VERSION 5.8 ;
BUSBITCHARS "[]" ;
DIVIDERCHAR "/" ;
UNITS
    DATABASE MICRONS 1000 ;
END UNITS

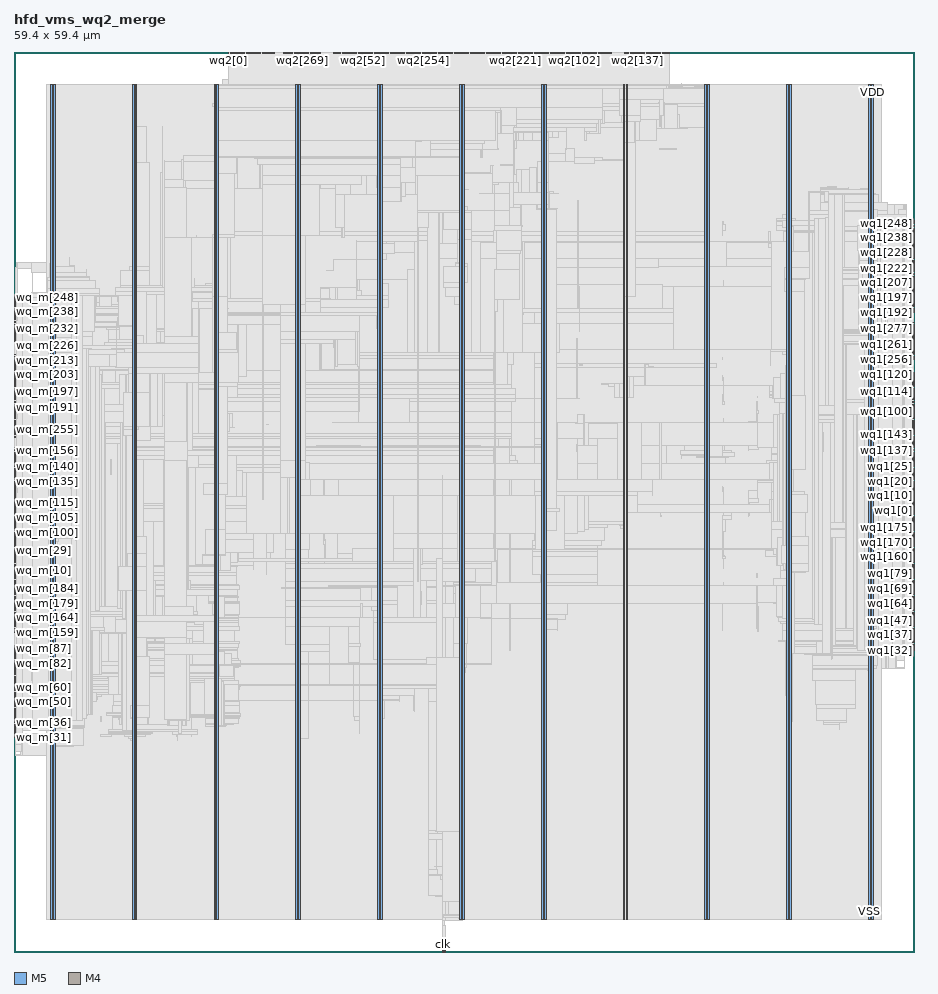
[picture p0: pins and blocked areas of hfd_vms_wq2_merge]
MACRO hfd_vms_wq2_merge
  FOREIGN hfd_vms_wq2_merge 0 0 ;
  CLASS BLOCK ;
  SIZE 59.4 BY 59.4 ;
  PIN clk
    DIRECTION INPUT ;
    USE SIGNAL ;
    PORT
      LAYER M5 ;
        RECT  28.272 0 28.296 0.084 ;
    END
  END clk
  PIN done_m
    DIRECTION INPUT ;
    USE SIGNAL ;
    PORT
      LAYER M4 ;
        RECT  0 24.144 0.084 24.168 ;
    END
  END done_m
  PIN flt
    DIRECTION OUTPUT ;
    USE SIGNAL ;
    PORT
      LAYER M5 ;
        RECT  28.368 0 28.392 0.084 ;
    END
  END flt
  PIN rst_n
    DIRECTION INPUT ;
    USE SIGNAL ;
    PORT
      LAYER M5 ;
        RECT  28.464 0 28.488 0.084 ;
    END
  END rst_n
  PIN wq1[0]
    DIRECTION INPUT ;
    USE SIGNAL ;
    PORT
      LAYER M4 ;
        RECT  59.316 29.136 59.4 29.16 ;
    END
  END wq1[0]
  PIN wq1[100]
    DIRECTION INPUT ;
    USE SIGNAL ;
    PORT
      LAYER M4 ;
        RECT  59.316 35.664 59.4 35.688 ;
    END
  END wq1[100]
  PIN wq1[101]
    DIRECTION INPUT ;
    USE SIGNAL ;
    PORT
      LAYER M4 ;
        RECT  59.316 35.76 59.4 35.784 ;
    END
  END wq1[101]
  PIN wq1[102]
    DIRECTION INPUT ;
    USE SIGNAL ;
    PORT
      LAYER M4 ;
        RECT  59.316 35.856 59.4 35.88 ;
    END
  END wq1[102]
  PIN wq1[103]
    DIRECTION INPUT ;
    USE SIGNAL ;
    PORT
      LAYER M4 ;
        RECT  59.316 35.952 59.4 35.976 ;
    END
  END wq1[103]
  PIN wq1[104]
    DIRECTION INPUT ;
    USE SIGNAL ;
    PORT
      LAYER M4 ;
        RECT  59.316 36.048 59.4 36.072 ;
    END
  END wq1[104]
  PIN wq1[105]
    DIRECTION INPUT ;
    USE SIGNAL ;
    PORT
      LAYER M4 ;
        RECT  59.316 36.144 59.4 36.168 ;
    END
  END wq1[105]
  PIN wq1[106]
    DIRECTION INPUT ;
    USE SIGNAL ;
    PORT
      LAYER M4 ;
        RECT  59.316 36.24 59.4 36.264 ;
    END
  END wq1[106]
  PIN wq1[107]
    DIRECTION INPUT ;
    USE SIGNAL ;
    PORT
      LAYER M4 ;
        RECT  59.316 36.336 59.4 36.36 ;
    END
  END wq1[107]
  PIN wq1[108]
    DIRECTION INPUT ;
    USE SIGNAL ;
    PORT
      LAYER M4 ;
        RECT  59.316 36.432 59.4 36.456 ;
    END
  END wq1[108]
  PIN wq1[109]
    DIRECTION INPUT ;
    USE SIGNAL ;
    PORT
      LAYER M4 ;
        RECT  59.316 36.528 59.4 36.552 ;
    END
  END wq1[109]
  PIN wq1[10]
    DIRECTION INPUT ;
    USE SIGNAL ;
    PORT
      LAYER M4 ;
        RECT  59.316 30.096 59.4 30.12 ;
    END
  END wq1[10]
  PIN wq1[110]
    DIRECTION INPUT ;
    USE SIGNAL ;
    PORT
      LAYER M4 ;
        RECT  59.316 36.624 59.4 36.648 ;
    END
  END wq1[110]
  PIN wq1[111]
    DIRECTION INPUT ;
    USE SIGNAL ;
    PORT
      LAYER M4 ;
        RECT  59.316 36.72 59.4 36.744 ;
    END
  END wq1[111]
  PIN wq1[112]
    DIRECTION INPUT ;
    USE SIGNAL ;
    PORT
      LAYER M4 ;
        RECT  59.316 36.816 59.4 36.84 ;
    END
  END wq1[112]
  PIN wq1[113]
    DIRECTION INPUT ;
    USE SIGNAL ;
    PORT
      LAYER M4 ;
        RECT  59.316 36.912 59.4 36.936 ;
    END
  END wq1[113]
  PIN wq1[114]
    DIRECTION INPUT ;
    USE SIGNAL ;
    PORT
      LAYER M4 ;
        RECT  59.316 37.008 59.4 37.032 ;
    END
  END wq1[114]
  PIN wq1[115]
    DIRECTION INPUT ;
    USE SIGNAL ;
    PORT
      LAYER M4 ;
        RECT  59.316 37.104 59.4 37.128 ;
    END
  END wq1[115]
  PIN wq1[116]
    DIRECTION INPUT ;
    USE SIGNAL ;
    PORT
      LAYER M4 ;
        RECT  59.316 37.2 59.4 37.224 ;
    END
  END wq1[116]
  PIN wq1[117]
    DIRECTION INPUT ;
    USE SIGNAL ;
    PORT
      LAYER M4 ;
        RECT  59.316 37.296 59.4 37.32 ;
    END
  END wq1[117]
  PIN wq1[118]
    DIRECTION INPUT ;
    USE SIGNAL ;
    PORT
      LAYER M4 ;
        RECT  59.316 37.392 59.4 37.416 ;
    END
  END wq1[118]
  PIN wq1[119]
    DIRECTION INPUT ;
    USE SIGNAL ;
    PORT
      LAYER M4 ;
        RECT  59.316 37.488 59.4 37.512 ;
    END
  END wq1[119]
  PIN wq1[11]
    DIRECTION INPUT ;
    USE SIGNAL ;
    PORT
      LAYER M4 ;
        RECT  59.316 30.192 59.4 30.216 ;
    END
  END wq1[11]
  PIN wq1[120]
    DIRECTION INPUT ;
    USE SIGNAL ;
    PORT
      LAYER M4 ;
        RECT  59.316 37.584 59.4 37.608 ;
    END
  END wq1[120]
  PIN wq1[121]
    DIRECTION INPUT ;
    USE SIGNAL ;
    PORT
      LAYER M4 ;
        RECT  59.316 37.68 59.4 37.704 ;
    END
  END wq1[121]
  PIN wq1[122]
    DIRECTION INPUT ;
    USE SIGNAL ;
    PORT
      LAYER M4 ;
        RECT  59.316 37.776 59.4 37.8 ;
    END
  END wq1[122]
  PIN wq1[123]
    DIRECTION INPUT ;
    USE SIGNAL ;
    PORT
      LAYER M4 ;
        RECT  59.316 37.872 59.4 37.896 ;
    END
  END wq1[123]
  PIN wq1[124]
    DIRECTION INPUT ;
    USE SIGNAL ;
    PORT
      LAYER M4 ;
        RECT  59.316 37.968 59.4 37.992 ;
    END
  END wq1[124]
  PIN wq1[125]
    DIRECTION INPUT ;
    USE SIGNAL ;
    PORT
      LAYER M4 ;
        RECT  59.316 38.064 59.4 38.088 ;
    END
  END wq1[125]
  PIN wq1[126]
    DIRECTION INPUT ;
    USE SIGNAL ;
    PORT
      LAYER M4 ;
        RECT  59.316 38.16 59.4 38.184 ;
    END
  END wq1[126]
  PIN wq1[127]
    DIRECTION INPUT ;
    USE SIGNAL ;
    PORT
      LAYER M4 ;
        RECT  59.316 38.256 59.4 38.28 ;
    END
  END wq1[127]
  PIN wq1[128]
    DIRECTION INPUT ;
    USE SIGNAL ;
    PORT
      LAYER M4 ;
        RECT  59.316 32.208 59.4 32.232 ;
    END
  END wq1[128]
  PIN wq1[129]
    DIRECTION INPUT ;
    USE SIGNAL ;
    PORT
      LAYER M4 ;
        RECT  59.316 32.304 59.4 32.328 ;
    END
  END wq1[129]
  PIN wq1[12]
    DIRECTION INPUT ;
    USE SIGNAL ;
    PORT
      LAYER M4 ;
        RECT  59.316 30.288 59.4 30.312 ;
    END
  END wq1[12]
  PIN wq1[130]
    DIRECTION INPUT ;
    USE SIGNAL ;
    PORT
      LAYER M4 ;
        RECT  59.316 32.4 59.4 32.424 ;
    END
  END wq1[130]
  PIN wq1[131]
    DIRECTION INPUT ;
    USE SIGNAL ;
    PORT
      LAYER M4 ;
        RECT  59.316 32.496 59.4 32.52 ;
    END
  END wq1[131]
  PIN wq1[132]
    DIRECTION INPUT ;
    USE SIGNAL ;
    PORT
      LAYER M4 ;
        RECT  59.316 32.592 59.4 32.616 ;
    END
  END wq1[132]
  PIN wq1[133]
    DIRECTION INPUT ;
    USE SIGNAL ;
    PORT
      LAYER M4 ;
        RECT  59.316 32.688 59.4 32.712 ;
    END
  END wq1[133]
  PIN wq1[134]
    DIRECTION INPUT ;
    USE SIGNAL ;
    PORT
      LAYER M4 ;
        RECT  59.316 32.784 59.4 32.808 ;
    END
  END wq1[134]
  PIN wq1[135]
    DIRECTION INPUT ;
    USE SIGNAL ;
    PORT
      LAYER M4 ;
        RECT  59.316 32.88 59.4 32.904 ;
    END
  END wq1[135]
  PIN wq1[136]
    DIRECTION INPUT ;
    USE SIGNAL ;
    PORT
      LAYER M4 ;
        RECT  59.316 32.976 59.4 33 ;
    END
  END wq1[136]
  PIN wq1[137]
    DIRECTION INPUT ;
    USE SIGNAL ;
    PORT
      LAYER M4 ;
        RECT  59.316 33.072 59.4 33.096 ;
    END
  END wq1[137]
  PIN wq1[138]
    DIRECTION INPUT ;
    USE SIGNAL ;
    PORT
      LAYER M4 ;
        RECT  59.316 33.168 59.4 33.192 ;
    END
  END wq1[138]
  PIN wq1[139]
    DIRECTION INPUT ;
    USE SIGNAL ;
    PORT
      LAYER M4 ;
        RECT  59.316 33.264 59.4 33.288 ;
    END
  END wq1[139]
  PIN wq1[13]
    DIRECTION INPUT ;
    USE SIGNAL ;
    PORT
      LAYER M4 ;
        RECT  59.316 30.384 59.4 30.408 ;
    END
  END wq1[13]
  PIN wq1[140]
    DIRECTION INPUT ;
    USE SIGNAL ;
    PORT
      LAYER M4 ;
        RECT  59.316 33.36 59.4 33.384 ;
    END
  END wq1[140]
  PIN wq1[141]
    DIRECTION INPUT ;
    USE SIGNAL ;
    PORT
      LAYER M4 ;
        RECT  59.316 33.456 59.4 33.48 ;
    END
  END wq1[141]
  PIN wq1[142]
    DIRECTION INPUT ;
    USE SIGNAL ;
    PORT
      LAYER M4 ;
        RECT  59.316 33.552 59.4 33.576 ;
    END
  END wq1[142]
  PIN wq1[143]
    DIRECTION INPUT ;
    USE SIGNAL ;
    PORT
      LAYER M4 ;
        RECT  59.316 33.648 59.4 33.672 ;
    END
  END wq1[143]
  PIN wq1[144]
    DIRECTION INPUT ;
    USE SIGNAL ;
    PORT
      LAYER M4 ;
        RECT  59.316 33.744 59.4 33.768 ;
    END
  END wq1[144]
  PIN wq1[145]
    DIRECTION INPUT ;
    USE SIGNAL ;
    PORT
      LAYER M4 ;
        RECT  59.316 33.84 59.4 33.864 ;
    END
  END wq1[145]
  PIN wq1[146]
    DIRECTION INPUT ;
    USE SIGNAL ;
    PORT
      LAYER M4 ;
        RECT  59.316 33.936 59.4 33.96 ;
    END
  END wq1[146]
  PIN wq1[147]
    DIRECTION INPUT ;
    USE SIGNAL ;
    PORT
      LAYER M4 ;
        RECT  59.316 34.032 59.4 34.056 ;
    END
  END wq1[147]
  PIN wq1[148]
    DIRECTION INPUT ;
    USE SIGNAL ;
    PORT
      LAYER M4 ;
        RECT  59.316 34.128 59.4 34.152 ;
    END
  END wq1[148]
  PIN wq1[149]
    DIRECTION INPUT ;
    USE SIGNAL ;
    PORT
      LAYER M4 ;
        RECT  59.316 34.224 59.4 34.248 ;
    END
  END wq1[149]
  PIN wq1[14]
    DIRECTION INPUT ;
    USE SIGNAL ;
    PORT
      LAYER M4 ;
        RECT  59.316 30.48 59.4 30.504 ;
    END
  END wq1[14]
  PIN wq1[150]
    DIRECTION INPUT ;
    USE SIGNAL ;
    PORT
      LAYER M4 ;
        RECT  59.316 34.32 59.4 34.344 ;
    END
  END wq1[150]
  PIN wq1[151]
    DIRECTION INPUT ;
    USE SIGNAL ;
    PORT
      LAYER M4 ;
        RECT  59.316 34.416 59.4 34.44 ;
    END
  END wq1[151]
  PIN wq1[152]
    DIRECTION INPUT ;
    USE SIGNAL ;
    PORT
      LAYER M4 ;
        RECT  59.316 34.512 59.4 34.536 ;
    END
  END wq1[152]
  PIN wq1[153]
    DIRECTION INPUT ;
    USE SIGNAL ;
    PORT
      LAYER M4 ;
        RECT  59.316 34.608 59.4 34.632 ;
    END
  END wq1[153]
  PIN wq1[154]
    DIRECTION INPUT ;
    USE SIGNAL ;
    PORT
      LAYER M4 ;
        RECT  59.316 34.704 59.4 34.728 ;
    END
  END wq1[154]
  PIN wq1[155]
    DIRECTION INPUT ;
    USE SIGNAL ;
    PORT
      LAYER M4 ;
        RECT  59.316 34.8 59.4 34.824 ;
    END
  END wq1[155]
  PIN wq1[156]
    DIRECTION INPUT ;
    USE SIGNAL ;
    PORT
      LAYER M4 ;
        RECT  59.316 34.896 59.4 34.92 ;
    END
  END wq1[156]
  PIN wq1[157]
    DIRECTION INPUT ;
    USE SIGNAL ;
    PORT
      LAYER M4 ;
        RECT  59.316 34.992 59.4 35.016 ;
    END
  END wq1[157]
  PIN wq1[158]
    DIRECTION INPUT ;
    USE SIGNAL ;
    PORT
      LAYER M4 ;
        RECT  59.316 35.088 59.4 35.112 ;
    END
  END wq1[158]
  PIN wq1[159]
    DIRECTION INPUT ;
    USE SIGNAL ;
    PORT
      LAYER M4 ;
        RECT  59.316 35.184 59.4 35.208 ;
    END
  END wq1[159]
  PIN wq1[15]
    DIRECTION INPUT ;
    USE SIGNAL ;
    PORT
      LAYER M4 ;
        RECT  59.316 30.576 59.4 30.6 ;
    END
  END wq1[15]
  PIN wq1[160]
    DIRECTION INPUT ;
    USE SIGNAL ;
    PORT
      LAYER M4 ;
        RECT  59.316 26.064 59.4 26.088 ;
    END
  END wq1[160]
  PIN wq1[161]
    DIRECTION INPUT ;
    USE SIGNAL ;
    PORT
      LAYER M4 ;
        RECT  59.316 26.16 59.4 26.184 ;
    END
  END wq1[161]
  PIN wq1[162]
    DIRECTION INPUT ;
    USE SIGNAL ;
    PORT
      LAYER M4 ;
        RECT  59.316 26.256 59.4 26.28 ;
    END
  END wq1[162]
  PIN wq1[163]
    DIRECTION INPUT ;
    USE SIGNAL ;
    PORT
      LAYER M4 ;
        RECT  59.316 26.352 59.4 26.376 ;
    END
  END wq1[163]
  PIN wq1[164]
    DIRECTION INPUT ;
    USE SIGNAL ;
    PORT
      LAYER M4 ;
        RECT  59.316 26.448 59.4 26.472 ;
    END
  END wq1[164]
  PIN wq1[165]
    DIRECTION INPUT ;
    USE SIGNAL ;
    PORT
      LAYER M4 ;
        RECT  59.316 26.544 59.4 26.568 ;
    END
  END wq1[165]
  PIN wq1[166]
    DIRECTION INPUT ;
    USE SIGNAL ;
    PORT
      LAYER M4 ;
        RECT  59.316 26.64 59.4 26.664 ;
    END
  END wq1[166]
  PIN wq1[167]
    DIRECTION INPUT ;
    USE SIGNAL ;
    PORT
      LAYER M4 ;
        RECT  59.316 26.736 59.4 26.76 ;
    END
  END wq1[167]
  PIN wq1[168]
    DIRECTION INPUT ;
    USE SIGNAL ;
    PORT
      LAYER M4 ;
        RECT  59.316 26.832 59.4 26.856 ;
    END
  END wq1[168]
  PIN wq1[169]
    DIRECTION INPUT ;
    USE SIGNAL ;
    PORT
      LAYER M4 ;
        RECT  59.316 26.928 59.4 26.952 ;
    END
  END wq1[169]
  PIN wq1[16]
    DIRECTION INPUT ;
    USE SIGNAL ;
    PORT
      LAYER M4 ;
        RECT  59.316 30.672 59.4 30.696 ;
    END
  END wq1[16]
  PIN wq1[170]
    DIRECTION INPUT ;
    USE SIGNAL ;
    PORT
      LAYER M4 ;
        RECT  59.316 27.024 59.4 27.048 ;
    END
  END wq1[170]
  PIN wq1[171]
    DIRECTION INPUT ;
    USE SIGNAL ;
    PORT
      LAYER M4 ;
        RECT  59.316 27.12 59.4 27.144 ;
    END
  END wq1[171]
  PIN wq1[172]
    DIRECTION INPUT ;
    USE SIGNAL ;
    PORT
      LAYER M4 ;
        RECT  59.316 27.216 59.4 27.24 ;
    END
  END wq1[172]
  PIN wq1[173]
    DIRECTION INPUT ;
    USE SIGNAL ;
    PORT
      LAYER M4 ;
        RECT  59.316 27.312 59.4 27.336 ;
    END
  END wq1[173]
  PIN wq1[174]
    DIRECTION INPUT ;
    USE SIGNAL ;
    PORT
      LAYER M4 ;
        RECT  59.316 27.408 59.4 27.432 ;
    END
  END wq1[174]
  PIN wq1[175]
    DIRECTION INPUT ;
    USE SIGNAL ;
    PORT
      LAYER M4 ;
        RECT  59.316 27.504 59.4 27.528 ;
    END
  END wq1[175]
  PIN wq1[176]
    DIRECTION INPUT ;
    USE SIGNAL ;
    PORT
      LAYER M4 ;
        RECT  59.316 27.6 59.4 27.624 ;
    END
  END wq1[176]
  PIN wq1[177]
    DIRECTION INPUT ;
    USE SIGNAL ;
    PORT
      LAYER M4 ;
        RECT  59.316 27.696 59.4 27.72 ;
    END
  END wq1[177]
  PIN wq1[178]
    DIRECTION INPUT ;
    USE SIGNAL ;
    PORT
      LAYER M4 ;
        RECT  59.316 27.792 59.4 27.816 ;
    END
  END wq1[178]
  PIN wq1[179]
    DIRECTION INPUT ;
    USE SIGNAL ;
    PORT
      LAYER M4 ;
        RECT  59.316 27.888 59.4 27.912 ;
    END
  END wq1[179]
  PIN wq1[17]
    DIRECTION INPUT ;
    USE SIGNAL ;
    PORT
      LAYER M4 ;
        RECT  59.316 30.768 59.4 30.792 ;
    END
  END wq1[17]
  PIN wq1[180]
    DIRECTION INPUT ;
    USE SIGNAL ;
    PORT
      LAYER M4 ;
        RECT  59.316 27.984 59.4 28.008 ;
    END
  END wq1[180]
  PIN wq1[181]
    DIRECTION INPUT ;
    USE SIGNAL ;
    PORT
      LAYER M4 ;
        RECT  59.316 28.08 59.4 28.104 ;
    END
  END wq1[181]
  PIN wq1[182]
    DIRECTION INPUT ;
    USE SIGNAL ;
    PORT
      LAYER M4 ;
        RECT  59.316 28.176 59.4 28.2 ;
    END
  END wq1[182]
  PIN wq1[183]
    DIRECTION INPUT ;
    USE SIGNAL ;
    PORT
      LAYER M4 ;
        RECT  59.316 28.272 59.4 28.296 ;
    END
  END wq1[183]
  PIN wq1[184]
    DIRECTION INPUT ;
    USE SIGNAL ;
    PORT
      LAYER M4 ;
        RECT  59.316 28.368 59.4 28.392 ;
    END
  END wq1[184]
  PIN wq1[185]
    DIRECTION INPUT ;
    USE SIGNAL ;
    PORT
      LAYER M4 ;
        RECT  59.316 28.464 59.4 28.488 ;
    END
  END wq1[185]
  PIN wq1[186]
    DIRECTION INPUT ;
    USE SIGNAL ;
    PORT
      LAYER M4 ;
        RECT  59.316 28.56 59.4 28.584 ;
    END
  END wq1[186]
  PIN wq1[187]
    DIRECTION INPUT ;
    USE SIGNAL ;
    PORT
      LAYER M4 ;
        RECT  59.316 28.656 59.4 28.68 ;
    END
  END wq1[187]
  PIN wq1[188]
    DIRECTION INPUT ;
    USE SIGNAL ;
    PORT
      LAYER M4 ;
        RECT  59.316 28.752 59.4 28.776 ;
    END
  END wq1[188]
  PIN wq1[189]
    DIRECTION INPUT ;
    USE SIGNAL ;
    PORT
      LAYER M4 ;
        RECT  59.316 28.848 59.4 28.872 ;
    END
  END wq1[189]
  PIN wq1[18]
    DIRECTION INPUT ;
    USE SIGNAL ;
    PORT
      LAYER M4 ;
        RECT  59.316 30.864 59.4 30.888 ;
    END
  END wq1[18]
  PIN wq1[190]
    DIRECTION INPUT ;
    USE SIGNAL ;
    PORT
      LAYER M4 ;
        RECT  59.316 28.944 59.4 28.968 ;
    END
  END wq1[190]
  PIN wq1[191]
    DIRECTION INPUT ;
    USE SIGNAL ;
    PORT
      LAYER M4 ;
        RECT  59.316 29.04 59.4 29.064 ;
    END
  END wq1[191]
  PIN wq1[192]
    DIRECTION INPUT ;
    USE SIGNAL ;
    PORT
      LAYER M4 ;
        RECT  59.316 42.192 59.4 42.216 ;
    END
  END wq1[192]
  PIN wq1[193]
    DIRECTION INPUT ;
    USE SIGNAL ;
    PORT
      LAYER M4 ;
        RECT  59.316 42.288 59.4 42.312 ;
    END
  END wq1[193]
  PIN wq1[194]
    DIRECTION INPUT ;
    USE SIGNAL ;
    PORT
      LAYER M4 ;
        RECT  59.316 42.384 59.4 42.408 ;
    END
  END wq1[194]
  PIN wq1[195]
    DIRECTION INPUT ;
    USE SIGNAL ;
    PORT
      LAYER M4 ;
        RECT  59.316 42.48 59.4 42.504 ;
    END
  END wq1[195]
  PIN wq1[196]
    DIRECTION INPUT ;
    USE SIGNAL ;
    PORT
      LAYER M4 ;
        RECT  59.316 42.576 59.4 42.6 ;
    END
  END wq1[196]
  PIN wq1[197]
    DIRECTION INPUT ;
    USE SIGNAL ;
    PORT
      LAYER M4 ;
        RECT  59.316 42.672 59.4 42.696 ;
    END
  END wq1[197]
  PIN wq1[198]
    DIRECTION INPUT ;
    USE SIGNAL ;
    PORT
      LAYER M4 ;
        RECT  59.316 42.768 59.4 42.792 ;
    END
  END wq1[198]
  PIN wq1[199]
    DIRECTION INPUT ;
    USE SIGNAL ;
    PORT
      LAYER M4 ;
        RECT  59.316 42.864 59.4 42.888 ;
    END
  END wq1[199]
  PIN wq1[19]
    DIRECTION INPUT ;
    USE SIGNAL ;
    PORT
      LAYER M4 ;
        RECT  59.316 30.96 59.4 30.984 ;
    END
  END wq1[19]
  PIN wq1[1]
    DIRECTION INPUT ;
    USE SIGNAL ;
    PORT
      LAYER M4 ;
        RECT  59.316 29.232 59.4 29.256 ;
    END
  END wq1[1]
  PIN wq1[200]
    DIRECTION INPUT ;
    USE SIGNAL ;
    PORT
      LAYER M4 ;
        RECT  59.316 42.96 59.4 42.984 ;
    END
  END wq1[200]
  PIN wq1[201]
    DIRECTION INPUT ;
    USE SIGNAL ;
    PORT
      LAYER M4 ;
        RECT  59.316 43.056 59.4 43.08 ;
    END
  END wq1[201]
  PIN wq1[202]
    DIRECTION INPUT ;
    USE SIGNAL ;
    PORT
      LAYER M4 ;
        RECT  59.316 43.152 59.4 43.176 ;
    END
  END wq1[202]
  PIN wq1[203]
    DIRECTION INPUT ;
    USE SIGNAL ;
    PORT
      LAYER M4 ;
        RECT  59.316 43.248 59.4 43.272 ;
    END
  END wq1[203]
  PIN wq1[204]
    DIRECTION INPUT ;
    USE SIGNAL ;
    PORT
      LAYER M4 ;
        RECT  59.316 43.344 59.4 43.368 ;
    END
  END wq1[204]
  PIN wq1[205]
    DIRECTION INPUT ;
    USE SIGNAL ;
    PORT
      LAYER M4 ;
        RECT  59.316 43.44 59.4 43.464 ;
    END
  END wq1[205]
  PIN wq1[206]
    DIRECTION INPUT ;
    USE SIGNAL ;
    PORT
      LAYER M4 ;
        RECT  59.316 43.536 59.4 43.56 ;
    END
  END wq1[206]
  PIN wq1[207]
    DIRECTION INPUT ;
    USE SIGNAL ;
    PORT
      LAYER M4 ;
        RECT  59.316 43.632 59.4 43.656 ;
    END
  END wq1[207]
  PIN wq1[208]
    DIRECTION INPUT ;
    USE SIGNAL ;
    PORT
      LAYER M4 ;
        RECT  59.316 43.728 59.4 43.752 ;
    END
  END wq1[208]
  PIN wq1[209]
    DIRECTION INPUT ;
    USE SIGNAL ;
    PORT
      LAYER M4 ;
        RECT  59.316 43.824 59.4 43.848 ;
    END
  END wq1[209]
  PIN wq1[20]
    DIRECTION INPUT ;
    USE SIGNAL ;
    PORT
      LAYER M4 ;
        RECT  59.316 31.056 59.4 31.08 ;
    END
  END wq1[20]
  PIN wq1[210]
    DIRECTION INPUT ;
    USE SIGNAL ;
    PORT
      LAYER M4 ;
        RECT  59.316 43.92 59.4 43.944 ;
    END
  END wq1[210]
  PIN wq1[211]
    DIRECTION INPUT ;
    USE SIGNAL ;
    PORT
      LAYER M4 ;
        RECT  59.316 44.016 59.4 44.04 ;
    END
  END wq1[211]
  PIN wq1[212]
    DIRECTION INPUT ;
    USE SIGNAL ;
    PORT
      LAYER M4 ;
        RECT  59.316 44.112 59.4 44.136 ;
    END
  END wq1[212]
  PIN wq1[213]
    DIRECTION INPUT ;
    USE SIGNAL ;
    PORT
      LAYER M4 ;
        RECT  59.316 44.208 59.4 44.232 ;
    END
  END wq1[213]
  PIN wq1[214]
    DIRECTION INPUT ;
    USE SIGNAL ;
    PORT
      LAYER M4 ;
        RECT  59.316 44.304 59.4 44.328 ;
    END
  END wq1[214]
  PIN wq1[215]
    DIRECTION INPUT ;
    USE SIGNAL ;
    PORT
      LAYER M4 ;
        RECT  59.316 44.4 59.4 44.424 ;
    END
  END wq1[215]
  PIN wq1[216]
    DIRECTION INPUT ;
    USE SIGNAL ;
    PORT
      LAYER M4 ;
        RECT  59.316 44.496 59.4 44.52 ;
    END
  END wq1[216]
  PIN wq1[217]
    DIRECTION INPUT ;
    USE SIGNAL ;
    PORT
      LAYER M4 ;
        RECT  59.316 44.592 59.4 44.616 ;
    END
  END wq1[217]
  PIN wq1[218]
    DIRECTION INPUT ;
    USE SIGNAL ;
    PORT
      LAYER M4 ;
        RECT  59.316 44.688 59.4 44.712 ;
    END
  END wq1[218]
  PIN wq1[219]
    DIRECTION INPUT ;
    USE SIGNAL ;
    PORT
      LAYER M4 ;
        RECT  59.316 44.784 59.4 44.808 ;
    END
  END wq1[219]
  PIN wq1[21]
    DIRECTION INPUT ;
    USE SIGNAL ;
    PORT
      LAYER M4 ;
        RECT  59.316 31.152 59.4 31.176 ;
    END
  END wq1[21]
  PIN wq1[220]
    DIRECTION INPUT ;
    USE SIGNAL ;
    PORT
      LAYER M4 ;
        RECT  59.316 44.88 59.4 44.904 ;
    END
  END wq1[220]
  PIN wq1[221]
    DIRECTION INPUT ;
    USE SIGNAL ;
    PORT
      LAYER M4 ;
        RECT  59.316 44.976 59.4 45 ;
    END
  END wq1[221]
  PIN wq1[222]
    DIRECTION INPUT ;
    USE SIGNAL ;
    PORT
      LAYER M4 ;
        RECT  59.316 45.072 59.4 45.096 ;
    END
  END wq1[222]
  PIN wq1[223]
    DIRECTION INPUT ;
    USE SIGNAL ;
    PORT
      LAYER M4 ;
        RECT  59.316 45.168 59.4 45.192 ;
    END
  END wq1[223]
  PIN wq1[224]
    DIRECTION INPUT ;
    USE SIGNAL ;
    PORT
      LAYER M4 ;
        RECT  59.316 45.264 59.4 45.288 ;
    END
  END wq1[224]
  PIN wq1[225]
    DIRECTION INPUT ;
    USE SIGNAL ;
    PORT
      LAYER M4 ;
        RECT  59.316 45.36 59.4 45.384 ;
    END
  END wq1[225]
  PIN wq1[226]
    DIRECTION INPUT ;
    USE SIGNAL ;
    PORT
      LAYER M4 ;
        RECT  59.316 45.456 59.4 45.48 ;
    END
  END wq1[226]
  PIN wq1[227]
    DIRECTION INPUT ;
    USE SIGNAL ;
    PORT
      LAYER M4 ;
        RECT  59.316 45.552 59.4 45.576 ;
    END
  END wq1[227]
  PIN wq1[228]
    DIRECTION INPUT ;
    USE SIGNAL ;
    PORT
      LAYER M4 ;
        RECT  59.316 45.648 59.4 45.672 ;
    END
  END wq1[228]
  PIN wq1[229]
    DIRECTION INPUT ;
    USE SIGNAL ;
    PORT
      LAYER M4 ;
        RECT  59.316 45.744 59.4 45.768 ;
    END
  END wq1[229]
  PIN wq1[22]
    DIRECTION INPUT ;
    USE SIGNAL ;
    PORT
      LAYER M4 ;
        RECT  59.316 31.248 59.4 31.272 ;
    END
  END wq1[22]
  PIN wq1[230]
    DIRECTION INPUT ;
    USE SIGNAL ;
    PORT
      LAYER M4 ;
        RECT  59.316 45.84 59.4 45.864 ;
    END
  END wq1[230]
  PIN wq1[231]
    DIRECTION INPUT ;
    USE SIGNAL ;
    PORT
      LAYER M4 ;
        RECT  59.316 45.936 59.4 45.96 ;
    END
  END wq1[231]
  PIN wq1[232]
    DIRECTION INPUT ;
    USE SIGNAL ;
    PORT
      LAYER M4 ;
        RECT  59.316 46.032 59.4 46.056 ;
    END
  END wq1[232]
  PIN wq1[233]
    DIRECTION INPUT ;
    USE SIGNAL ;
    PORT
      LAYER M4 ;
        RECT  59.316 46.128 59.4 46.152 ;
    END
  END wq1[233]
  PIN wq1[234]
    DIRECTION INPUT ;
    USE SIGNAL ;
    PORT
      LAYER M4 ;
        RECT  59.316 46.224 59.4 46.248 ;
    END
  END wq1[234]
  PIN wq1[235]
    DIRECTION INPUT ;
    USE SIGNAL ;
    PORT
      LAYER M4 ;
        RECT  59.316 46.32 59.4 46.344 ;
    END
  END wq1[235]
  PIN wq1[236]
    DIRECTION INPUT ;
    USE SIGNAL ;
    PORT
      LAYER M4 ;
        RECT  59.316 46.416 59.4 46.44 ;
    END
  END wq1[236]
  PIN wq1[237]
    DIRECTION INPUT ;
    USE SIGNAL ;
    PORT
      LAYER M4 ;
        RECT  59.316 46.512 59.4 46.536 ;
    END
  END wq1[237]
  PIN wq1[238]
    DIRECTION INPUT ;
    USE SIGNAL ;
    PORT
      LAYER M4 ;
        RECT  59.316 46.608 59.4 46.632 ;
    END
  END wq1[238]
  PIN wq1[239]
    DIRECTION INPUT ;
    USE SIGNAL ;
    PORT
      LAYER M4 ;
        RECT  59.316 46.704 59.4 46.728 ;
    END
  END wq1[239]
  PIN wq1[23]
    DIRECTION INPUT ;
    USE SIGNAL ;
    PORT
      LAYER M4 ;
        RECT  59.316 31.344 59.4 31.368 ;
    END
  END wq1[23]
  PIN wq1[240]
    DIRECTION INPUT ;
    USE SIGNAL ;
    PORT
      LAYER M4 ;
        RECT  59.316 46.8 59.4 46.824 ;
    END
  END wq1[240]
  PIN wq1[241]
    DIRECTION INPUT ;
    USE SIGNAL ;
    PORT
      LAYER M4 ;
        RECT  59.316 46.896 59.4 46.92 ;
    END
  END wq1[241]
  PIN wq1[242]
    DIRECTION INPUT ;
    USE SIGNAL ;
    PORT
      LAYER M4 ;
        RECT  59.316 46.992 59.4 47.016 ;
    END
  END wq1[242]
  PIN wq1[243]
    DIRECTION INPUT ;
    USE SIGNAL ;
    PORT
      LAYER M4 ;
        RECT  59.316 47.088 59.4 47.112 ;
    END
  END wq1[243]
  PIN wq1[244]
    DIRECTION INPUT ;
    USE SIGNAL ;
    PORT
      LAYER M4 ;
        RECT  59.316 47.184 59.4 47.208 ;
    END
  END wq1[244]
  PIN wq1[245]
    DIRECTION INPUT ;
    USE SIGNAL ;
    PORT
      LAYER M4 ;
        RECT  59.316 47.28 59.4 47.304 ;
    END
  END wq1[245]
  PIN wq1[246]
    DIRECTION INPUT ;
    USE SIGNAL ;
    PORT
      LAYER M4 ;
        RECT  59.316 47.376 59.4 47.4 ;
    END
  END wq1[246]
  PIN wq1[247]
    DIRECTION INPUT ;
    USE SIGNAL ;
    PORT
      LAYER M4 ;
        RECT  59.316 47.472 59.4 47.496 ;
    END
  END wq1[247]
  PIN wq1[248]
    DIRECTION INPUT ;
    USE SIGNAL ;
    PORT
      LAYER M4 ;
        RECT  59.316 47.568 59.4 47.592 ;
    END
  END wq1[248]
  PIN wq1[249]
    DIRECTION INPUT ;
    USE SIGNAL ;
    PORT
      LAYER M4 ;
        RECT  59.316 47.664 59.4 47.688 ;
    END
  END wq1[249]
  PIN wq1[24]
    DIRECTION INPUT ;
    USE SIGNAL ;
    PORT
      LAYER M4 ;
        RECT  59.316 31.44 59.4 31.464 ;
    END
  END wq1[24]
  PIN wq1[250]
    DIRECTION INPUT ;
    USE SIGNAL ;
    PORT
      LAYER M4 ;
        RECT  59.316 47.76 59.4 47.784 ;
    END
  END wq1[250]
  PIN wq1[251]
    DIRECTION INPUT ;
    USE SIGNAL ;
    PORT
      LAYER M4 ;
        RECT  59.316 47.856 59.4 47.88 ;
    END
  END wq1[251]
  PIN wq1[252]
    DIRECTION INPUT ;
    USE SIGNAL ;
    PORT
      LAYER M4 ;
        RECT  59.316 47.952 59.4 47.976 ;
    END
  END wq1[252]
  PIN wq1[253]
    DIRECTION INPUT ;
    USE SIGNAL ;
    PORT
      LAYER M4 ;
        RECT  59.316 48.048 59.4 48.072 ;
    END
  END wq1[253]
  PIN wq1[254]
    DIRECTION INPUT ;
    USE SIGNAL ;
    PORT
      LAYER M4 ;
        RECT  59.316 48.144 59.4 48.168 ;
    END
  END wq1[254]
  PIN wq1[255]
    DIRECTION INPUT ;
    USE SIGNAL ;
    PORT
      LAYER M4 ;
        RECT  59.316 48.24 59.4 48.264 ;
    END
  END wq1[255]
  PIN wq1[256]
    DIRECTION INPUT ;
    USE SIGNAL ;
    PORT
      LAYER M4 ;
        RECT  59.316 39.12 59.4 39.144 ;
    END
  END wq1[256]
  PIN wq1[257]
    DIRECTION INPUT ;
    USE SIGNAL ;
    PORT
      LAYER M4 ;
        RECT  59.316 39.216 59.4 39.24 ;
    END
  END wq1[257]
  PIN wq1[258]
    DIRECTION INPUT ;
    USE SIGNAL ;
    PORT
      LAYER M4 ;
        RECT  59.316 39.312 59.4 39.336 ;
    END
  END wq1[258]
  PIN wq1[259]
    DIRECTION INPUT ;
    USE SIGNAL ;
    PORT
      LAYER M4 ;
        RECT  59.316 39.408 59.4 39.432 ;
    END
  END wq1[259]
  PIN wq1[25]
    DIRECTION INPUT ;
    USE SIGNAL ;
    PORT
      LAYER M4 ;
        RECT  59.316 31.536 59.4 31.56 ;
    END
  END wq1[25]
  PIN wq1[260]
    DIRECTION INPUT ;
    USE SIGNAL ;
    PORT
      LAYER M4 ;
        RECT  59.316 39.504 59.4 39.528 ;
    END
  END wq1[260]
  PIN wq1[261]
    DIRECTION INPUT ;
    USE SIGNAL ;
    PORT
      LAYER M4 ;
        RECT  59.316 39.6 59.4 39.624 ;
    END
  END wq1[261]
  PIN wq1[262]
    DIRECTION INPUT ;
    USE SIGNAL ;
    PORT
      LAYER M4 ;
        RECT  59.316 39.696 59.4 39.72 ;
    END
  END wq1[262]
  PIN wq1[263]
    DIRECTION INPUT ;
    USE SIGNAL ;
    PORT
      LAYER M4 ;
        RECT  59.316 39.792 59.4 39.816 ;
    END
  END wq1[263]
  PIN wq1[264]
    DIRECTION INPUT ;
    USE SIGNAL ;
    PORT
      LAYER M4 ;
        RECT  59.316 39.888 59.4 39.912 ;
    END
  END wq1[264]
  PIN wq1[265]
    DIRECTION INPUT ;
    USE SIGNAL ;
    PORT
      LAYER M4 ;
        RECT  59.316 39.984 59.4 40.008 ;
    END
  END wq1[265]
  PIN wq1[266]
    DIRECTION INPUT ;
    USE SIGNAL ;
    PORT
      LAYER M4 ;
        RECT  59.316 40.08 59.4 40.104 ;
    END
  END wq1[266]
  PIN wq1[267]
    DIRECTION INPUT ;
    USE SIGNAL ;
    PORT
      LAYER M4 ;
        RECT  59.316 40.176 59.4 40.2 ;
    END
  END wq1[267]
  PIN wq1[268]
    DIRECTION INPUT ;
    USE SIGNAL ;
    PORT
      LAYER M4 ;
        RECT  59.316 40.272 59.4 40.296 ;
    END
  END wq1[268]
  PIN wq1[269]
    DIRECTION INPUT ;
    USE SIGNAL ;
    PORT
      LAYER M4 ;
        RECT  59.316 40.368 59.4 40.392 ;
    END
  END wq1[269]
  PIN wq1[26]
    DIRECTION INPUT ;
    USE SIGNAL ;
    PORT
      LAYER M4 ;
        RECT  59.316 31.632 59.4 31.656 ;
    END
  END wq1[26]
  PIN wq1[270]
    DIRECTION INPUT ;
    USE SIGNAL ;
    PORT
      LAYER M4 ;
        RECT  59.316 40.464 59.4 40.488 ;
    END
  END wq1[270]
  PIN wq1[271]
    DIRECTION INPUT ;
    USE SIGNAL ;
    PORT
      LAYER M4 ;
        RECT  59.316 40.56 59.4 40.584 ;
    END
  END wq1[271]
  PIN wq1[272]
    DIRECTION INPUT ;
    USE SIGNAL ;
    PORT
      LAYER M4 ;
        RECT  59.316 40.656 59.4 40.68 ;
    END
  END wq1[272]
  PIN wq1[273]
    DIRECTION INPUT ;
    USE SIGNAL ;
    PORT
      LAYER M4 ;
        RECT  59.316 40.752 59.4 40.776 ;
    END
  END wq1[273]
  PIN wq1[274]
    DIRECTION INPUT ;
    USE SIGNAL ;
    PORT
      LAYER M4 ;
        RECT  59.316 40.848 59.4 40.872 ;
    END
  END wq1[274]
  PIN wq1[275]
    DIRECTION INPUT ;
    USE SIGNAL ;
    PORT
      LAYER M4 ;
        RECT  59.316 40.944 59.4 40.968 ;
    END
  END wq1[275]
  PIN wq1[276]
    DIRECTION INPUT ;
    USE SIGNAL ;
    PORT
      LAYER M4 ;
        RECT  59.316 41.04 59.4 41.064 ;
    END
  END wq1[276]
  PIN wq1[277]
    DIRECTION INPUT ;
    USE SIGNAL ;
    PORT
      LAYER M4 ;
        RECT  59.316 41.136 59.4 41.16 ;
    END
  END wq1[277]
  PIN wq1[278]
    DIRECTION INPUT ;
    USE SIGNAL ;
    PORT
      LAYER M4 ;
        RECT  59.316 41.232 59.4 41.256 ;
    END
  END wq1[278]
  PIN wq1[279]
    DIRECTION INPUT ;
    USE SIGNAL ;
    PORT
      LAYER M4 ;
        RECT  59.316 41.328 59.4 41.352 ;
    END
  END wq1[279]
  PIN wq1[27]
    DIRECTION INPUT ;
    USE SIGNAL ;
    PORT
      LAYER M4 ;
        RECT  59.316 31.728 59.4 31.752 ;
    END
  END wq1[27]
  PIN wq1[280]
    DIRECTION INPUT ;
    USE SIGNAL ;
    PORT
      LAYER M4 ;
        RECT  59.316 41.424 59.4 41.448 ;
    END
  END wq1[280]
  PIN wq1[28]
    DIRECTION INPUT ;
    USE SIGNAL ;
    PORT
      LAYER M4 ;
        RECT  59.316 31.824 59.4 31.848 ;
    END
  END wq1[28]
  PIN wq1[29]
    DIRECTION INPUT ;
    USE SIGNAL ;
    PORT
      LAYER M4 ;
        RECT  59.316 31.92 59.4 31.944 ;
    END
  END wq1[29]
  PIN wq1[2]
    DIRECTION INPUT ;
    USE SIGNAL ;
    PORT
      LAYER M4 ;
        RECT  59.316 29.328 59.4 29.352 ;
    END
  END wq1[2]
  PIN wq1[30]
    DIRECTION INPUT ;
    USE SIGNAL ;
    PORT
      LAYER M4 ;
        RECT  59.316 32.016 59.4 32.04 ;
    END
  END wq1[30]
  PIN wq1[31]
    DIRECTION INPUT ;
    USE SIGNAL ;
    PORT
      LAYER M4 ;
        RECT  59.316 32.112 59.4 32.136 ;
    END
  END wq1[31]
  PIN wq1[32]
    DIRECTION INPUT ;
    USE SIGNAL ;
    PORT
      LAYER M4 ;
        RECT  59.316 19.92 59.4 19.944 ;
    END
  END wq1[32]
  PIN wq1[33]
    DIRECTION INPUT ;
    USE SIGNAL ;
    PORT
      LAYER M4 ;
        RECT  59.316 20.016 59.4 20.04 ;
    END
  END wq1[33]
  PIN wq1[34]
    DIRECTION INPUT ;
    USE SIGNAL ;
    PORT
      LAYER M4 ;
        RECT  59.316 20.112 59.4 20.136 ;
    END
  END wq1[34]
  PIN wq1[35]
    DIRECTION INPUT ;
    USE SIGNAL ;
    PORT
      LAYER M4 ;
        RECT  59.316 20.208 59.4 20.232 ;
    END
  END wq1[35]
  PIN wq1[36]
    DIRECTION INPUT ;
    USE SIGNAL ;
    PORT
      LAYER M4 ;
        RECT  59.316 20.304 59.4 20.328 ;
    END
  END wq1[36]
  PIN wq1[37]
    DIRECTION INPUT ;
    USE SIGNAL ;
    PORT
      LAYER M4 ;
        RECT  59.316 20.4 59.4 20.424 ;
    END
  END wq1[37]
  PIN wq1[38]
    DIRECTION INPUT ;
    USE SIGNAL ;
    PORT
      LAYER M4 ;
        RECT  59.316 20.496 59.4 20.52 ;
    END
  END wq1[38]
  PIN wq1[39]
    DIRECTION INPUT ;
    USE SIGNAL ;
    PORT
      LAYER M4 ;
        RECT  59.316 20.592 59.4 20.616 ;
    END
  END wq1[39]
  PIN wq1[3]
    DIRECTION INPUT ;
    USE SIGNAL ;
    PORT
      LAYER M4 ;
        RECT  59.316 29.424 59.4 29.448 ;
    END
  END wq1[3]
  PIN wq1[40]
    DIRECTION INPUT ;
    USE SIGNAL ;
    PORT
      LAYER M4 ;
        RECT  59.316 20.688 59.4 20.712 ;
    END
  END wq1[40]
  PIN wq1[41]
    DIRECTION INPUT ;
    USE SIGNAL ;
    PORT
      LAYER M4 ;
        RECT  59.316 20.784 59.4 20.808 ;
    END
  END wq1[41]
  PIN wq1[42]
    DIRECTION INPUT ;
    USE SIGNAL ;
    PORT
      LAYER M4 ;
        RECT  59.316 20.88 59.4 20.904 ;
    END
  END wq1[42]
  PIN wq1[43]
    DIRECTION INPUT ;
    USE SIGNAL ;
    PORT
      LAYER M4 ;
        RECT  59.316 20.976 59.4 21 ;
    END
  END wq1[43]
  PIN wq1[44]
    DIRECTION INPUT ;
    USE SIGNAL ;
    PORT
      LAYER M4 ;
        RECT  59.316 21.072 59.4 21.096 ;
    END
  END wq1[44]
  PIN wq1[45]
    DIRECTION INPUT ;
    USE SIGNAL ;
    PORT
      LAYER M4 ;
        RECT  59.316 21.168 59.4 21.192 ;
    END
  END wq1[45]
  PIN wq1[46]
    DIRECTION INPUT ;
    USE SIGNAL ;
    PORT
      LAYER M4 ;
        RECT  59.316 21.264 59.4 21.288 ;
    END
  END wq1[46]
  PIN wq1[47]
    DIRECTION INPUT ;
    USE SIGNAL ;
    PORT
      LAYER M4 ;
        RECT  59.316 21.36 59.4 21.384 ;
    END
  END wq1[47]
  PIN wq1[48]
    DIRECTION INPUT ;
    USE SIGNAL ;
    PORT
      LAYER M4 ;
        RECT  59.316 21.456 59.4 21.48 ;
    END
  END wq1[48]
  PIN wq1[49]
    DIRECTION INPUT ;
    USE SIGNAL ;
    PORT
      LAYER M4 ;
        RECT  59.316 21.552 59.4 21.576 ;
    END
  END wq1[49]
  PIN wq1[4]
    DIRECTION INPUT ;
    USE SIGNAL ;
    PORT
      LAYER M4 ;
        RECT  59.316 29.52 59.4 29.544 ;
    END
  END wq1[4]
  PIN wq1[50]
    DIRECTION INPUT ;
    USE SIGNAL ;
    PORT
      LAYER M4 ;
        RECT  59.316 21.648 59.4 21.672 ;
    END
  END wq1[50]
  PIN wq1[51]
    DIRECTION INPUT ;
    USE SIGNAL ;
    PORT
      LAYER M4 ;
        RECT  59.316 21.744 59.4 21.768 ;
    END
  END wq1[51]
  PIN wq1[52]
    DIRECTION INPUT ;
    USE SIGNAL ;
    PORT
      LAYER M4 ;
        RECT  59.316 21.84 59.4 21.864 ;
    END
  END wq1[52]
  PIN wq1[53]
    DIRECTION INPUT ;
    USE SIGNAL ;
    PORT
      LAYER M4 ;
        RECT  59.316 21.936 59.4 21.96 ;
    END
  END wq1[53]
  PIN wq1[54]
    DIRECTION INPUT ;
    USE SIGNAL ;
    PORT
      LAYER M4 ;
        RECT  59.316 22.032 59.4 22.056 ;
    END
  END wq1[54]
  PIN wq1[55]
    DIRECTION INPUT ;
    USE SIGNAL ;
    PORT
      LAYER M4 ;
        RECT  59.316 22.128 59.4 22.152 ;
    END
  END wq1[55]
  PIN wq1[56]
    DIRECTION INPUT ;
    USE SIGNAL ;
    PORT
      LAYER M4 ;
        RECT  59.316 22.224 59.4 22.248 ;
    END
  END wq1[56]
  PIN wq1[57]
    DIRECTION INPUT ;
    USE SIGNAL ;
    PORT
      LAYER M4 ;
        RECT  59.316 22.32 59.4 22.344 ;
    END
  END wq1[57]
  PIN wq1[58]
    DIRECTION INPUT ;
    USE SIGNAL ;
    PORT
      LAYER M4 ;
        RECT  59.316 22.416 59.4 22.44 ;
    END
  END wq1[58]
  PIN wq1[59]
    DIRECTION INPUT ;
    USE SIGNAL ;
    PORT
      LAYER M4 ;
        RECT  59.316 22.512 59.4 22.536 ;
    END
  END wq1[59]
  PIN wq1[5]
    DIRECTION INPUT ;
    USE SIGNAL ;
    PORT
      LAYER M4 ;
        RECT  59.316 29.616 59.4 29.64 ;
    END
  END wq1[5]
  PIN wq1[60]
    DIRECTION INPUT ;
    USE SIGNAL ;
    PORT
      LAYER M4 ;
        RECT  59.316 22.608 59.4 22.632 ;
    END
  END wq1[60]
  PIN wq1[61]
    DIRECTION INPUT ;
    USE SIGNAL ;
    PORT
      LAYER M4 ;
        RECT  59.316 22.704 59.4 22.728 ;
    END
  END wq1[61]
  PIN wq1[62]
    DIRECTION INPUT ;
    USE SIGNAL ;
    PORT
      LAYER M4 ;
        RECT  59.316 22.8 59.4 22.824 ;
    END
  END wq1[62]
  PIN wq1[63]
    DIRECTION INPUT ;
    USE SIGNAL ;
    PORT
      LAYER M4 ;
        RECT  59.316 22.896 59.4 22.92 ;
    END
  END wq1[63]
  PIN wq1[64]
    DIRECTION INPUT ;
    USE SIGNAL ;
    PORT
      LAYER M4 ;
        RECT  59.316 22.992 59.4 23.016 ;
    END
  END wq1[64]
  PIN wq1[65]
    DIRECTION INPUT ;
    USE SIGNAL ;
    PORT
      LAYER M4 ;
        RECT  59.316 23.088 59.4 23.112 ;
    END
  END wq1[65]
  PIN wq1[66]
    DIRECTION INPUT ;
    USE SIGNAL ;
    PORT
      LAYER M4 ;
        RECT  59.316 23.184 59.4 23.208 ;
    END
  END wq1[66]
  PIN wq1[67]
    DIRECTION INPUT ;
    USE SIGNAL ;
    PORT
      LAYER M4 ;
        RECT  59.316 23.28 59.4 23.304 ;
    END
  END wq1[67]
  PIN wq1[68]
    DIRECTION INPUT ;
    USE SIGNAL ;
    PORT
      LAYER M4 ;
        RECT  59.316 23.376 59.4 23.4 ;
    END
  END wq1[68]
  PIN wq1[69]
    DIRECTION INPUT ;
    USE SIGNAL ;
    PORT
      LAYER M4 ;
        RECT  59.316 23.472 59.4 23.496 ;
    END
  END wq1[69]
  PIN wq1[6]
    DIRECTION INPUT ;
    USE SIGNAL ;
    PORT
      LAYER M4 ;
        RECT  59.316 29.712 59.4 29.736 ;
    END
  END wq1[6]
  PIN wq1[70]
    DIRECTION INPUT ;
    USE SIGNAL ;
    PORT
      LAYER M4 ;
        RECT  59.316 23.568 59.4 23.592 ;
    END
  END wq1[70]
  PIN wq1[71]
    DIRECTION INPUT ;
    USE SIGNAL ;
    PORT
      LAYER M4 ;
        RECT  59.316 23.664 59.4 23.688 ;
    END
  END wq1[71]
  PIN wq1[72]
    DIRECTION INPUT ;
    USE SIGNAL ;
    PORT
      LAYER M4 ;
        RECT  59.316 23.76 59.4 23.784 ;
    END
  END wq1[72]
  PIN wq1[73]
    DIRECTION INPUT ;
    USE SIGNAL ;
    PORT
      LAYER M4 ;
        RECT  59.316 23.856 59.4 23.88 ;
    END
  END wq1[73]
  PIN wq1[74]
    DIRECTION INPUT ;
    USE SIGNAL ;
    PORT
      LAYER M4 ;
        RECT  59.316 23.952 59.4 23.976 ;
    END
  END wq1[74]
  PIN wq1[75]
    DIRECTION INPUT ;
    USE SIGNAL ;
    PORT
      LAYER M4 ;
        RECT  59.316 24.048 59.4 24.072 ;
    END
  END wq1[75]
  PIN wq1[76]
    DIRECTION INPUT ;
    USE SIGNAL ;
    PORT
      LAYER M4 ;
        RECT  59.316 24.144 59.4 24.168 ;
    END
  END wq1[76]
  PIN wq1[77]
    DIRECTION INPUT ;
    USE SIGNAL ;
    PORT
      LAYER M4 ;
        RECT  59.316 24.24 59.4 24.264 ;
    END
  END wq1[77]
  PIN wq1[78]
    DIRECTION INPUT ;
    USE SIGNAL ;
    PORT
      LAYER M4 ;
        RECT  59.316 24.336 59.4 24.36 ;
    END
  END wq1[78]
  PIN wq1[79]
    DIRECTION INPUT ;
    USE SIGNAL ;
    PORT
      LAYER M4 ;
        RECT  59.316 24.432 59.4 24.456 ;
    END
  END wq1[79]
  PIN wq1[7]
    DIRECTION INPUT ;
    USE SIGNAL ;
    PORT
      LAYER M4 ;
        RECT  59.316 29.808 59.4 29.832 ;
    END
  END wq1[7]
  PIN wq1[80]
    DIRECTION INPUT ;
    USE SIGNAL ;
    PORT
      LAYER M4 ;
        RECT  59.316 24.528 59.4 24.552 ;
    END
  END wq1[80]
  PIN wq1[81]
    DIRECTION INPUT ;
    USE SIGNAL ;
    PORT
      LAYER M4 ;
        RECT  59.316 24.624 59.4 24.648 ;
    END
  END wq1[81]
  PIN wq1[82]
    DIRECTION INPUT ;
    USE SIGNAL ;
    PORT
      LAYER M4 ;
        RECT  59.316 24.72 59.4 24.744 ;
    END
  END wq1[82]
  PIN wq1[83]
    DIRECTION INPUT ;
    USE SIGNAL ;
    PORT
      LAYER M4 ;
        RECT  59.316 24.816 59.4 24.84 ;
    END
  END wq1[83]
  PIN wq1[84]
    DIRECTION INPUT ;
    USE SIGNAL ;
    PORT
      LAYER M4 ;
        RECT  59.316 24.912 59.4 24.936 ;
    END
  END wq1[84]
  PIN wq1[85]
    DIRECTION INPUT ;
    USE SIGNAL ;
    PORT
      LAYER M4 ;
        RECT  59.316 25.008 59.4 25.032 ;
    END
  END wq1[85]
  PIN wq1[86]
    DIRECTION INPUT ;
    USE SIGNAL ;
    PORT
      LAYER M4 ;
        RECT  59.316 25.104 59.4 25.128 ;
    END
  END wq1[86]
  PIN wq1[87]
    DIRECTION INPUT ;
    USE SIGNAL ;
    PORT
      LAYER M4 ;
        RECT  59.316 25.2 59.4 25.224 ;
    END
  END wq1[87]
  PIN wq1[88]
    DIRECTION INPUT ;
    USE SIGNAL ;
    PORT
      LAYER M4 ;
        RECT  59.316 25.296 59.4 25.32 ;
    END
  END wq1[88]
  PIN wq1[89]
    DIRECTION INPUT ;
    USE SIGNAL ;
    PORT
      LAYER M4 ;
        RECT  59.316 25.392 59.4 25.416 ;
    END
  END wq1[89]
  PIN wq1[8]
    DIRECTION INPUT ;
    USE SIGNAL ;
    PORT
      LAYER M4 ;
        RECT  59.316 29.904 59.4 29.928 ;
    END
  END wq1[8]
  PIN wq1[90]
    DIRECTION INPUT ;
    USE SIGNAL ;
    PORT
      LAYER M4 ;
        RECT  59.316 25.488 59.4 25.512 ;
    END
  END wq1[90]
  PIN wq1[91]
    DIRECTION INPUT ;
    USE SIGNAL ;
    PORT
      LAYER M4 ;
        RECT  59.316 25.584 59.4 25.608 ;
    END
  END wq1[91]
  PIN wq1[92]
    DIRECTION INPUT ;
    USE SIGNAL ;
    PORT
      LAYER M4 ;
        RECT  59.316 25.68 59.4 25.704 ;
    END
  END wq1[92]
  PIN wq1[93]
    DIRECTION INPUT ;
    USE SIGNAL ;
    PORT
      LAYER M4 ;
        RECT  59.316 25.776 59.4 25.8 ;
    END
  END wq1[93]
  PIN wq1[94]
    DIRECTION INPUT ;
    USE SIGNAL ;
    PORT
      LAYER M4 ;
        RECT  59.316 25.872 59.4 25.896 ;
    END
  END wq1[94]
  PIN wq1[95]
    DIRECTION INPUT ;
    USE SIGNAL ;
    PORT
      LAYER M4 ;
        RECT  59.316 25.968 59.4 25.992 ;
    END
  END wq1[95]
  PIN wq1[96]
    DIRECTION INPUT ;
    USE SIGNAL ;
    PORT
      LAYER M4 ;
        RECT  59.316 35.28 59.4 35.304 ;
    END
  END wq1[96]
  PIN wq1[97]
    DIRECTION INPUT ;
    USE SIGNAL ;
    PORT
      LAYER M4 ;
        RECT  59.316 35.376 59.4 35.4 ;
    END
  END wq1[97]
  PIN wq1[98]
    DIRECTION INPUT ;
    USE SIGNAL ;
    PORT
      LAYER M4 ;
        RECT  59.316 35.472 59.4 35.496 ;
    END
  END wq1[98]
  PIN wq1[99]
    DIRECTION INPUT ;
    USE SIGNAL ;
    PORT
      LAYER M4 ;
        RECT  59.316 35.568 59.4 35.592 ;
    END
  END wq1[99]
  PIN wq1[9]
    DIRECTION INPUT ;
    USE SIGNAL ;
    PORT
      LAYER M4 ;
        RECT  59.316 30 59.4 30.024 ;
    END
  END wq1[9]
  PIN wq2[0]
    DIRECTION INPUT ;
    USE SIGNAL ;
    PORT
      LAYER M5 ;
        RECT  14.16 59.316 14.184 59.4 ;
    END
  END wq2[0]
  PIN wq2[100]
    DIRECTION INPUT ;
    USE SIGNAL ;
    PORT
      LAYER M5 ;
        RECT  36.816 59.316 36.84 59.4 ;
    END
  END wq2[100]
  PIN wq2[101]
    DIRECTION INPUT ;
    USE SIGNAL ;
    PORT
      LAYER M5 ;
        RECT  36.912 59.316 36.936 59.4 ;
    END
  END wq2[101]
  PIN wq2[102]
    DIRECTION INPUT ;
    USE SIGNAL ;
    PORT
      LAYER M5 ;
        RECT  37.008 59.316 37.032 59.4 ;
    END
  END wq2[102]
  PIN wq2[103]
    DIRECTION INPUT ;
    USE SIGNAL ;
    PORT
      LAYER M5 ;
        RECT  37.104 59.316 37.128 59.4 ;
    END
  END wq2[103]
  PIN wq2[104]
    DIRECTION INPUT ;
    USE SIGNAL ;
    PORT
      LAYER M5 ;
        RECT  37.2 59.316 37.224 59.4 ;
    END
  END wq2[104]
  PIN wq2[105]
    DIRECTION INPUT ;
    USE SIGNAL ;
    PORT
      LAYER M5 ;
        RECT  37.296 59.316 37.32 59.4 ;
    END
  END wq2[105]
  PIN wq2[106]
    DIRECTION INPUT ;
    USE SIGNAL ;
    PORT
      LAYER M5 ;
        RECT  37.392 59.316 37.416 59.4 ;
    END
  END wq2[106]
  PIN wq2[107]
    DIRECTION INPUT ;
    USE SIGNAL ;
    PORT
      LAYER M5 ;
        RECT  37.488 59.316 37.512 59.4 ;
    END
  END wq2[107]
  PIN wq2[108]
    DIRECTION INPUT ;
    USE SIGNAL ;
    PORT
      LAYER M5 ;
        RECT  37.584 59.316 37.608 59.4 ;
    END
  END wq2[108]
  PIN wq2[109]
    DIRECTION INPUT ;
    USE SIGNAL ;
    PORT
      LAYER M5 ;
        RECT  37.68 59.316 37.704 59.4 ;
    END
  END wq2[109]
  PIN wq2[10]
    DIRECTION INPUT ;
    USE SIGNAL ;
    PORT
      LAYER M5 ;
        RECT  15.12 59.316 15.144 59.4 ;
    END
  END wq2[10]
  PIN wq2[110]
    DIRECTION INPUT ;
    USE SIGNAL ;
    PORT
      LAYER M5 ;
        RECT  37.776 59.316 37.8 59.4 ;
    END
  END wq2[110]
  PIN wq2[111]
    DIRECTION INPUT ;
    USE SIGNAL ;
    PORT
      LAYER M5 ;
        RECT  37.872 59.316 37.896 59.4 ;
    END
  END wq2[111]
  PIN wq2[112]
    DIRECTION INPUT ;
    USE SIGNAL ;
    PORT
      LAYER M5 ;
        RECT  37.968 59.316 37.992 59.4 ;
    END
  END wq2[112]
  PIN wq2[113]
    DIRECTION INPUT ;
    USE SIGNAL ;
    PORT
      LAYER M5 ;
        RECT  38.064 59.316 38.088 59.4 ;
    END
  END wq2[113]
  PIN wq2[114]
    DIRECTION INPUT ;
    USE SIGNAL ;
    PORT
      LAYER M5 ;
        RECT  38.16 59.316 38.184 59.4 ;
    END
  END wq2[114]
  PIN wq2[115]
    DIRECTION INPUT ;
    USE SIGNAL ;
    PORT
      LAYER M5 ;
        RECT  38.256 59.316 38.28 59.4 ;
    END
  END wq2[115]
  PIN wq2[116]
    DIRECTION INPUT ;
    USE SIGNAL ;
    PORT
      LAYER M5 ;
        RECT  38.352 59.316 38.376 59.4 ;
    END
  END wq2[116]
  PIN wq2[117]
    DIRECTION INPUT ;
    USE SIGNAL ;
    PORT
      LAYER M5 ;
        RECT  38.448 59.316 38.472 59.4 ;
    END
  END wq2[117]
  PIN wq2[118]
    DIRECTION INPUT ;
    USE SIGNAL ;
    PORT
      LAYER M5 ;
        RECT  38.544 59.316 38.568 59.4 ;
    END
  END wq2[118]
  PIN wq2[119]
    DIRECTION INPUT ;
    USE SIGNAL ;
    PORT
      LAYER M5 ;
        RECT  38.64 59.316 38.664 59.4 ;
    END
  END wq2[119]
  PIN wq2[11]
    DIRECTION INPUT ;
    USE SIGNAL ;
    PORT
      LAYER M5 ;
        RECT  15.216 59.316 15.24 59.4 ;
    END
  END wq2[11]
  PIN wq2[120]
    DIRECTION INPUT ;
    USE SIGNAL ;
    PORT
      LAYER M5 ;
        RECT  38.736 59.316 38.76 59.4 ;
    END
  END wq2[120]
  PIN wq2[121]
    DIRECTION INPUT ;
    USE SIGNAL ;
    PORT
      LAYER M5 ;
        RECT  38.832 59.316 38.856 59.4 ;
    END
  END wq2[121]
  PIN wq2[122]
    DIRECTION INPUT ;
    USE SIGNAL ;
    PORT
      LAYER M5 ;
        RECT  38.928 59.316 38.952 59.4 ;
    END
  END wq2[122]
  PIN wq2[123]
    DIRECTION INPUT ;
    USE SIGNAL ;
    PORT
      LAYER M5 ;
        RECT  39.024 59.316 39.048 59.4 ;
    END
  END wq2[123]
  PIN wq2[124]
    DIRECTION INPUT ;
    USE SIGNAL ;
    PORT
      LAYER M5 ;
        RECT  39.12 59.316 39.144 59.4 ;
    END
  END wq2[124]
  PIN wq2[125]
    DIRECTION INPUT ;
    USE SIGNAL ;
    PORT
      LAYER M5 ;
        RECT  39.216 59.316 39.24 59.4 ;
    END
  END wq2[125]
  PIN wq2[126]
    DIRECTION INPUT ;
    USE SIGNAL ;
    PORT
      LAYER M5 ;
        RECT  39.312 59.316 39.336 59.4 ;
    END
  END wq2[126]
  PIN wq2[127]
    DIRECTION INPUT ;
    USE SIGNAL ;
    PORT
      LAYER M5 ;
        RECT  39.408 59.316 39.432 59.4 ;
    END
  END wq2[127]
  PIN wq2[128]
    DIRECTION INPUT ;
    USE SIGNAL ;
    PORT
      LAYER M5 ;
        RECT  40.272 59.316 40.296 59.4 ;
    END
  END wq2[128]
  PIN wq2[129]
    DIRECTION INPUT ;
    USE SIGNAL ;
    PORT
      LAYER M5 ;
        RECT  40.368 59.316 40.392 59.4 ;
    END
  END wq2[129]
  PIN wq2[12]
    DIRECTION INPUT ;
    USE SIGNAL ;
    PORT
      LAYER M5 ;
        RECT  15.312 59.316 15.336 59.4 ;
    END
  END wq2[12]
  PIN wq2[130]
    DIRECTION INPUT ;
    USE SIGNAL ;
    PORT
      LAYER M5 ;
        RECT  40.464 59.316 40.488 59.4 ;
    END
  END wq2[130]
  PIN wq2[131]
    DIRECTION INPUT ;
    USE SIGNAL ;
    PORT
      LAYER M5 ;
        RECT  40.56 59.316 40.584 59.4 ;
    END
  END wq2[131]
  PIN wq2[132]
    DIRECTION INPUT ;
    USE SIGNAL ;
    PORT
      LAYER M5 ;
        RECT  40.656 59.316 40.68 59.4 ;
    END
  END wq2[132]
  PIN wq2[133]
    DIRECTION INPUT ;
    USE SIGNAL ;
    PORT
      LAYER M5 ;
        RECT  40.752 59.316 40.776 59.4 ;
    END
  END wq2[133]
  PIN wq2[134]
    DIRECTION INPUT ;
    USE SIGNAL ;
    PORT
      LAYER M5 ;
        RECT  40.848 59.316 40.872 59.4 ;
    END
  END wq2[134]
  PIN wq2[135]
    DIRECTION INPUT ;
    USE SIGNAL ;
    PORT
      LAYER M5 ;
        RECT  40.944 59.316 40.968 59.4 ;
    END
  END wq2[135]
  PIN wq2[136]
    DIRECTION INPUT ;
    USE SIGNAL ;
    PORT
      LAYER M5 ;
        RECT  41.04 59.316 41.064 59.4 ;
    END
  END wq2[136]
  PIN wq2[137]
    DIRECTION INPUT ;
    USE SIGNAL ;
    PORT
      LAYER M5 ;
        RECT  41.136 59.316 41.16 59.4 ;
    END
  END wq2[137]
  PIN wq2[138]
    DIRECTION INPUT ;
    USE SIGNAL ;
    PORT
      LAYER M5 ;
        RECT  41.232 59.316 41.256 59.4 ;
    END
  END wq2[138]
  PIN wq2[139]
    DIRECTION INPUT ;
    USE SIGNAL ;
    PORT
      LAYER M5 ;
        RECT  41.328 59.316 41.352 59.4 ;
    END
  END wq2[139]
  PIN wq2[13]
    DIRECTION INPUT ;
    USE SIGNAL ;
    PORT
      LAYER M5 ;
        RECT  15.408 59.316 15.432 59.4 ;
    END
  END wq2[13]
  PIN wq2[140]
    DIRECTION INPUT ;
    USE SIGNAL ;
    PORT
      LAYER M5 ;
        RECT  41.424 59.316 41.448 59.4 ;
    END
  END wq2[140]
  PIN wq2[141]
    DIRECTION INPUT ;
    USE SIGNAL ;
    PORT
      LAYER M5 ;
        RECT  41.52 59.316 41.544 59.4 ;
    END
  END wq2[141]
  PIN wq2[142]
    DIRECTION INPUT ;
    USE SIGNAL ;
    PORT
      LAYER M5 ;
        RECT  41.616 59.316 41.64 59.4 ;
    END
  END wq2[142]
  PIN wq2[143]
    DIRECTION INPUT ;
    USE SIGNAL ;
    PORT
      LAYER M5 ;
        RECT  41.712 59.316 41.736 59.4 ;
    END
  END wq2[143]
  PIN wq2[144]
    DIRECTION INPUT ;
    USE SIGNAL ;
    PORT
      LAYER M5 ;
        RECT  41.808 59.316 41.832 59.4 ;
    END
  END wq2[144]
  PIN wq2[145]
    DIRECTION INPUT ;
    USE SIGNAL ;
    PORT
      LAYER M5 ;
        RECT  41.904 59.316 41.928 59.4 ;
    END
  END wq2[145]
  PIN wq2[146]
    DIRECTION INPUT ;
    USE SIGNAL ;
    PORT
      LAYER M5 ;
        RECT  42 59.316 42.024 59.4 ;
    END
  END wq2[146]
  PIN wq2[147]
    DIRECTION INPUT ;
    USE SIGNAL ;
    PORT
      LAYER M5 ;
        RECT  42.096 59.316 42.12 59.4 ;
    END
  END wq2[147]
  PIN wq2[148]
    DIRECTION INPUT ;
    USE SIGNAL ;
    PORT
      LAYER M5 ;
        RECT  42.192 59.316 42.216 59.4 ;
    END
  END wq2[148]
  PIN wq2[149]
    DIRECTION INPUT ;
    USE SIGNAL ;
    PORT
      LAYER M5 ;
        RECT  42.288 59.316 42.312 59.4 ;
    END
  END wq2[149]
  PIN wq2[14]
    DIRECTION INPUT ;
    USE SIGNAL ;
    PORT
      LAYER M5 ;
        RECT  15.504 59.316 15.528 59.4 ;
    END
  END wq2[14]
  PIN wq2[150]
    DIRECTION INPUT ;
    USE SIGNAL ;
    PORT
      LAYER M5 ;
        RECT  42.384 59.316 42.408 59.4 ;
    END
  END wq2[150]
  PIN wq2[151]
    DIRECTION INPUT ;
    USE SIGNAL ;
    PORT
      LAYER M5 ;
        RECT  42.48 59.316 42.504 59.4 ;
    END
  END wq2[151]
  PIN wq2[152]
    DIRECTION INPUT ;
    USE SIGNAL ;
    PORT
      LAYER M5 ;
        RECT  42.576 59.316 42.6 59.4 ;
    END
  END wq2[152]
  PIN wq2[153]
    DIRECTION INPUT ;
    USE SIGNAL ;
    PORT
      LAYER M5 ;
        RECT  42.672 59.316 42.696 59.4 ;
    END
  END wq2[153]
  PIN wq2[154]
    DIRECTION INPUT ;
    USE SIGNAL ;
    PORT
      LAYER M5 ;
        RECT  42.768 59.316 42.792 59.4 ;
    END
  END wq2[154]
  PIN wq2[155]
    DIRECTION INPUT ;
    USE SIGNAL ;
    PORT
      LAYER M5 ;
        RECT  42.864 59.316 42.888 59.4 ;
    END
  END wq2[155]
  PIN wq2[156]
    DIRECTION INPUT ;
    USE SIGNAL ;
    PORT
      LAYER M5 ;
        RECT  42.96 59.316 42.984 59.4 ;
    END
  END wq2[156]
  PIN wq2[157]
    DIRECTION INPUT ;
    USE SIGNAL ;
    PORT
      LAYER M5 ;
        RECT  43.056 59.316 43.08 59.4 ;
    END
  END wq2[157]
  PIN wq2[158]
    DIRECTION INPUT ;
    USE SIGNAL ;
    PORT
      LAYER M5 ;
        RECT  43.152 59.316 43.176 59.4 ;
    END
  END wq2[158]
  PIN wq2[159]
    DIRECTION INPUT ;
    USE SIGNAL ;
    PORT
      LAYER M5 ;
        RECT  43.248 59.316 43.272 59.4 ;
    END
  END wq2[159]
  PIN wq2[15]
    DIRECTION INPUT ;
    USE SIGNAL ;
    PORT
      LAYER M5 ;
        RECT  15.6 59.316 15.624 59.4 ;
    END
  END wq2[15]
  PIN wq2[160]
    DIRECTION INPUT ;
    USE SIGNAL ;
    PORT
      LAYER M5 ;
        RECT  33.36 59.316 33.384 59.4 ;
    END
  END wq2[160]
  PIN wq2[161]
    DIRECTION INPUT ;
    USE SIGNAL ;
    PORT
      LAYER M5 ;
        RECT  33.456 59.316 33.48 59.4 ;
    END
  END wq2[161]
  PIN wq2[162]
    DIRECTION INPUT ;
    USE SIGNAL ;
    PORT
      LAYER M5 ;
        RECT  33.552 59.316 33.576 59.4 ;
    END
  END wq2[162]
  PIN wq2[163]
    DIRECTION INPUT ;
    USE SIGNAL ;
    PORT
      LAYER M5 ;
        RECT  33.648 59.316 33.672 59.4 ;
    END
  END wq2[163]
  PIN wq2[164]
    DIRECTION INPUT ;
    USE SIGNAL ;
    PORT
      LAYER M5 ;
        RECT  33.744 59.316 33.768 59.4 ;
    END
  END wq2[164]
  PIN wq2[165]
    DIRECTION INPUT ;
    USE SIGNAL ;
    PORT
      LAYER M5 ;
        RECT  33.84 59.316 33.864 59.4 ;
    END
  END wq2[165]
  PIN wq2[166]
    DIRECTION INPUT ;
    USE SIGNAL ;
    PORT
      LAYER M5 ;
        RECT  33.936 59.316 33.96 59.4 ;
    END
  END wq2[166]
  PIN wq2[167]
    DIRECTION INPUT ;
    USE SIGNAL ;
    PORT
      LAYER M5 ;
        RECT  34.032 59.316 34.056 59.4 ;
    END
  END wq2[167]
  PIN wq2[168]
    DIRECTION INPUT ;
    USE SIGNAL ;
    PORT
      LAYER M5 ;
        RECT  34.128 59.316 34.152 59.4 ;
    END
  END wq2[168]
  PIN wq2[169]
    DIRECTION INPUT ;
    USE SIGNAL ;
    PORT
      LAYER M5 ;
        RECT  34.224 59.316 34.248 59.4 ;
    END
  END wq2[169]
  PIN wq2[16]
    DIRECTION INPUT ;
    USE SIGNAL ;
    PORT
      LAYER M5 ;
        RECT  15.696 59.316 15.72 59.4 ;
    END
  END wq2[16]
  PIN wq2[170]
    DIRECTION INPUT ;
    USE SIGNAL ;
    PORT
      LAYER M5 ;
        RECT  34.32 59.316 34.344 59.4 ;
    END
  END wq2[170]
  PIN wq2[171]
    DIRECTION INPUT ;
    USE SIGNAL ;
    PORT
      LAYER M5 ;
        RECT  34.416 59.316 34.44 59.4 ;
    END
  END wq2[171]
  PIN wq2[172]
    DIRECTION INPUT ;
    USE SIGNAL ;
    PORT
      LAYER M5 ;
        RECT  34.512 59.316 34.536 59.4 ;
    END
  END wq2[172]
  PIN wq2[173]
    DIRECTION INPUT ;
    USE SIGNAL ;
    PORT
      LAYER M5 ;
        RECT  34.608 59.316 34.632 59.4 ;
    END
  END wq2[173]
  PIN wq2[174]
    DIRECTION INPUT ;
    USE SIGNAL ;
    PORT
      LAYER M5 ;
        RECT  34.704 59.316 34.728 59.4 ;
    END
  END wq2[174]
  PIN wq2[175]
    DIRECTION INPUT ;
    USE SIGNAL ;
    PORT
      LAYER M5 ;
        RECT  34.8 59.316 34.824 59.4 ;
    END
  END wq2[175]
  PIN wq2[176]
    DIRECTION INPUT ;
    USE SIGNAL ;
    PORT
      LAYER M5 ;
        RECT  34.896 59.316 34.92 59.4 ;
    END
  END wq2[176]
  PIN wq2[177]
    DIRECTION INPUT ;
    USE SIGNAL ;
    PORT
      LAYER M5 ;
        RECT  34.992 59.316 35.016 59.4 ;
    END
  END wq2[177]
  PIN wq2[178]
    DIRECTION INPUT ;
    USE SIGNAL ;
    PORT
      LAYER M5 ;
        RECT  35.088 59.316 35.112 59.4 ;
    END
  END wq2[178]
  PIN wq2[179]
    DIRECTION INPUT ;
    USE SIGNAL ;
    PORT
      LAYER M5 ;
        RECT  35.184 59.316 35.208 59.4 ;
    END
  END wq2[179]
  PIN wq2[17]
    DIRECTION INPUT ;
    USE SIGNAL ;
    PORT
      LAYER M5 ;
        RECT  15.792 59.316 15.816 59.4 ;
    END
  END wq2[17]
  PIN wq2[180]
    DIRECTION INPUT ;
    USE SIGNAL ;
    PORT
      LAYER M5 ;
        RECT  35.28 59.316 35.304 59.4 ;
    END
  END wq2[180]
  PIN wq2[181]
    DIRECTION INPUT ;
    USE SIGNAL ;
    PORT
      LAYER M5 ;
        RECT  35.376 59.316 35.4 59.4 ;
    END
  END wq2[181]
  PIN wq2[182]
    DIRECTION INPUT ;
    USE SIGNAL ;
    PORT
      LAYER M5 ;
        RECT  35.472 59.316 35.496 59.4 ;
    END
  END wq2[182]
  PIN wq2[183]
    DIRECTION INPUT ;
    USE SIGNAL ;
    PORT
      LAYER M5 ;
        RECT  35.568 59.316 35.592 59.4 ;
    END
  END wq2[183]
  PIN wq2[184]
    DIRECTION INPUT ;
    USE SIGNAL ;
    PORT
      LAYER M5 ;
        RECT  35.664 59.316 35.688 59.4 ;
    END
  END wq2[184]
  PIN wq2[185]
    DIRECTION INPUT ;
    USE SIGNAL ;
    PORT
      LAYER M5 ;
        RECT  35.76 59.316 35.784 59.4 ;
    END
  END wq2[185]
  PIN wq2[186]
    DIRECTION INPUT ;
    USE SIGNAL ;
    PORT
      LAYER M5 ;
        RECT  35.856 59.316 35.88 59.4 ;
    END
  END wq2[186]
  PIN wq2[187]
    DIRECTION INPUT ;
    USE SIGNAL ;
    PORT
      LAYER M5 ;
        RECT  35.952 59.316 35.976 59.4 ;
    END
  END wq2[187]
  PIN wq2[188]
    DIRECTION INPUT ;
    USE SIGNAL ;
    PORT
      LAYER M5 ;
        RECT  36.048 59.316 36.072 59.4 ;
    END
  END wq2[188]
  PIN wq2[189]
    DIRECTION INPUT ;
    USE SIGNAL ;
    PORT
      LAYER M5 ;
        RECT  36.144 59.316 36.168 59.4 ;
    END
  END wq2[189]
  PIN wq2[18]
    DIRECTION INPUT ;
    USE SIGNAL ;
    PORT
      LAYER M5 ;
        RECT  15.888 59.316 15.912 59.4 ;
    END
  END wq2[18]
  PIN wq2[190]
    DIRECTION INPUT ;
    USE SIGNAL ;
    PORT
      LAYER M5 ;
        RECT  36.24 59.316 36.264 59.4 ;
    END
  END wq2[190]
  PIN wq2[191]
    DIRECTION INPUT ;
    USE SIGNAL ;
    PORT
      LAYER M5 ;
        RECT  36.336 59.316 36.36 59.4 ;
    END
  END wq2[191]
  PIN wq2[192]
    DIRECTION INPUT ;
    USE SIGNAL ;
    PORT
      LAYER M5 ;
        RECT  30.288 59.316 30.312 59.4 ;
    END
  END wq2[192]
  PIN wq2[193]
    DIRECTION INPUT ;
    USE SIGNAL ;
    PORT
      LAYER M5 ;
        RECT  30.384 59.316 30.408 59.4 ;
    END
  END wq2[193]
  PIN wq2[194]
    DIRECTION INPUT ;
    USE SIGNAL ;
    PORT
      LAYER M5 ;
        RECT  30.48 59.316 30.504 59.4 ;
    END
  END wq2[194]
  PIN wq2[195]
    DIRECTION INPUT ;
    USE SIGNAL ;
    PORT
      LAYER M5 ;
        RECT  30.576 59.316 30.6 59.4 ;
    END
  END wq2[195]
  PIN wq2[196]
    DIRECTION INPUT ;
    USE SIGNAL ;
    PORT
      LAYER M5 ;
        RECT  30.672 59.316 30.696 59.4 ;
    END
  END wq2[196]
  PIN wq2[197]
    DIRECTION INPUT ;
    USE SIGNAL ;
    PORT
      LAYER M5 ;
        RECT  30.768 59.316 30.792 59.4 ;
    END
  END wq2[197]
  PIN wq2[198]
    DIRECTION INPUT ;
    USE SIGNAL ;
    PORT
      LAYER M5 ;
        RECT  30.864 59.316 30.888 59.4 ;
    END
  END wq2[198]
  PIN wq2[199]
    DIRECTION INPUT ;
    USE SIGNAL ;
    PORT
      LAYER M5 ;
        RECT  30.96 59.316 30.984 59.4 ;
    END
  END wq2[199]
  PIN wq2[19]
    DIRECTION INPUT ;
    USE SIGNAL ;
    PORT
      LAYER M5 ;
        RECT  15.984 59.316 16.008 59.4 ;
    END
  END wq2[19]
  PIN wq2[1]
    DIRECTION INPUT ;
    USE SIGNAL ;
    PORT
      LAYER M5 ;
        RECT  14.256 59.316 14.28 59.4 ;
    END
  END wq2[1]
  PIN wq2[200]
    DIRECTION INPUT ;
    USE SIGNAL ;
    PORT
      LAYER M5 ;
        RECT  31.056 59.316 31.08 59.4 ;
    END
  END wq2[200]
  PIN wq2[201]
    DIRECTION INPUT ;
    USE SIGNAL ;
    PORT
      LAYER M5 ;
        RECT  31.152 59.316 31.176 59.4 ;
    END
  END wq2[201]
  PIN wq2[202]
    DIRECTION INPUT ;
    USE SIGNAL ;
    PORT
      LAYER M5 ;
        RECT  31.248 59.316 31.272 59.4 ;
    END
  END wq2[202]
  PIN wq2[203]
    DIRECTION INPUT ;
    USE SIGNAL ;
    PORT
      LAYER M5 ;
        RECT  31.344 59.316 31.368 59.4 ;
    END
  END wq2[203]
  PIN wq2[204]
    DIRECTION INPUT ;
    USE SIGNAL ;
    PORT
      LAYER M5 ;
        RECT  31.44 59.316 31.464 59.4 ;
    END
  END wq2[204]
  PIN wq2[205]
    DIRECTION INPUT ;
    USE SIGNAL ;
    PORT
      LAYER M5 ;
        RECT  31.536 59.316 31.56 59.4 ;
    END
  END wq2[205]
  PIN wq2[206]
    DIRECTION INPUT ;
    USE SIGNAL ;
    PORT
      LAYER M5 ;
        RECT  31.632 59.316 31.656 59.4 ;
    END
  END wq2[206]
  PIN wq2[207]
    DIRECTION INPUT ;
    USE SIGNAL ;
    PORT
      LAYER M5 ;
        RECT  31.728 59.316 31.752 59.4 ;
    END
  END wq2[207]
  PIN wq2[208]
    DIRECTION INPUT ;
    USE SIGNAL ;
    PORT
      LAYER M5 ;
        RECT  31.824 59.316 31.848 59.4 ;
    END
  END wq2[208]
  PIN wq2[209]
    DIRECTION INPUT ;
    USE SIGNAL ;
    PORT
      LAYER M5 ;
        RECT  31.92 59.316 31.944 59.4 ;
    END
  END wq2[209]
  PIN wq2[20]
    DIRECTION INPUT ;
    USE SIGNAL ;
    PORT
      LAYER M5 ;
        RECT  16.08 59.316 16.104 59.4 ;
    END
  END wq2[20]
  PIN wq2[210]
    DIRECTION INPUT ;
    USE SIGNAL ;
    PORT
      LAYER M5 ;
        RECT  32.016 59.316 32.04 59.4 ;
    END
  END wq2[210]
  PIN wq2[211]
    DIRECTION INPUT ;
    USE SIGNAL ;
    PORT
      LAYER M5 ;
        RECT  32.112 59.316 32.136 59.4 ;
    END
  END wq2[211]
  PIN wq2[212]
    DIRECTION INPUT ;
    USE SIGNAL ;
    PORT
      LAYER M5 ;
        RECT  32.208 59.316 32.232 59.4 ;
    END
  END wq2[212]
  PIN wq2[213]
    DIRECTION INPUT ;
    USE SIGNAL ;
    PORT
      LAYER M5 ;
        RECT  32.304 59.316 32.328 59.4 ;
    END
  END wq2[213]
  PIN wq2[214]
    DIRECTION INPUT ;
    USE SIGNAL ;
    PORT
      LAYER M5 ;
        RECT  32.4 59.316 32.424 59.4 ;
    END
  END wq2[214]
  PIN wq2[215]
    DIRECTION INPUT ;
    USE SIGNAL ;
    PORT
      LAYER M5 ;
        RECT  32.496 59.316 32.52 59.4 ;
    END
  END wq2[215]
  PIN wq2[216]
    DIRECTION INPUT ;
    USE SIGNAL ;
    PORT
      LAYER M5 ;
        RECT  32.592 59.316 32.616 59.4 ;
    END
  END wq2[216]
  PIN wq2[217]
    DIRECTION INPUT ;
    USE SIGNAL ;
    PORT
      LAYER M5 ;
        RECT  32.688 59.316 32.712 59.4 ;
    END
  END wq2[217]
  PIN wq2[218]
    DIRECTION INPUT ;
    USE SIGNAL ;
    PORT
      LAYER M5 ;
        RECT  32.784 59.316 32.808 59.4 ;
    END
  END wq2[218]
  PIN wq2[219]
    DIRECTION INPUT ;
    USE SIGNAL ;
    PORT
      LAYER M5 ;
        RECT  32.88 59.316 32.904 59.4 ;
    END
  END wq2[219]
  PIN wq2[21]
    DIRECTION INPUT ;
    USE SIGNAL ;
    PORT
      LAYER M5 ;
        RECT  16.176 59.316 16.2 59.4 ;
    END
  END wq2[21]
  PIN wq2[220]
    DIRECTION INPUT ;
    USE SIGNAL ;
    PORT
      LAYER M5 ;
        RECT  32.976 59.316 33 59.4 ;
    END
  END wq2[220]
  PIN wq2[221]
    DIRECTION INPUT ;
    USE SIGNAL ;
    PORT
      LAYER M5 ;
        RECT  33.072 59.316 33.096 59.4 ;
    END
  END wq2[221]
  PIN wq2[222]
    DIRECTION INPUT ;
    USE SIGNAL ;
    PORT
      LAYER M5 ;
        RECT  33.168 59.316 33.192 59.4 ;
    END
  END wq2[222]
  PIN wq2[223]
    DIRECTION INPUT ;
    USE SIGNAL ;
    PORT
      LAYER M5 ;
        RECT  33.264 59.316 33.288 59.4 ;
    END
  END wq2[223]
  PIN wq2[224]
    DIRECTION INPUT ;
    USE SIGNAL ;
    PORT
      LAYER M5 ;
        RECT  24.144 59.316 24.168 59.4 ;
    END
  END wq2[224]
  PIN wq2[225]
    DIRECTION INPUT ;
    USE SIGNAL ;
    PORT
      LAYER M5 ;
        RECT  24.24 59.316 24.264 59.4 ;
    END
  END wq2[225]
  PIN wq2[226]
    DIRECTION INPUT ;
    USE SIGNAL ;
    PORT
      LAYER M5 ;
        RECT  24.336 59.316 24.36 59.4 ;
    END
  END wq2[226]
  PIN wq2[227]
    DIRECTION INPUT ;
    USE SIGNAL ;
    PORT
      LAYER M5 ;
        RECT  24.432 59.316 24.456 59.4 ;
    END
  END wq2[227]
  PIN wq2[228]
    DIRECTION INPUT ;
    USE SIGNAL ;
    PORT
      LAYER M5 ;
        RECT  24.528 59.316 24.552 59.4 ;
    END
  END wq2[228]
  PIN wq2[229]
    DIRECTION INPUT ;
    USE SIGNAL ;
    PORT
      LAYER M5 ;
        RECT  24.624 59.316 24.648 59.4 ;
    END
  END wq2[229]
  PIN wq2[22]
    DIRECTION INPUT ;
    USE SIGNAL ;
    PORT
      LAYER M5 ;
        RECT  16.272 59.316 16.296 59.4 ;
    END
  END wq2[22]
  PIN wq2[230]
    DIRECTION INPUT ;
    USE SIGNAL ;
    PORT
      LAYER M5 ;
        RECT  24.72 59.316 24.744 59.4 ;
    END
  END wq2[230]
  PIN wq2[231]
    DIRECTION INPUT ;
    USE SIGNAL ;
    PORT
      LAYER M5 ;
        RECT  24.816 59.316 24.84 59.4 ;
    END
  END wq2[231]
  PIN wq2[232]
    DIRECTION INPUT ;
    USE SIGNAL ;
    PORT
      LAYER M5 ;
        RECT  24.912 59.316 24.936 59.4 ;
    END
  END wq2[232]
  PIN wq2[233]
    DIRECTION INPUT ;
    USE SIGNAL ;
    PORT
      LAYER M5 ;
        RECT  25.008 59.316 25.032 59.4 ;
    END
  END wq2[233]
  PIN wq2[234]
    DIRECTION INPUT ;
    USE SIGNAL ;
    PORT
      LAYER M5 ;
        RECT  25.104 59.316 25.128 59.4 ;
    END
  END wq2[234]
  PIN wq2[235]
    DIRECTION INPUT ;
    USE SIGNAL ;
    PORT
      LAYER M5 ;
        RECT  25.2 59.316 25.224 59.4 ;
    END
  END wq2[235]
  PIN wq2[236]
    DIRECTION INPUT ;
    USE SIGNAL ;
    PORT
      LAYER M5 ;
        RECT  25.296 59.316 25.32 59.4 ;
    END
  END wq2[236]
  PIN wq2[237]
    DIRECTION INPUT ;
    USE SIGNAL ;
    PORT
      LAYER M5 ;
        RECT  25.392 59.316 25.416 59.4 ;
    END
  END wq2[237]
  PIN wq2[238]
    DIRECTION INPUT ;
    USE SIGNAL ;
    PORT
      LAYER M5 ;
        RECT  25.488 59.316 25.512 59.4 ;
    END
  END wq2[238]
  PIN wq2[239]
    DIRECTION INPUT ;
    USE SIGNAL ;
    PORT
      LAYER M5 ;
        RECT  25.584 59.316 25.608 59.4 ;
    END
  END wq2[239]
  PIN wq2[23]
    DIRECTION INPUT ;
    USE SIGNAL ;
    PORT
      LAYER M5 ;
        RECT  16.368 59.316 16.392 59.4 ;
    END
  END wq2[23]
  PIN wq2[240]
    DIRECTION INPUT ;
    USE SIGNAL ;
    PORT
      LAYER M5 ;
        RECT  25.68 59.316 25.704 59.4 ;
    END
  END wq2[240]
  PIN wq2[241]
    DIRECTION INPUT ;
    USE SIGNAL ;
    PORT
      LAYER M5 ;
        RECT  25.776 59.316 25.8 59.4 ;
    END
  END wq2[241]
  PIN wq2[242]
    DIRECTION INPUT ;
    USE SIGNAL ;
    PORT
      LAYER M5 ;
        RECT  25.872 59.316 25.896 59.4 ;
    END
  END wq2[242]
  PIN wq2[243]
    DIRECTION INPUT ;
    USE SIGNAL ;
    PORT
      LAYER M5 ;
        RECT  25.968 59.316 25.992 59.4 ;
    END
  END wq2[243]
  PIN wq2[244]
    DIRECTION INPUT ;
    USE SIGNAL ;
    PORT
      LAYER M5 ;
        RECT  26.064 59.316 26.088 59.4 ;
    END
  END wq2[244]
  PIN wq2[245]
    DIRECTION INPUT ;
    USE SIGNAL ;
    PORT
      LAYER M5 ;
        RECT  26.16 59.316 26.184 59.4 ;
    END
  END wq2[245]
  PIN wq2[246]
    DIRECTION INPUT ;
    USE SIGNAL ;
    PORT
      LAYER M5 ;
        RECT  26.256 59.316 26.28 59.4 ;
    END
  END wq2[246]
  PIN wq2[247]
    DIRECTION INPUT ;
    USE SIGNAL ;
    PORT
      LAYER M5 ;
        RECT  26.352 59.316 26.376 59.4 ;
    END
  END wq2[247]
  PIN wq2[248]
    DIRECTION INPUT ;
    USE SIGNAL ;
    PORT
      LAYER M5 ;
        RECT  26.448 59.316 26.472 59.4 ;
    END
  END wq2[248]
  PIN wq2[249]
    DIRECTION INPUT ;
    USE SIGNAL ;
    PORT
      LAYER M5 ;
        RECT  26.544 59.316 26.568 59.4 ;
    END
  END wq2[249]
  PIN wq2[24]
    DIRECTION INPUT ;
    USE SIGNAL ;
    PORT
      LAYER M5 ;
        RECT  16.464 59.316 16.488 59.4 ;
    END
  END wq2[24]
  PIN wq2[250]
    DIRECTION INPUT ;
    USE SIGNAL ;
    PORT
      LAYER M5 ;
        RECT  26.64 59.316 26.664 59.4 ;
    END
  END wq2[250]
  PIN wq2[251]
    DIRECTION INPUT ;
    USE SIGNAL ;
    PORT
      LAYER M5 ;
        RECT  26.736 59.316 26.76 59.4 ;
    END
  END wq2[251]
  PIN wq2[252]
    DIRECTION INPUT ;
    USE SIGNAL ;
    PORT
      LAYER M5 ;
        RECT  26.832 59.316 26.856 59.4 ;
    END
  END wq2[252]
  PIN wq2[253]
    DIRECTION INPUT ;
    USE SIGNAL ;
    PORT
      LAYER M5 ;
        RECT  26.928 59.316 26.952 59.4 ;
    END
  END wq2[253]
  PIN wq2[254]
    DIRECTION INPUT ;
    USE SIGNAL ;
    PORT
      LAYER M5 ;
        RECT  27.024 59.316 27.048 59.4 ;
    END
  END wq2[254]
  PIN wq2[255]
    DIRECTION INPUT ;
    USE SIGNAL ;
    PORT
      LAYER M5 ;
        RECT  27.12 59.316 27.144 59.4 ;
    END
  END wq2[255]
  PIN wq2[256]
    DIRECTION INPUT ;
    USE SIGNAL ;
    PORT
      LAYER M5 ;
        RECT  17.808 59.316 17.832 59.4 ;
    END
  END wq2[256]
  PIN wq2[257]
    DIRECTION INPUT ;
    USE SIGNAL ;
    PORT
      LAYER M5 ;
        RECT  17.904 59.316 17.928 59.4 ;
    END
  END wq2[257]
  PIN wq2[258]
    DIRECTION INPUT ;
    USE SIGNAL ;
    PORT
      LAYER M5 ;
        RECT  18 59.316 18.024 59.4 ;
    END
  END wq2[258]
  PIN wq2[259]
    DIRECTION INPUT ;
    USE SIGNAL ;
    PORT
      LAYER M5 ;
        RECT  18.096 59.316 18.12 59.4 ;
    END
  END wq2[259]
  PIN wq2[25]
    DIRECTION INPUT ;
    USE SIGNAL ;
    PORT
      LAYER M5 ;
        RECT  16.56 59.316 16.584 59.4 ;
    END
  END wq2[25]
  PIN wq2[260]
    DIRECTION INPUT ;
    USE SIGNAL ;
    PORT
      LAYER M5 ;
        RECT  18.192 59.316 18.216 59.4 ;
    END
  END wq2[260]
  PIN wq2[261]
    DIRECTION INPUT ;
    USE SIGNAL ;
    PORT
      LAYER M5 ;
        RECT  18.288 59.316 18.312 59.4 ;
    END
  END wq2[261]
  PIN wq2[262]
    DIRECTION INPUT ;
    USE SIGNAL ;
    PORT
      LAYER M5 ;
        RECT  18.384 59.316 18.408 59.4 ;
    END
  END wq2[262]
  PIN wq2[263]
    DIRECTION INPUT ;
    USE SIGNAL ;
    PORT
      LAYER M5 ;
        RECT  18.48 59.316 18.504 59.4 ;
    END
  END wq2[263]
  PIN wq2[264]
    DIRECTION INPUT ;
    USE SIGNAL ;
    PORT
      LAYER M5 ;
        RECT  18.576 59.316 18.6 59.4 ;
    END
  END wq2[264]
  PIN wq2[265]
    DIRECTION INPUT ;
    USE SIGNAL ;
    PORT
      LAYER M5 ;
        RECT  18.672 59.316 18.696 59.4 ;
    END
  END wq2[265]
  PIN wq2[266]
    DIRECTION INPUT ;
    USE SIGNAL ;
    PORT
      LAYER M5 ;
        RECT  18.768 59.316 18.792 59.4 ;
    END
  END wq2[266]
  PIN wq2[267]
    DIRECTION INPUT ;
    USE SIGNAL ;
    PORT
      LAYER M5 ;
        RECT  18.864 59.316 18.888 59.4 ;
    END
  END wq2[267]
  PIN wq2[268]
    DIRECTION INPUT ;
    USE SIGNAL ;
    PORT
      LAYER M5 ;
        RECT  18.96 59.316 18.984 59.4 ;
    END
  END wq2[268]
  PIN wq2[269]
    DIRECTION INPUT ;
    USE SIGNAL ;
    PORT
      LAYER M5 ;
        RECT  19.056 59.316 19.08 59.4 ;
    END
  END wq2[269]
  PIN wq2[26]
    DIRECTION INPUT ;
    USE SIGNAL ;
    PORT
      LAYER M5 ;
        RECT  16.656 59.316 16.68 59.4 ;
    END
  END wq2[26]
  PIN wq2[270]
    DIRECTION INPUT ;
    USE SIGNAL ;
    PORT
      LAYER M5 ;
        RECT  19.152 59.316 19.176 59.4 ;
    END
  END wq2[270]
  PIN wq2[271]
    DIRECTION INPUT ;
    USE SIGNAL ;
    PORT
      LAYER M5 ;
        RECT  19.248 59.316 19.272 59.4 ;
    END
  END wq2[271]
  PIN wq2[272]
    DIRECTION INPUT ;
    USE SIGNAL ;
    PORT
      LAYER M5 ;
        RECT  19.344 59.316 19.368 59.4 ;
    END
  END wq2[272]
  PIN wq2[273]
    DIRECTION INPUT ;
    USE SIGNAL ;
    PORT
      LAYER M5 ;
        RECT  19.44 59.316 19.464 59.4 ;
    END
  END wq2[273]
  PIN wq2[274]
    DIRECTION INPUT ;
    USE SIGNAL ;
    PORT
      LAYER M5 ;
        RECT  19.536 59.316 19.56 59.4 ;
    END
  END wq2[274]
  PIN wq2[275]
    DIRECTION INPUT ;
    USE SIGNAL ;
    PORT
      LAYER M5 ;
        RECT  19.632 59.316 19.656 59.4 ;
    END
  END wq2[275]
  PIN wq2[276]
    DIRECTION INPUT ;
    USE SIGNAL ;
    PORT
      LAYER M5 ;
        RECT  19.728 59.316 19.752 59.4 ;
    END
  END wq2[276]
  PIN wq2[277]
    DIRECTION INPUT ;
    USE SIGNAL ;
    PORT
      LAYER M5 ;
        RECT  19.824 59.316 19.848 59.4 ;
    END
  END wq2[277]
  PIN wq2[278]
    DIRECTION INPUT ;
    USE SIGNAL ;
    PORT
      LAYER M5 ;
        RECT  19.92 59.316 19.944 59.4 ;
    END
  END wq2[278]
  PIN wq2[279]
    DIRECTION INPUT ;
    USE SIGNAL ;
    PORT
      LAYER M5 ;
        RECT  20.016 59.316 20.04 59.4 ;
    END
  END wq2[279]
  PIN wq2[27]
    DIRECTION INPUT ;
    USE SIGNAL ;
    PORT
      LAYER M5 ;
        RECT  16.752 59.316 16.776 59.4 ;
    END
  END wq2[27]
  PIN wq2[280]
    DIRECTION INPUT ;
    USE SIGNAL ;
    PORT
      LAYER M5 ;
        RECT  20.112 59.316 20.136 59.4 ;
    END
  END wq2[280]
  PIN wq2[28]
    DIRECTION INPUT ;
    USE SIGNAL ;
    PORT
      LAYER M5 ;
        RECT  16.848 59.316 16.872 59.4 ;
    END
  END wq2[28]
  PIN wq2[29]
    DIRECTION INPUT ;
    USE SIGNAL ;
    PORT
      LAYER M5 ;
        RECT  16.944 59.316 16.968 59.4 ;
    END
  END wq2[29]
  PIN wq2[2]
    DIRECTION INPUT ;
    USE SIGNAL ;
    PORT
      LAYER M5 ;
        RECT  14.352 59.316 14.376 59.4 ;
    END
  END wq2[2]
  PIN wq2[30]
    DIRECTION INPUT ;
    USE SIGNAL ;
    PORT
      LAYER M5 ;
        RECT  17.04 59.316 17.064 59.4 ;
    END
  END wq2[30]
  PIN wq2[31]
    DIRECTION INPUT ;
    USE SIGNAL ;
    PORT
      LAYER M5 ;
        RECT  17.136 59.316 17.16 59.4 ;
    END
  END wq2[31]
  PIN wq2[32]
    DIRECTION INPUT ;
    USE SIGNAL ;
    PORT
      LAYER M5 ;
        RECT  21.072 59.316 21.096 59.4 ;
    END
  END wq2[32]
  PIN wq2[33]
    DIRECTION INPUT ;
    USE SIGNAL ;
    PORT
      LAYER M5 ;
        RECT  21.168 59.316 21.192 59.4 ;
    END
  END wq2[33]
  PIN wq2[34]
    DIRECTION INPUT ;
    USE SIGNAL ;
    PORT
      LAYER M5 ;
        RECT  21.264 59.316 21.288 59.4 ;
    END
  END wq2[34]
  PIN wq2[35]
    DIRECTION INPUT ;
    USE SIGNAL ;
    PORT
      LAYER M5 ;
        RECT  21.36 59.316 21.384 59.4 ;
    END
  END wq2[35]
  PIN wq2[36]
    DIRECTION INPUT ;
    USE SIGNAL ;
    PORT
      LAYER M5 ;
        RECT  21.456 59.316 21.48 59.4 ;
    END
  END wq2[36]
  PIN wq2[37]
    DIRECTION INPUT ;
    USE SIGNAL ;
    PORT
      LAYER M5 ;
        RECT  21.552 59.316 21.576 59.4 ;
    END
  END wq2[37]
  PIN wq2[38]
    DIRECTION INPUT ;
    USE SIGNAL ;
    PORT
      LAYER M5 ;
        RECT  21.648 59.316 21.672 59.4 ;
    END
  END wq2[38]
  PIN wq2[39]
    DIRECTION INPUT ;
    USE SIGNAL ;
    PORT
      LAYER M5 ;
        RECT  21.744 59.316 21.768 59.4 ;
    END
  END wq2[39]
  PIN wq2[3]
    DIRECTION INPUT ;
    USE SIGNAL ;
    PORT
      LAYER M5 ;
        RECT  14.448 59.316 14.472 59.4 ;
    END
  END wq2[3]
  PIN wq2[40]
    DIRECTION INPUT ;
    USE SIGNAL ;
    PORT
      LAYER M5 ;
        RECT  21.84 59.316 21.864 59.4 ;
    END
  END wq2[40]
  PIN wq2[41]
    DIRECTION INPUT ;
    USE SIGNAL ;
    PORT
      LAYER M5 ;
        RECT  21.936 59.316 21.96 59.4 ;
    END
  END wq2[41]
  PIN wq2[42]
    DIRECTION INPUT ;
    USE SIGNAL ;
    PORT
      LAYER M5 ;
        RECT  22.032 59.316 22.056 59.4 ;
    END
  END wq2[42]
  PIN wq2[43]
    DIRECTION INPUT ;
    USE SIGNAL ;
    PORT
      LAYER M5 ;
        RECT  22.128 59.316 22.152 59.4 ;
    END
  END wq2[43]
  PIN wq2[44]
    DIRECTION INPUT ;
    USE SIGNAL ;
    PORT
      LAYER M5 ;
        RECT  22.224 59.316 22.248 59.4 ;
    END
  END wq2[44]
  PIN wq2[45]
    DIRECTION INPUT ;
    USE SIGNAL ;
    PORT
      LAYER M5 ;
        RECT  22.32 59.316 22.344 59.4 ;
    END
  END wq2[45]
  PIN wq2[46]
    DIRECTION INPUT ;
    USE SIGNAL ;
    PORT
      LAYER M5 ;
        RECT  22.416 59.316 22.44 59.4 ;
    END
  END wq2[46]
  PIN wq2[47]
    DIRECTION INPUT ;
    USE SIGNAL ;
    PORT
      LAYER M5 ;
        RECT  22.512 59.316 22.536 59.4 ;
    END
  END wq2[47]
  PIN wq2[48]
    DIRECTION INPUT ;
    USE SIGNAL ;
    PORT
      LAYER M5 ;
        RECT  22.608 59.316 22.632 59.4 ;
    END
  END wq2[48]
  PIN wq2[49]
    DIRECTION INPUT ;
    USE SIGNAL ;
    PORT
      LAYER M5 ;
        RECT  22.704 59.316 22.728 59.4 ;
    END
  END wq2[49]
  PIN wq2[4]
    DIRECTION INPUT ;
    USE SIGNAL ;
    PORT
      LAYER M5 ;
        RECT  14.544 59.316 14.568 59.4 ;
    END
  END wq2[4]
  PIN wq2[50]
    DIRECTION INPUT ;
    USE SIGNAL ;
    PORT
      LAYER M5 ;
        RECT  22.8 59.316 22.824 59.4 ;
    END
  END wq2[50]
  PIN wq2[51]
    DIRECTION INPUT ;
    USE SIGNAL ;
    PORT
      LAYER M5 ;
        RECT  22.896 59.316 22.92 59.4 ;
    END
  END wq2[51]
  PIN wq2[52]
    DIRECTION INPUT ;
    USE SIGNAL ;
    PORT
      LAYER M5 ;
        RECT  22.992 59.316 23.016 59.4 ;
    END
  END wq2[52]
  PIN wq2[53]
    DIRECTION INPUT ;
    USE SIGNAL ;
    PORT
      LAYER M5 ;
        RECT  23.088 59.316 23.112 59.4 ;
    END
  END wq2[53]
  PIN wq2[54]
    DIRECTION INPUT ;
    USE SIGNAL ;
    PORT
      LAYER M5 ;
        RECT  23.184 59.316 23.208 59.4 ;
    END
  END wq2[54]
  PIN wq2[55]
    DIRECTION INPUT ;
    USE SIGNAL ;
    PORT
      LAYER M5 ;
        RECT  23.28 59.316 23.304 59.4 ;
    END
  END wq2[55]
  PIN wq2[56]
    DIRECTION INPUT ;
    USE SIGNAL ;
    PORT
      LAYER M5 ;
        RECT  23.376 59.316 23.4 59.4 ;
    END
  END wq2[56]
  PIN wq2[57]
    DIRECTION INPUT ;
    USE SIGNAL ;
    PORT
      LAYER M5 ;
        RECT  23.472 59.316 23.496 59.4 ;
    END
  END wq2[57]
  PIN wq2[58]
    DIRECTION INPUT ;
    USE SIGNAL ;
    PORT
      LAYER M5 ;
        RECT  23.568 59.316 23.592 59.4 ;
    END
  END wq2[58]
  PIN wq2[59]
    DIRECTION INPUT ;
    USE SIGNAL ;
    PORT
      LAYER M5 ;
        RECT  23.664 59.316 23.688 59.4 ;
    END
  END wq2[59]
  PIN wq2[5]
    DIRECTION INPUT ;
    USE SIGNAL ;
    PORT
      LAYER M5 ;
        RECT  14.64 59.316 14.664 59.4 ;
    END
  END wq2[5]
  PIN wq2[60]
    DIRECTION INPUT ;
    USE SIGNAL ;
    PORT
      LAYER M5 ;
        RECT  23.76 59.316 23.784 59.4 ;
    END
  END wq2[60]
  PIN wq2[61]
    DIRECTION INPUT ;
    USE SIGNAL ;
    PORT
      LAYER M5 ;
        RECT  23.856 59.316 23.88 59.4 ;
    END
  END wq2[61]
  PIN wq2[62]
    DIRECTION INPUT ;
    USE SIGNAL ;
    PORT
      LAYER M5 ;
        RECT  23.952 59.316 23.976 59.4 ;
    END
  END wq2[62]
  PIN wq2[63]
    DIRECTION INPUT ;
    USE SIGNAL ;
    PORT
      LAYER M5 ;
        RECT  24.048 59.316 24.072 59.4 ;
    END
  END wq2[63]
  PIN wq2[64]
    DIRECTION INPUT ;
    USE SIGNAL ;
    PORT
      LAYER M5 ;
        RECT  27.216 59.316 27.24 59.4 ;
    END
  END wq2[64]
  PIN wq2[65]
    DIRECTION INPUT ;
    USE SIGNAL ;
    PORT
      LAYER M5 ;
        RECT  27.312 59.316 27.336 59.4 ;
    END
  END wq2[65]
  PIN wq2[66]
    DIRECTION INPUT ;
    USE SIGNAL ;
    PORT
      LAYER M5 ;
        RECT  27.408 59.316 27.432 59.4 ;
    END
  END wq2[66]
  PIN wq2[67]
    DIRECTION INPUT ;
    USE SIGNAL ;
    PORT
      LAYER M5 ;
        RECT  27.504 59.316 27.528 59.4 ;
    END
  END wq2[67]
  PIN wq2[68]
    DIRECTION INPUT ;
    USE SIGNAL ;
    PORT
      LAYER M5 ;
        RECT  27.6 59.316 27.624 59.4 ;
    END
  END wq2[68]
  PIN wq2[69]
    DIRECTION INPUT ;
    USE SIGNAL ;
    PORT
      LAYER M5 ;
        RECT  27.696 59.316 27.72 59.4 ;
    END
  END wq2[69]
  PIN wq2[6]
    DIRECTION INPUT ;
    USE SIGNAL ;
    PORT
      LAYER M5 ;
        RECT  14.736 59.316 14.76 59.4 ;
    END
  END wq2[6]
  PIN wq2[70]
    DIRECTION INPUT ;
    USE SIGNAL ;
    PORT
      LAYER M5 ;
        RECT  27.792 59.316 27.816 59.4 ;
    END
  END wq2[70]
  PIN wq2[71]
    DIRECTION INPUT ;
    USE SIGNAL ;
    PORT
      LAYER M5 ;
        RECT  27.888 59.316 27.912 59.4 ;
    END
  END wq2[71]
  PIN wq2[72]
    DIRECTION INPUT ;
    USE SIGNAL ;
    PORT
      LAYER M5 ;
        RECT  27.984 59.316 28.008 59.4 ;
    END
  END wq2[72]
  PIN wq2[73]
    DIRECTION INPUT ;
    USE SIGNAL ;
    PORT
      LAYER M5 ;
        RECT  28.08 59.316 28.104 59.4 ;
    END
  END wq2[73]
  PIN wq2[74]
    DIRECTION INPUT ;
    USE SIGNAL ;
    PORT
      LAYER M5 ;
        RECT  28.176 59.316 28.2 59.4 ;
    END
  END wq2[74]
  PIN wq2[75]
    DIRECTION INPUT ;
    USE SIGNAL ;
    PORT
      LAYER M5 ;
        RECT  28.272 59.316 28.296 59.4 ;
    END
  END wq2[75]
  PIN wq2[76]
    DIRECTION INPUT ;
    USE SIGNAL ;
    PORT
      LAYER M5 ;
        RECT  28.368 59.316 28.392 59.4 ;
    END
  END wq2[76]
  PIN wq2[77]
    DIRECTION INPUT ;
    USE SIGNAL ;
    PORT
      LAYER M5 ;
        RECT  28.464 59.316 28.488 59.4 ;
    END
  END wq2[77]
  PIN wq2[78]
    DIRECTION INPUT ;
    USE SIGNAL ;
    PORT
      LAYER M5 ;
        RECT  28.56 59.316 28.584 59.4 ;
    END
  END wq2[78]
  PIN wq2[79]
    DIRECTION INPUT ;
    USE SIGNAL ;
    PORT
      LAYER M5 ;
        RECT  28.656 59.316 28.68 59.4 ;
    END
  END wq2[79]
  PIN wq2[7]
    DIRECTION INPUT ;
    USE SIGNAL ;
    PORT
      LAYER M5 ;
        RECT  14.832 59.316 14.856 59.4 ;
    END
  END wq2[7]
  PIN wq2[80]
    DIRECTION INPUT ;
    USE SIGNAL ;
    PORT
      LAYER M5 ;
        RECT  28.752 59.316 28.776 59.4 ;
    END
  END wq2[80]
  PIN wq2[81]
    DIRECTION INPUT ;
    USE SIGNAL ;
    PORT
      LAYER M5 ;
        RECT  28.848 59.316 28.872 59.4 ;
    END
  END wq2[81]
  PIN wq2[82]
    DIRECTION INPUT ;
    USE SIGNAL ;
    PORT
      LAYER M5 ;
        RECT  28.944 59.316 28.968 59.4 ;
    END
  END wq2[82]
  PIN wq2[83]
    DIRECTION INPUT ;
    USE SIGNAL ;
    PORT
      LAYER M5 ;
        RECT  29.04 59.316 29.064 59.4 ;
    END
  END wq2[83]
  PIN wq2[84]
    DIRECTION INPUT ;
    USE SIGNAL ;
    PORT
      LAYER M5 ;
        RECT  29.136 59.316 29.16 59.4 ;
    END
  END wq2[84]
  PIN wq2[85]
    DIRECTION INPUT ;
    USE SIGNAL ;
    PORT
      LAYER M5 ;
        RECT  29.232 59.316 29.256 59.4 ;
    END
  END wq2[85]
  PIN wq2[86]
    DIRECTION INPUT ;
    USE SIGNAL ;
    PORT
      LAYER M5 ;
        RECT  29.328 59.316 29.352 59.4 ;
    END
  END wq2[86]
  PIN wq2[87]
    DIRECTION INPUT ;
    USE SIGNAL ;
    PORT
      LAYER M5 ;
        RECT  29.424 59.316 29.448 59.4 ;
    END
  END wq2[87]
  PIN wq2[88]
    DIRECTION INPUT ;
    USE SIGNAL ;
    PORT
      LAYER M5 ;
        RECT  29.52 59.316 29.544 59.4 ;
    END
  END wq2[88]
  PIN wq2[89]
    DIRECTION INPUT ;
    USE SIGNAL ;
    PORT
      LAYER M5 ;
        RECT  29.616 59.316 29.64 59.4 ;
    END
  END wq2[89]
  PIN wq2[8]
    DIRECTION INPUT ;
    USE SIGNAL ;
    PORT
      LAYER M5 ;
        RECT  14.928 59.316 14.952 59.4 ;
    END
  END wq2[8]
  PIN wq2[90]
    DIRECTION INPUT ;
    USE SIGNAL ;
    PORT
      LAYER M5 ;
        RECT  29.712 59.316 29.736 59.4 ;
    END
  END wq2[90]
  PIN wq2[91]
    DIRECTION INPUT ;
    USE SIGNAL ;
    PORT
      LAYER M5 ;
        RECT  29.808 59.316 29.832 59.4 ;
    END
  END wq2[91]
  PIN wq2[92]
    DIRECTION INPUT ;
    USE SIGNAL ;
    PORT
      LAYER M5 ;
        RECT  29.904 59.316 29.928 59.4 ;
    END
  END wq2[92]
  PIN wq2[93]
    DIRECTION INPUT ;
    USE SIGNAL ;
    PORT
      LAYER M5 ;
        RECT  30 59.316 30.024 59.4 ;
    END
  END wq2[93]
  PIN wq2[94]
    DIRECTION INPUT ;
    USE SIGNAL ;
    PORT
      LAYER M5 ;
        RECT  30.096 59.316 30.12 59.4 ;
    END
  END wq2[94]
  PIN wq2[95]
    DIRECTION INPUT ;
    USE SIGNAL ;
    PORT
      LAYER M5 ;
        RECT  30.192 59.316 30.216 59.4 ;
    END
  END wq2[95]
  PIN wq2[96]
    DIRECTION INPUT ;
    USE SIGNAL ;
    PORT
      LAYER M5 ;
        RECT  36.432 59.316 36.456 59.4 ;
    END
  END wq2[96]
  PIN wq2[97]
    DIRECTION INPUT ;
    USE SIGNAL ;
    PORT
      LAYER M5 ;
        RECT  36.528 59.316 36.552 59.4 ;
    END
  END wq2[97]
  PIN wq2[98]
    DIRECTION INPUT ;
    USE SIGNAL ;
    PORT
      LAYER M5 ;
        RECT  36.624 59.316 36.648 59.4 ;
    END
  END wq2[98]
  PIN wq2[99]
    DIRECTION INPUT ;
    USE SIGNAL ;
    PORT
      LAYER M5 ;
        RECT  36.72 59.316 36.744 59.4 ;
    END
  END wq2[99]
  PIN wq2[9]
    DIRECTION INPUT ;
    USE SIGNAL ;
    PORT
      LAYER M5 ;
        RECT  15.024 59.316 15.048 59.4 ;
    END
  END wq2[9]
  PIN wq_done1
    DIRECTION OUTPUT ;
    USE SIGNAL ;
    PORT
      LAYER M4 ;
        RECT  59.316 41.52 59.4 41.544 ;
    END
  END wq_done1
  PIN wq_done2
    DIRECTION OUTPUT ;
    USE SIGNAL ;
    PORT
      LAYER M5 ;
        RECT  20.208 59.316 20.232 59.4 ;
    END
  END wq_done2
  PIN wq_m[0]
    DIRECTION OUTPUT ;
    USE SIGNAL ;
    PORT
      LAYER M4 ;
        RECT  0 24.24 0.084 24.264 ;
    END
  END wq_m[0]
  PIN wq_m[100]
    DIRECTION OUTPUT ;
    USE SIGNAL ;
    PORT
      LAYER M4 ;
        RECT  0 27.696 0.084 27.72 ;
    END
  END wq_m[100]
  PIN wq_m[101]
    DIRECTION OUTPUT ;
    USE SIGNAL ;
    PORT
      LAYER M4 ;
        RECT  0 27.792 0.084 27.816 ;
    END
  END wq_m[101]
  PIN wq_m[102]
    DIRECTION OUTPUT ;
    USE SIGNAL ;
    PORT
      LAYER M4 ;
        RECT  0 27.888 0.084 27.912 ;
    END
  END wq_m[102]
  PIN wq_m[103]
    DIRECTION OUTPUT ;
    USE SIGNAL ;
    PORT
      LAYER M4 ;
        RECT  0 27.984 0.084 28.008 ;
    END
  END wq_m[103]
  PIN wq_m[104]
    DIRECTION OUTPUT ;
    USE SIGNAL ;
    PORT
      LAYER M4 ;
        RECT  0 28.08 0.084 28.104 ;
    END
  END wq_m[104]
  PIN wq_m[105]
    DIRECTION OUTPUT ;
    USE SIGNAL ;
    PORT
      LAYER M4 ;
        RECT  0 28.176 0.084 28.2 ;
    END
  END wq_m[105]
  PIN wq_m[106]
    DIRECTION OUTPUT ;
    USE SIGNAL ;
    PORT
      LAYER M4 ;
        RECT  0 28.272 0.084 28.296 ;
    END
  END wq_m[106]
  PIN wq_m[107]
    DIRECTION OUTPUT ;
    USE SIGNAL ;
    PORT
      LAYER M4 ;
        RECT  0 28.368 0.084 28.392 ;
    END
  END wq_m[107]
  PIN wq_m[108]
    DIRECTION OUTPUT ;
    USE SIGNAL ;
    PORT
      LAYER M4 ;
        RECT  0 28.464 0.084 28.488 ;
    END
  END wq_m[108]
  PIN wq_m[109]
    DIRECTION OUTPUT ;
    USE SIGNAL ;
    PORT
      LAYER M4 ;
        RECT  0 28.56 0.084 28.584 ;
    END
  END wq_m[109]
  PIN wq_m[10]
    DIRECTION OUTPUT ;
    USE SIGNAL ;
    PORT
      LAYER M4 ;
        RECT  0 25.2 0.084 25.224 ;
    END
  END wq_m[10]
  PIN wq_m[110]
    DIRECTION OUTPUT ;
    USE SIGNAL ;
    PORT
      LAYER M4 ;
        RECT  0 28.656 0.084 28.68 ;
    END
  END wq_m[110]
  PIN wq_m[111]
    DIRECTION OUTPUT ;
    USE SIGNAL ;
    PORT
      LAYER M4 ;
        RECT  0 28.752 0.084 28.776 ;
    END
  END wq_m[111]
  PIN wq_m[112]
    DIRECTION OUTPUT ;
    USE SIGNAL ;
    PORT
      LAYER M4 ;
        RECT  0 28.848 0.084 28.872 ;
    END
  END wq_m[112]
  PIN wq_m[113]
    DIRECTION OUTPUT ;
    USE SIGNAL ;
    PORT
      LAYER M4 ;
        RECT  0 28.944 0.084 28.968 ;
    END
  END wq_m[113]
  PIN wq_m[114]
    DIRECTION OUTPUT ;
    USE SIGNAL ;
    PORT
      LAYER M4 ;
        RECT  0 29.04 0.084 29.064 ;
    END
  END wq_m[114]
  PIN wq_m[115]
    DIRECTION OUTPUT ;
    USE SIGNAL ;
    PORT
      LAYER M4 ;
        RECT  0 29.136 0.084 29.16 ;
    END
  END wq_m[115]
  PIN wq_m[116]
    DIRECTION OUTPUT ;
    USE SIGNAL ;
    PORT
      LAYER M4 ;
        RECT  0 29.232 0.084 29.256 ;
    END
  END wq_m[116]
  PIN wq_m[117]
    DIRECTION OUTPUT ;
    USE SIGNAL ;
    PORT
      LAYER M4 ;
        RECT  0 29.328 0.084 29.352 ;
    END
  END wq_m[117]
  PIN wq_m[118]
    DIRECTION OUTPUT ;
    USE SIGNAL ;
    PORT
      LAYER M4 ;
        RECT  0 29.424 0.084 29.448 ;
    END
  END wq_m[118]
  PIN wq_m[119]
    DIRECTION OUTPUT ;
    USE SIGNAL ;
    PORT
      LAYER M4 ;
        RECT  0 29.52 0.084 29.544 ;
    END
  END wq_m[119]
  PIN wq_m[11]
    DIRECTION OUTPUT ;
    USE SIGNAL ;
    PORT
      LAYER M4 ;
        RECT  0 25.296 0.084 25.32 ;
    END
  END wq_m[11]
  PIN wq_m[120]
    DIRECTION OUTPUT ;
    USE SIGNAL ;
    PORT
      LAYER M4 ;
        RECT  0 29.616 0.084 29.64 ;
    END
  END wq_m[120]
  PIN wq_m[121]
    DIRECTION OUTPUT ;
    USE SIGNAL ;
    PORT
      LAYER M4 ;
        RECT  0 29.712 0.084 29.736 ;
    END
  END wq_m[121]
  PIN wq_m[122]
    DIRECTION OUTPUT ;
    USE SIGNAL ;
    PORT
      LAYER M4 ;
        RECT  0 29.808 0.084 29.832 ;
    END
  END wq_m[122]
  PIN wq_m[123]
    DIRECTION OUTPUT ;
    USE SIGNAL ;
    PORT
      LAYER M4 ;
        RECT  0 29.904 0.084 29.928 ;
    END
  END wq_m[123]
  PIN wq_m[124]
    DIRECTION OUTPUT ;
    USE SIGNAL ;
    PORT
      LAYER M4 ;
        RECT  0 30 0.084 30.024 ;
    END
  END wq_m[124]
  PIN wq_m[125]
    DIRECTION OUTPUT ;
    USE SIGNAL ;
    PORT
      LAYER M4 ;
        RECT  0 30.096 0.084 30.12 ;
    END
  END wq_m[125]
  PIN wq_m[126]
    DIRECTION OUTPUT ;
    USE SIGNAL ;
    PORT
      LAYER M4 ;
        RECT  0 30.192 0.084 30.216 ;
    END
  END wq_m[126]
  PIN wq_m[127]
    DIRECTION OUTPUT ;
    USE SIGNAL ;
    PORT
      LAYER M4 ;
        RECT  0 30.288 0.084 30.312 ;
    END
  END wq_m[127]
  PIN wq_m[128]
    DIRECTION OUTPUT ;
    USE SIGNAL ;
    PORT
      LAYER M4 ;
        RECT  0 30.384 0.084 30.408 ;
    END
  END wq_m[128]
  PIN wq_m[129]
    DIRECTION OUTPUT ;
    USE SIGNAL ;
    PORT
      LAYER M4 ;
        RECT  0 30.48 0.084 30.504 ;
    END
  END wq_m[129]
  PIN wq_m[12]
    DIRECTION OUTPUT ;
    USE SIGNAL ;
    PORT
      LAYER M4 ;
        RECT  0 25.392 0.084 25.416 ;
    END
  END wq_m[12]
  PIN wq_m[130]
    DIRECTION OUTPUT ;
    USE SIGNAL ;
    PORT
      LAYER M4 ;
        RECT  0 30.576 0.084 30.6 ;
    END
  END wq_m[130]
  PIN wq_m[131]
    DIRECTION OUTPUT ;
    USE SIGNAL ;
    PORT
      LAYER M4 ;
        RECT  0 30.672 0.084 30.696 ;
    END
  END wq_m[131]
  PIN wq_m[132]
    DIRECTION OUTPUT ;
    USE SIGNAL ;
    PORT
      LAYER M4 ;
        RECT  0 30.768 0.084 30.792 ;
    END
  END wq_m[132]
  PIN wq_m[133]
    DIRECTION OUTPUT ;
    USE SIGNAL ;
    PORT
      LAYER M4 ;
        RECT  0 30.864 0.084 30.888 ;
    END
  END wq_m[133]
  PIN wq_m[134]
    DIRECTION OUTPUT ;
    USE SIGNAL ;
    PORT
      LAYER M4 ;
        RECT  0 30.96 0.084 30.984 ;
    END
  END wq_m[134]
  PIN wq_m[135]
    DIRECTION OUTPUT ;
    USE SIGNAL ;
    PORT
      LAYER M4 ;
        RECT  0 31.056 0.084 31.08 ;
    END
  END wq_m[135]
  PIN wq_m[136]
    DIRECTION OUTPUT ;
    USE SIGNAL ;
    PORT
      LAYER M4 ;
        RECT  0 31.152 0.084 31.176 ;
    END
  END wq_m[136]
  PIN wq_m[137]
    DIRECTION OUTPUT ;
    USE SIGNAL ;
    PORT
      LAYER M4 ;
        RECT  0 31.248 0.084 31.272 ;
    END
  END wq_m[137]
  PIN wq_m[138]
    DIRECTION OUTPUT ;
    USE SIGNAL ;
    PORT
      LAYER M4 ;
        RECT  0 31.344 0.084 31.368 ;
    END
  END wq_m[138]
  PIN wq_m[139]
    DIRECTION OUTPUT ;
    USE SIGNAL ;
    PORT
      LAYER M4 ;
        RECT  0 31.44 0.084 31.464 ;
    END
  END wq_m[139]
  PIN wq_m[13]
    DIRECTION OUTPUT ;
    USE SIGNAL ;
    PORT
      LAYER M4 ;
        RECT  0 25.488 0.084 25.512 ;
    END
  END wq_m[13]
  PIN wq_m[140]
    DIRECTION OUTPUT ;
    USE SIGNAL ;
    PORT
      LAYER M4 ;
        RECT  0 31.536 0.084 31.56 ;
    END
  END wq_m[140]
  PIN wq_m[141]
    DIRECTION OUTPUT ;
    USE SIGNAL ;
    PORT
      LAYER M4 ;
        RECT  0 31.632 0.084 31.656 ;
    END
  END wq_m[141]
  PIN wq_m[142]
    DIRECTION OUTPUT ;
    USE SIGNAL ;
    PORT
      LAYER M4 ;
        RECT  0 31.728 0.084 31.752 ;
    END
  END wq_m[142]
  PIN wq_m[143]
    DIRECTION OUTPUT ;
    USE SIGNAL ;
    PORT
      LAYER M4 ;
        RECT  0 31.824 0.084 31.848 ;
    END
  END wq_m[143]
  PIN wq_m[144]
    DIRECTION OUTPUT ;
    USE SIGNAL ;
    PORT
      LAYER M4 ;
        RECT  0 31.92 0.084 31.944 ;
    END
  END wq_m[144]
  PIN wq_m[145]
    DIRECTION OUTPUT ;
    USE SIGNAL ;
    PORT
      LAYER M4 ;
        RECT  0 32.016 0.084 32.04 ;
    END
  END wq_m[145]
  PIN wq_m[146]
    DIRECTION OUTPUT ;
    USE SIGNAL ;
    PORT
      LAYER M4 ;
        RECT  0 32.112 0.084 32.136 ;
    END
  END wq_m[146]
  PIN wq_m[147]
    DIRECTION OUTPUT ;
    USE SIGNAL ;
    PORT
      LAYER M4 ;
        RECT  0 32.208 0.084 32.232 ;
    END
  END wq_m[147]
  PIN wq_m[148]
    DIRECTION OUTPUT ;
    USE SIGNAL ;
    PORT
      LAYER M4 ;
        RECT  0 32.304 0.084 32.328 ;
    END
  END wq_m[148]
  PIN wq_m[149]
    DIRECTION OUTPUT ;
    USE SIGNAL ;
    PORT
      LAYER M4 ;
        RECT  0 32.4 0.084 32.424 ;
    END
  END wq_m[149]
  PIN wq_m[14]
    DIRECTION OUTPUT ;
    USE SIGNAL ;
    PORT
      LAYER M4 ;
        RECT  0 25.584 0.084 25.608 ;
    END
  END wq_m[14]
  PIN wq_m[150]
    DIRECTION OUTPUT ;
    USE SIGNAL ;
    PORT
      LAYER M4 ;
        RECT  0 32.496 0.084 32.52 ;
    END
  END wq_m[150]
  PIN wq_m[151]
    DIRECTION OUTPUT ;
    USE SIGNAL ;
    PORT
      LAYER M4 ;
        RECT  0 32.592 0.084 32.616 ;
    END
  END wq_m[151]
  PIN wq_m[152]
    DIRECTION OUTPUT ;
    USE SIGNAL ;
    PORT
      LAYER M4 ;
        RECT  0 32.688 0.084 32.712 ;
    END
  END wq_m[152]
  PIN wq_m[153]
    DIRECTION OUTPUT ;
    USE SIGNAL ;
    PORT
      LAYER M4 ;
        RECT  0 32.784 0.084 32.808 ;
    END
  END wq_m[153]
  PIN wq_m[154]
    DIRECTION OUTPUT ;
    USE SIGNAL ;
    PORT
      LAYER M4 ;
        RECT  0 32.88 0.084 32.904 ;
    END
  END wq_m[154]
  PIN wq_m[155]
    DIRECTION OUTPUT ;
    USE SIGNAL ;
    PORT
      LAYER M4 ;
        RECT  0 32.976 0.084 33 ;
    END
  END wq_m[155]
  PIN wq_m[156]
    DIRECTION OUTPUT ;
    USE SIGNAL ;
    PORT
      LAYER M4 ;
        RECT  0 33.072 0.084 33.096 ;
    END
  END wq_m[156]
  PIN wq_m[157]
    DIRECTION OUTPUT ;
    USE SIGNAL ;
    PORT
      LAYER M4 ;
        RECT  0 33.168 0.084 33.192 ;
    END
  END wq_m[157]
  PIN wq_m[158]
    DIRECTION OUTPUT ;
    USE SIGNAL ;
    PORT
      LAYER M4 ;
        RECT  0 33.264 0.084 33.288 ;
    END
  END wq_m[158]
  PIN wq_m[159]
    DIRECTION OUTPUT ;
    USE SIGNAL ;
    PORT
      LAYER M4 ;
        RECT  0 21.072 0.084 21.096 ;
    END
  END wq_m[159]
  PIN wq_m[15]
    DIRECTION OUTPUT ;
    USE SIGNAL ;
    PORT
      LAYER M4 ;
        RECT  0 25.68 0.084 25.704 ;
    END
  END wq_m[15]
  PIN wq_m[160]
    DIRECTION OUTPUT ;
    USE SIGNAL ;
    PORT
      LAYER M4 ;
        RECT  0 21.168 0.084 21.192 ;
    END
  END wq_m[160]
  PIN wq_m[161]
    DIRECTION OUTPUT ;
    USE SIGNAL ;
    PORT
      LAYER M4 ;
        RECT  0 21.264 0.084 21.288 ;
    END
  END wq_m[161]
  PIN wq_m[162]
    DIRECTION OUTPUT ;
    USE SIGNAL ;
    PORT
      LAYER M4 ;
        RECT  0 21.36 0.084 21.384 ;
    END
  END wq_m[162]
  PIN wq_m[163]
    DIRECTION OUTPUT ;
    USE SIGNAL ;
    PORT
      LAYER M4 ;
        RECT  0 21.456 0.084 21.48 ;
    END
  END wq_m[163]
  PIN wq_m[164]
    DIRECTION OUTPUT ;
    USE SIGNAL ;
    PORT
      LAYER M4 ;
        RECT  0 21.552 0.084 21.576 ;
    END
  END wq_m[164]
  PIN wq_m[165]
    DIRECTION OUTPUT ;
    USE SIGNAL ;
    PORT
      LAYER M4 ;
        RECT  0 21.648 0.084 21.672 ;
    END
  END wq_m[165]
  PIN wq_m[166]
    DIRECTION OUTPUT ;
    USE SIGNAL ;
    PORT
      LAYER M4 ;
        RECT  0 21.744 0.084 21.768 ;
    END
  END wq_m[166]
  PIN wq_m[167]
    DIRECTION OUTPUT ;
    USE SIGNAL ;
    PORT
      LAYER M4 ;
        RECT  0 21.84 0.084 21.864 ;
    END
  END wq_m[167]
  PIN wq_m[168]
    DIRECTION OUTPUT ;
    USE SIGNAL ;
    PORT
      LAYER M4 ;
        RECT  0 21.936 0.084 21.96 ;
    END
  END wq_m[168]
  PIN wq_m[169]
    DIRECTION OUTPUT ;
    USE SIGNAL ;
    PORT
      LAYER M4 ;
        RECT  0 22.032 0.084 22.056 ;
    END
  END wq_m[169]
  PIN wq_m[16]
    DIRECTION OUTPUT ;
    USE SIGNAL ;
    PORT
      LAYER M4 ;
        RECT  0 25.776 0.084 25.8 ;
    END
  END wq_m[16]
  PIN wq_m[170]
    DIRECTION OUTPUT ;
    USE SIGNAL ;
    PORT
      LAYER M4 ;
        RECT  0 22.128 0.084 22.152 ;
    END
  END wq_m[170]
  PIN wq_m[171]
    DIRECTION OUTPUT ;
    USE SIGNAL ;
    PORT
      LAYER M4 ;
        RECT  0 22.224 0.084 22.248 ;
    END
  END wq_m[171]
  PIN wq_m[172]
    DIRECTION OUTPUT ;
    USE SIGNAL ;
    PORT
      LAYER M4 ;
        RECT  0 22.32 0.084 22.344 ;
    END
  END wq_m[172]
  PIN wq_m[173]
    DIRECTION OUTPUT ;
    USE SIGNAL ;
    PORT
      LAYER M4 ;
        RECT  0 22.416 0.084 22.44 ;
    END
  END wq_m[173]
  PIN wq_m[174]
    DIRECTION OUTPUT ;
    USE SIGNAL ;
    PORT
      LAYER M4 ;
        RECT  0 22.512 0.084 22.536 ;
    END
  END wq_m[174]
  PIN wq_m[175]
    DIRECTION OUTPUT ;
    USE SIGNAL ;
    PORT
      LAYER M4 ;
        RECT  0 22.608 0.084 22.632 ;
    END
  END wq_m[175]
  PIN wq_m[176]
    DIRECTION OUTPUT ;
    USE SIGNAL ;
    PORT
      LAYER M4 ;
        RECT  0 22.704 0.084 22.728 ;
    END
  END wq_m[176]
  PIN wq_m[177]
    DIRECTION OUTPUT ;
    USE SIGNAL ;
    PORT
      LAYER M4 ;
        RECT  0 22.8 0.084 22.824 ;
    END
  END wq_m[177]
  PIN wq_m[178]
    DIRECTION OUTPUT ;
    USE SIGNAL ;
    PORT
      LAYER M4 ;
        RECT  0 22.896 0.084 22.92 ;
    END
  END wq_m[178]
  PIN wq_m[179]
    DIRECTION OUTPUT ;
    USE SIGNAL ;
    PORT
      LAYER M4 ;
        RECT  0 22.992 0.084 23.016 ;
    END
  END wq_m[179]
  PIN wq_m[17]
    DIRECTION OUTPUT ;
    USE SIGNAL ;
    PORT
      LAYER M4 ;
        RECT  0 25.872 0.084 25.896 ;
    END
  END wq_m[17]
  PIN wq_m[180]
    DIRECTION OUTPUT ;
    USE SIGNAL ;
    PORT
      LAYER M4 ;
        RECT  0 23.088 0.084 23.112 ;
    END
  END wq_m[180]
  PIN wq_m[181]
    DIRECTION OUTPUT ;
    USE SIGNAL ;
    PORT
      LAYER M4 ;
        RECT  0 23.184 0.084 23.208 ;
    END
  END wq_m[181]
  PIN wq_m[182]
    DIRECTION OUTPUT ;
    USE SIGNAL ;
    PORT
      LAYER M4 ;
        RECT  0 23.28 0.084 23.304 ;
    END
  END wq_m[182]
  PIN wq_m[183]
    DIRECTION OUTPUT ;
    USE SIGNAL ;
    PORT
      LAYER M4 ;
        RECT  0 23.376 0.084 23.4 ;
    END
  END wq_m[183]
  PIN wq_m[184]
    DIRECTION OUTPUT ;
    USE SIGNAL ;
    PORT
      LAYER M4 ;
        RECT  0 23.472 0.084 23.496 ;
    END
  END wq_m[184]
  PIN wq_m[185]
    DIRECTION OUTPUT ;
    USE SIGNAL ;
    PORT
      LAYER M4 ;
        RECT  0 23.568 0.084 23.592 ;
    END
  END wq_m[185]
  PIN wq_m[186]
    DIRECTION OUTPUT ;
    USE SIGNAL ;
    PORT
      LAYER M4 ;
        RECT  0 23.664 0.084 23.688 ;
    END
  END wq_m[186]
  PIN wq_m[187]
    DIRECTION OUTPUT ;
    USE SIGNAL ;
    PORT
      LAYER M4 ;
        RECT  0 23.76 0.084 23.784 ;
    END
  END wq_m[187]
  PIN wq_m[188]
    DIRECTION OUTPUT ;
    USE SIGNAL ;
    PORT
      LAYER M4 ;
        RECT  0 23.856 0.084 23.88 ;
    END
  END wq_m[188]
  PIN wq_m[189]
    DIRECTION OUTPUT ;
    USE SIGNAL ;
    PORT
      LAYER M4 ;
        RECT  0 23.952 0.084 23.976 ;
    END
  END wq_m[189]
  PIN wq_m[18]
    DIRECTION OUTPUT ;
    USE SIGNAL ;
    PORT
      LAYER M4 ;
        RECT  0 25.968 0.084 25.992 ;
    END
  END wq_m[18]
  PIN wq_m[190]
    DIRECTION OUTPUT ;
    USE SIGNAL ;
    PORT
      LAYER M4 ;
        RECT  0 24.048 0.084 24.072 ;
    END
  END wq_m[190]
  PIN wq_m[191]
    DIRECTION OUTPUT ;
    USE SIGNAL ;
    PORT
      LAYER M4 ;
        RECT  0 36.432 0.084 36.456 ;
    END
  END wq_m[191]
  PIN wq_m[192]
    DIRECTION OUTPUT ;
    USE SIGNAL ;
    PORT
      LAYER M4 ;
        RECT  0 36.528 0.084 36.552 ;
    END
  END wq_m[192]
  PIN wq_m[193]
    DIRECTION OUTPUT ;
    USE SIGNAL ;
    PORT
      LAYER M4 ;
        RECT  0 36.624 0.084 36.648 ;
    END
  END wq_m[193]
  PIN wq_m[194]
    DIRECTION OUTPUT ;
    USE SIGNAL ;
    PORT
      LAYER M4 ;
        RECT  0 36.72 0.084 36.744 ;
    END
  END wq_m[194]
  PIN wq_m[195]
    DIRECTION OUTPUT ;
    USE SIGNAL ;
    PORT
      LAYER M4 ;
        RECT  0 36.816 0.084 36.84 ;
    END
  END wq_m[195]
  PIN wq_m[196]
    DIRECTION OUTPUT ;
    USE SIGNAL ;
    PORT
      LAYER M4 ;
        RECT  0 36.912 0.084 36.936 ;
    END
  END wq_m[196]
  PIN wq_m[197]
    DIRECTION OUTPUT ;
    USE SIGNAL ;
    PORT
      LAYER M4 ;
        RECT  0 37.008 0.084 37.032 ;
    END
  END wq_m[197]
  PIN wq_m[198]
    DIRECTION OUTPUT ;
    USE SIGNAL ;
    PORT
      LAYER M4 ;
        RECT  0 37.104 0.084 37.128 ;
    END
  END wq_m[198]
  PIN wq_m[199]
    DIRECTION OUTPUT ;
    USE SIGNAL ;
    PORT
      LAYER M4 ;
        RECT  0 37.2 0.084 37.224 ;
    END
  END wq_m[199]
  PIN wq_m[19]
    DIRECTION OUTPUT ;
    USE SIGNAL ;
    PORT
      LAYER M4 ;
        RECT  0 26.064 0.084 26.088 ;
    END
  END wq_m[19]
  PIN wq_m[1]
    DIRECTION OUTPUT ;
    USE SIGNAL ;
    PORT
      LAYER M4 ;
        RECT  0 24.336 0.084 24.36 ;
    END
  END wq_m[1]
  PIN wq_m[200]
    DIRECTION OUTPUT ;
    USE SIGNAL ;
    PORT
      LAYER M4 ;
        RECT  0 37.296 0.084 37.32 ;
    END
  END wq_m[200]
  PIN wq_m[201]
    DIRECTION OUTPUT ;
    USE SIGNAL ;
    PORT
      LAYER M4 ;
        RECT  0 37.392 0.084 37.416 ;
    END
  END wq_m[201]
  PIN wq_m[202]
    DIRECTION OUTPUT ;
    USE SIGNAL ;
    PORT
      LAYER M4 ;
        RECT  0 37.488 0.084 37.512 ;
    END
  END wq_m[202]
  PIN wq_m[203]
    DIRECTION OUTPUT ;
    USE SIGNAL ;
    PORT
      LAYER M4 ;
        RECT  0 37.584 0.084 37.608 ;
    END
  END wq_m[203]
  PIN wq_m[204]
    DIRECTION OUTPUT ;
    USE SIGNAL ;
    PORT
      LAYER M4 ;
        RECT  0 37.68 0.084 37.704 ;
    END
  END wq_m[204]
  PIN wq_m[205]
    DIRECTION OUTPUT ;
    USE SIGNAL ;
    PORT
      LAYER M4 ;
        RECT  0 37.776 0.084 37.8 ;
    END
  END wq_m[205]
  PIN wq_m[206]
    DIRECTION OUTPUT ;
    USE SIGNAL ;
    PORT
      LAYER M4 ;
        RECT  0 37.872 0.084 37.896 ;
    END
  END wq_m[206]
  PIN wq_m[207]
    DIRECTION OUTPUT ;
    USE SIGNAL ;
    PORT
      LAYER M4 ;
        RECT  0 37.968 0.084 37.992 ;
    END
  END wq_m[207]
  PIN wq_m[208]
    DIRECTION OUTPUT ;
    USE SIGNAL ;
    PORT
      LAYER M4 ;
        RECT  0 38.064 0.084 38.088 ;
    END
  END wq_m[208]
  PIN wq_m[209]
    DIRECTION OUTPUT ;
    USE SIGNAL ;
    PORT
      LAYER M4 ;
        RECT  0 38.16 0.084 38.184 ;
    END
  END wq_m[209]
  PIN wq_m[20]
    DIRECTION OUTPUT ;
    USE SIGNAL ;
    PORT
      LAYER M4 ;
        RECT  0 26.16 0.084 26.184 ;
    END
  END wq_m[20]
  PIN wq_m[210]
    DIRECTION OUTPUT ;
    USE SIGNAL ;
    PORT
      LAYER M4 ;
        RECT  0 38.256 0.084 38.28 ;
    END
  END wq_m[210]
  PIN wq_m[211]
    DIRECTION OUTPUT ;
    USE SIGNAL ;
    PORT
      LAYER M4 ;
        RECT  0 38.352 0.084 38.376 ;
    END
  END wq_m[211]
  PIN wq_m[212]
    DIRECTION OUTPUT ;
    USE SIGNAL ;
    PORT
      LAYER M4 ;
        RECT  0 38.448 0.084 38.472 ;
    END
  END wq_m[212]
  PIN wq_m[213]
    DIRECTION OUTPUT ;
    USE SIGNAL ;
    PORT
      LAYER M4 ;
        RECT  0 38.544 0.084 38.568 ;
    END
  END wq_m[213]
  PIN wq_m[214]
    DIRECTION OUTPUT ;
    USE SIGNAL ;
    PORT
      LAYER M4 ;
        RECT  0 38.64 0.084 38.664 ;
    END
  END wq_m[214]
  PIN wq_m[215]
    DIRECTION OUTPUT ;
    USE SIGNAL ;
    PORT
      LAYER M4 ;
        RECT  0 38.736 0.084 38.76 ;
    END
  END wq_m[215]
  PIN wq_m[216]
    DIRECTION OUTPUT ;
    USE SIGNAL ;
    PORT
      LAYER M4 ;
        RECT  0 38.832 0.084 38.856 ;
    END
  END wq_m[216]
  PIN wq_m[217]
    DIRECTION OUTPUT ;
    USE SIGNAL ;
    PORT
      LAYER M4 ;
        RECT  0 38.928 0.084 38.952 ;
    END
  END wq_m[217]
  PIN wq_m[218]
    DIRECTION OUTPUT ;
    USE SIGNAL ;
    PORT
      LAYER M4 ;
        RECT  0 39.024 0.084 39.048 ;
    END
  END wq_m[218]
  PIN wq_m[219]
    DIRECTION OUTPUT ;
    USE SIGNAL ;
    PORT
      LAYER M4 ;
        RECT  0 39.12 0.084 39.144 ;
    END
  END wq_m[219]
  PIN wq_m[21]
    DIRECTION OUTPUT ;
    USE SIGNAL ;
    PORT
      LAYER M4 ;
        RECT  0 26.256 0.084 26.28 ;
    END
  END wq_m[21]
  PIN wq_m[220]
    DIRECTION OUTPUT ;
    USE SIGNAL ;
    PORT
      LAYER M4 ;
        RECT  0 39.216 0.084 39.24 ;
    END
  END wq_m[220]
  PIN wq_m[221]
    DIRECTION OUTPUT ;
    USE SIGNAL ;
    PORT
      LAYER M4 ;
        RECT  0 39.312 0.084 39.336 ;
    END
  END wq_m[221]
  PIN wq_m[222]
    DIRECTION OUTPUT ;
    USE SIGNAL ;
    PORT
      LAYER M4 ;
        RECT  0 39.408 0.084 39.432 ;
    END
  END wq_m[222]
  PIN wq_m[223]
    DIRECTION OUTPUT ;
    USE SIGNAL ;
    PORT
      LAYER M4 ;
        RECT  0 40.272 0.084 40.296 ;
    END
  END wq_m[223]
  PIN wq_m[224]
    DIRECTION OUTPUT ;
    USE SIGNAL ;
    PORT
      LAYER M4 ;
        RECT  0 40.368 0.084 40.392 ;
    END
  END wq_m[224]
  PIN wq_m[225]
    DIRECTION OUTPUT ;
    USE SIGNAL ;
    PORT
      LAYER M4 ;
        RECT  0 40.464 0.084 40.488 ;
    END
  END wq_m[225]
  PIN wq_m[226]
    DIRECTION OUTPUT ;
    USE SIGNAL ;
    PORT
      LAYER M4 ;
        RECT  0 40.56 0.084 40.584 ;
    END
  END wq_m[226]
  PIN wq_m[227]
    DIRECTION OUTPUT ;
    USE SIGNAL ;
    PORT
      LAYER M4 ;
        RECT  0 40.656 0.084 40.68 ;
    END
  END wq_m[227]
  PIN wq_m[228]
    DIRECTION OUTPUT ;
    USE SIGNAL ;
    PORT
      LAYER M4 ;
        RECT  0 40.752 0.084 40.776 ;
    END
  END wq_m[228]
  PIN wq_m[229]
    DIRECTION OUTPUT ;
    USE SIGNAL ;
    PORT
      LAYER M4 ;
        RECT  0 40.848 0.084 40.872 ;
    END
  END wq_m[229]
  PIN wq_m[22]
    DIRECTION OUTPUT ;
    USE SIGNAL ;
    PORT
      LAYER M4 ;
        RECT  0 26.352 0.084 26.376 ;
    END
  END wq_m[22]
  PIN wq_m[230]
    DIRECTION OUTPUT ;
    USE SIGNAL ;
    PORT
      LAYER M4 ;
        RECT  0 40.944 0.084 40.968 ;
    END
  END wq_m[230]
  PIN wq_m[231]
    DIRECTION OUTPUT ;
    USE SIGNAL ;
    PORT
      LAYER M4 ;
        RECT  0 41.04 0.084 41.064 ;
    END
  END wq_m[231]
  PIN wq_m[232]
    DIRECTION OUTPUT ;
    USE SIGNAL ;
    PORT
      LAYER M4 ;
        RECT  0 41.136 0.084 41.16 ;
    END
  END wq_m[232]
  PIN wq_m[233]
    DIRECTION OUTPUT ;
    USE SIGNAL ;
    PORT
      LAYER M4 ;
        RECT  0 41.232 0.084 41.256 ;
    END
  END wq_m[233]
  PIN wq_m[234]
    DIRECTION OUTPUT ;
    USE SIGNAL ;
    PORT
      LAYER M4 ;
        RECT  0 41.328 0.084 41.352 ;
    END
  END wq_m[234]
  PIN wq_m[235]
    DIRECTION OUTPUT ;
    USE SIGNAL ;
    PORT
      LAYER M4 ;
        RECT  0 41.424 0.084 41.448 ;
    END
  END wq_m[235]
  PIN wq_m[236]
    DIRECTION OUTPUT ;
    USE SIGNAL ;
    PORT
      LAYER M4 ;
        RECT  0 41.52 0.084 41.544 ;
    END
  END wq_m[236]
  PIN wq_m[237]
    DIRECTION OUTPUT ;
    USE SIGNAL ;
    PORT
      LAYER M4 ;
        RECT  0 41.616 0.084 41.64 ;
    END
  END wq_m[237]
  PIN wq_m[238]
    DIRECTION OUTPUT ;
    USE SIGNAL ;
    PORT
      LAYER M4 ;
        RECT  0 41.712 0.084 41.736 ;
    END
  END wq_m[238]
  PIN wq_m[239]
    DIRECTION OUTPUT ;
    USE SIGNAL ;
    PORT
      LAYER M4 ;
        RECT  0 41.808 0.084 41.832 ;
    END
  END wq_m[239]
  PIN wq_m[23]
    DIRECTION OUTPUT ;
    USE SIGNAL ;
    PORT
      LAYER M4 ;
        RECT  0 26.448 0.084 26.472 ;
    END
  END wq_m[23]
  PIN wq_m[240]
    DIRECTION OUTPUT ;
    USE SIGNAL ;
    PORT
      LAYER M4 ;
        RECT  0 41.904 0.084 41.928 ;
    END
  END wq_m[240]
  PIN wq_m[241]
    DIRECTION OUTPUT ;
    USE SIGNAL ;
    PORT
      LAYER M4 ;
        RECT  0 42 0.084 42.024 ;
    END
  END wq_m[241]
  PIN wq_m[242]
    DIRECTION OUTPUT ;
    USE SIGNAL ;
    PORT
      LAYER M4 ;
        RECT  0 42.096 0.084 42.12 ;
    END
  END wq_m[242]
  PIN wq_m[243]
    DIRECTION OUTPUT ;
    USE SIGNAL ;
    PORT
      LAYER M4 ;
        RECT  0 42.192 0.084 42.216 ;
    END
  END wq_m[243]
  PIN wq_m[244]
    DIRECTION OUTPUT ;
    USE SIGNAL ;
    PORT
      LAYER M4 ;
        RECT  0 42.288 0.084 42.312 ;
    END
  END wq_m[244]
  PIN wq_m[245]
    DIRECTION OUTPUT ;
    USE SIGNAL ;
    PORT
      LAYER M4 ;
        RECT  0 42.384 0.084 42.408 ;
    END
  END wq_m[245]
  PIN wq_m[246]
    DIRECTION OUTPUT ;
    USE SIGNAL ;
    PORT
      LAYER M4 ;
        RECT  0 42.48 0.084 42.504 ;
    END
  END wq_m[246]
  PIN wq_m[247]
    DIRECTION OUTPUT ;
    USE SIGNAL ;
    PORT
      LAYER M4 ;
        RECT  0 42.576 0.084 42.6 ;
    END
  END wq_m[247]
  PIN wq_m[248]
    DIRECTION OUTPUT ;
    USE SIGNAL ;
    PORT
      LAYER M4 ;
        RECT  0 42.672 0.084 42.696 ;
    END
  END wq_m[248]
  PIN wq_m[249]
    DIRECTION OUTPUT ;
    USE SIGNAL ;
    PORT
      LAYER M4 ;
        RECT  0 42.768 0.084 42.792 ;
    END
  END wq_m[249]
  PIN wq_m[24]
    DIRECTION OUTPUT ;
    USE SIGNAL ;
    PORT
      LAYER M4 ;
        RECT  0 26.544 0.084 26.568 ;
    END
  END wq_m[24]
  PIN wq_m[250]
    DIRECTION OUTPUT ;
    USE SIGNAL ;
    PORT
      LAYER M4 ;
        RECT  0 42.864 0.084 42.888 ;
    END
  END wq_m[250]
  PIN wq_m[251]
    DIRECTION OUTPUT ;
    USE SIGNAL ;
    PORT
      LAYER M4 ;
        RECT  0 42.96 0.084 42.984 ;
    END
  END wq_m[251]
  PIN wq_m[252]
    DIRECTION OUTPUT ;
    USE SIGNAL ;
    PORT
      LAYER M4 ;
        RECT  0 43.056 0.084 43.08 ;
    END
  END wq_m[252]
  PIN wq_m[253]
    DIRECTION OUTPUT ;
    USE SIGNAL ;
    PORT
      LAYER M4 ;
        RECT  0 43.152 0.084 43.176 ;
    END
  END wq_m[253]
  PIN wq_m[254]
    DIRECTION OUTPUT ;
    USE SIGNAL ;
    PORT
      LAYER M4 ;
        RECT  0 43.248 0.084 43.272 ;
    END
  END wq_m[254]
  PIN wq_m[255]
    DIRECTION OUTPUT ;
    USE SIGNAL ;
    PORT
      LAYER M4 ;
        RECT  0 33.936 0.084 33.96 ;
    END
  END wq_m[255]
  PIN wq_m[256]
    DIRECTION OUTPUT ;
    USE SIGNAL ;
    PORT
      LAYER M4 ;
        RECT  0 34.032 0.084 34.056 ;
    END
  END wq_m[256]
  PIN wq_m[257]
    DIRECTION OUTPUT ;
    USE SIGNAL ;
    PORT
      LAYER M4 ;
        RECT  0 34.128 0.084 34.152 ;
    END
  END wq_m[257]
  PIN wq_m[258]
    DIRECTION OUTPUT ;
    USE SIGNAL ;
    PORT
      LAYER M4 ;
        RECT  0 34.224 0.084 34.248 ;
    END
  END wq_m[258]
  PIN wq_m[259]
    DIRECTION OUTPUT ;
    USE SIGNAL ;
    PORT
      LAYER M4 ;
        RECT  0 34.32 0.084 34.344 ;
    END
  END wq_m[259]
  PIN wq_m[25]
    DIRECTION OUTPUT ;
    USE SIGNAL ;
    PORT
      LAYER M4 ;
        RECT  0 26.64 0.084 26.664 ;
    END
  END wq_m[25]
  PIN wq_m[260]
    DIRECTION OUTPUT ;
    USE SIGNAL ;
    PORT
      LAYER M4 ;
        RECT  0 34.416 0.084 34.44 ;
    END
  END wq_m[260]
  PIN wq_m[261]
    DIRECTION OUTPUT ;
    USE SIGNAL ;
    PORT
      LAYER M4 ;
        RECT  0 34.512 0.084 34.536 ;
    END
  END wq_m[261]
  PIN wq_m[262]
    DIRECTION OUTPUT ;
    USE SIGNAL ;
    PORT
      LAYER M4 ;
        RECT  0 34.608 0.084 34.632 ;
    END
  END wq_m[262]
  PIN wq_m[263]
    DIRECTION OUTPUT ;
    USE SIGNAL ;
    PORT
      LAYER M4 ;
        RECT  0 34.704 0.084 34.728 ;
    END
  END wq_m[263]
  PIN wq_m[264]
    DIRECTION OUTPUT ;
    USE SIGNAL ;
    PORT
      LAYER M4 ;
        RECT  0 34.8 0.084 34.824 ;
    END
  END wq_m[264]
  PIN wq_m[265]
    DIRECTION OUTPUT ;
    USE SIGNAL ;
    PORT
      LAYER M4 ;
        RECT  0 34.896 0.084 34.92 ;
    END
  END wq_m[265]
  PIN wq_m[266]
    DIRECTION OUTPUT ;
    USE SIGNAL ;
    PORT
      LAYER M4 ;
        RECT  0 34.992 0.084 35.016 ;
    END
  END wq_m[266]
  PIN wq_m[267]
    DIRECTION OUTPUT ;
    USE SIGNAL ;
    PORT
      LAYER M4 ;
        RECT  0 35.088 0.084 35.112 ;
    END
  END wq_m[267]
  PIN wq_m[268]
    DIRECTION OUTPUT ;
    USE SIGNAL ;
    PORT
      LAYER M4 ;
        RECT  0 35.184 0.084 35.208 ;
    END
  END wq_m[268]
  PIN wq_m[269]
    DIRECTION OUTPUT ;
    USE SIGNAL ;
    PORT
      LAYER M4 ;
        RECT  0 35.28 0.084 35.304 ;
    END
  END wq_m[269]
  PIN wq_m[26]
    DIRECTION OUTPUT ;
    USE SIGNAL ;
    PORT
      LAYER M4 ;
        RECT  0 26.736 0.084 26.76 ;
    END
  END wq_m[26]
  PIN wq_m[270]
    DIRECTION OUTPUT ;
    USE SIGNAL ;
    PORT
      LAYER M4 ;
        RECT  0 35.376 0.084 35.4 ;
    END
  END wq_m[270]
  PIN wq_m[271]
    DIRECTION OUTPUT ;
    USE SIGNAL ;
    PORT
      LAYER M4 ;
        RECT  0 35.472 0.084 35.496 ;
    END
  END wq_m[271]
  PIN wq_m[272]
    DIRECTION OUTPUT ;
    USE SIGNAL ;
    PORT
      LAYER M4 ;
        RECT  0 35.568 0.084 35.592 ;
    END
  END wq_m[272]
  PIN wq_m[273]
    DIRECTION OUTPUT ;
    USE SIGNAL ;
    PORT
      LAYER M4 ;
        RECT  0 35.664 0.084 35.688 ;
    END
  END wq_m[273]
  PIN wq_m[274]
    DIRECTION OUTPUT ;
    USE SIGNAL ;
    PORT
      LAYER M4 ;
        RECT  0 35.76 0.084 35.784 ;
    END
  END wq_m[274]
  PIN wq_m[275]
    DIRECTION OUTPUT ;
    USE SIGNAL ;
    PORT
      LAYER M4 ;
        RECT  0 35.856 0.084 35.88 ;
    END
  END wq_m[275]
  PIN wq_m[276]
    DIRECTION OUTPUT ;
    USE SIGNAL ;
    PORT
      LAYER M4 ;
        RECT  0 35.952 0.084 35.976 ;
    END
  END wq_m[276]
  PIN wq_m[277]
    DIRECTION OUTPUT ;
    USE SIGNAL ;
    PORT
      LAYER M4 ;
        RECT  0 36.048 0.084 36.072 ;
    END
  END wq_m[277]
  PIN wq_m[278]
    DIRECTION OUTPUT ;
    USE SIGNAL ;
    PORT
      LAYER M4 ;
        RECT  0 36.144 0.084 36.168 ;
    END
  END wq_m[278]
  PIN wq_m[279]
    DIRECTION OUTPUT ;
    USE SIGNAL ;
    PORT
      LAYER M4 ;
        RECT  0 36.24 0.084 36.264 ;
    END
  END wq_m[279]
  PIN wq_m[27]
    DIRECTION OUTPUT ;
    USE SIGNAL ;
    PORT
      LAYER M4 ;
        RECT  0 26.832 0.084 26.856 ;
    END
  END wq_m[27]
  PIN wq_m[280]
    DIRECTION OUTPUT ;
    USE SIGNAL ;
    PORT
      LAYER M4 ;
        RECT  0 36.336 0.084 36.36 ;
    END
  END wq_m[280]
  PIN wq_m[28]
    DIRECTION OUTPUT ;
    USE SIGNAL ;
    PORT
      LAYER M4 ;
        RECT  0 26.928 0.084 26.952 ;
    END
  END wq_m[28]
  PIN wq_m[29]
    DIRECTION OUTPUT ;
    USE SIGNAL ;
    PORT
      LAYER M4 ;
        RECT  0 27.024 0.084 27.048 ;
    END
  END wq_m[29]
  PIN wq_m[2]
    DIRECTION OUTPUT ;
    USE SIGNAL ;
    PORT
      LAYER M4 ;
        RECT  0 24.432 0.084 24.456 ;
    END
  END wq_m[2]
  PIN wq_m[30]
    DIRECTION OUTPUT ;
    USE SIGNAL ;
    PORT
      LAYER M4 ;
        RECT  0 27.12 0.084 27.144 ;
    END
  END wq_m[30]
  PIN wq_m[31]
    DIRECTION OUTPUT ;
    USE SIGNAL ;
    PORT
      LAYER M4 ;
        RECT  0 14.16 0.084 14.184 ;
    END
  END wq_m[31]
  PIN wq_m[32]
    DIRECTION OUTPUT ;
    USE SIGNAL ;
    PORT
      LAYER M4 ;
        RECT  0 14.256 0.084 14.28 ;
    END
  END wq_m[32]
  PIN wq_m[33]
    DIRECTION OUTPUT ;
    USE SIGNAL ;
    PORT
      LAYER M4 ;
        RECT  0 14.352 0.084 14.376 ;
    END
  END wq_m[33]
  PIN wq_m[34]
    DIRECTION OUTPUT ;
    USE SIGNAL ;
    PORT
      LAYER M4 ;
        RECT  0 14.448 0.084 14.472 ;
    END
  END wq_m[34]
  PIN wq_m[35]
    DIRECTION OUTPUT ;
    USE SIGNAL ;
    PORT
      LAYER M4 ;
        RECT  0 14.544 0.084 14.568 ;
    END
  END wq_m[35]
  PIN wq_m[36]
    DIRECTION OUTPUT ;
    USE SIGNAL ;
    PORT
      LAYER M4 ;
        RECT  0 14.64 0.084 14.664 ;
    END
  END wq_m[36]
  PIN wq_m[37]
    DIRECTION OUTPUT ;
    USE SIGNAL ;
    PORT
      LAYER M4 ;
        RECT  0 14.736 0.084 14.76 ;
    END
  END wq_m[37]
  PIN wq_m[38]
    DIRECTION OUTPUT ;
    USE SIGNAL ;
    PORT
      LAYER M4 ;
        RECT  0 14.832 0.084 14.856 ;
    END
  END wq_m[38]
  PIN wq_m[39]
    DIRECTION OUTPUT ;
    USE SIGNAL ;
    PORT
      LAYER M4 ;
        RECT  0 14.928 0.084 14.952 ;
    END
  END wq_m[39]
  PIN wq_m[3]
    DIRECTION OUTPUT ;
    USE SIGNAL ;
    PORT
      LAYER M4 ;
        RECT  0 24.528 0.084 24.552 ;
    END
  END wq_m[3]
  PIN wq_m[40]
    DIRECTION OUTPUT ;
    USE SIGNAL ;
    PORT
      LAYER M4 ;
        RECT  0 15.024 0.084 15.048 ;
    END
  END wq_m[40]
  PIN wq_m[41]
    DIRECTION OUTPUT ;
    USE SIGNAL ;
    PORT
      LAYER M4 ;
        RECT  0 15.12 0.084 15.144 ;
    END
  END wq_m[41]
  PIN wq_m[42]
    DIRECTION OUTPUT ;
    USE SIGNAL ;
    PORT
      LAYER M4 ;
        RECT  0 15.216 0.084 15.24 ;
    END
  END wq_m[42]
  PIN wq_m[43]
    DIRECTION OUTPUT ;
    USE SIGNAL ;
    PORT
      LAYER M4 ;
        RECT  0 15.312 0.084 15.336 ;
    END
  END wq_m[43]
  PIN wq_m[44]
    DIRECTION OUTPUT ;
    USE SIGNAL ;
    PORT
      LAYER M4 ;
        RECT  0 15.408 0.084 15.432 ;
    END
  END wq_m[44]
  PIN wq_m[45]
    DIRECTION OUTPUT ;
    USE SIGNAL ;
    PORT
      LAYER M4 ;
        RECT  0 15.504 0.084 15.528 ;
    END
  END wq_m[45]
  PIN wq_m[46]
    DIRECTION OUTPUT ;
    USE SIGNAL ;
    PORT
      LAYER M4 ;
        RECT  0 15.6 0.084 15.624 ;
    END
  END wq_m[46]
  PIN wq_m[47]
    DIRECTION OUTPUT ;
    USE SIGNAL ;
    PORT
      LAYER M4 ;
        RECT  0 15.696 0.084 15.72 ;
    END
  END wq_m[47]
  PIN wq_m[48]
    DIRECTION OUTPUT ;
    USE SIGNAL ;
    PORT
      LAYER M4 ;
        RECT  0 15.792 0.084 15.816 ;
    END
  END wq_m[48]
  PIN wq_m[49]
    DIRECTION OUTPUT ;
    USE SIGNAL ;
    PORT
      LAYER M4 ;
        RECT  0 15.888 0.084 15.912 ;
    END
  END wq_m[49]
  PIN wq_m[4]
    DIRECTION OUTPUT ;
    USE SIGNAL ;
    PORT
      LAYER M4 ;
        RECT  0 24.624 0.084 24.648 ;
    END
  END wq_m[4]
  PIN wq_m[50]
    DIRECTION OUTPUT ;
    USE SIGNAL ;
    PORT
      LAYER M4 ;
        RECT  0 15.984 0.084 16.008 ;
    END
  END wq_m[50]
  PIN wq_m[51]
    DIRECTION OUTPUT ;
    USE SIGNAL ;
    PORT
      LAYER M4 ;
        RECT  0 16.08 0.084 16.104 ;
    END
  END wq_m[51]
  PIN wq_m[52]
    DIRECTION OUTPUT ;
    USE SIGNAL ;
    PORT
      LAYER M4 ;
        RECT  0 16.176 0.084 16.2 ;
    END
  END wq_m[52]
  PIN wq_m[53]
    DIRECTION OUTPUT ;
    USE SIGNAL ;
    PORT
      LAYER M4 ;
        RECT  0 16.272 0.084 16.296 ;
    END
  END wq_m[53]
  PIN wq_m[54]
    DIRECTION OUTPUT ;
    USE SIGNAL ;
    PORT
      LAYER M4 ;
        RECT  0 16.368 0.084 16.392 ;
    END
  END wq_m[54]
  PIN wq_m[55]
    DIRECTION OUTPUT ;
    USE SIGNAL ;
    PORT
      LAYER M4 ;
        RECT  0 16.464 0.084 16.488 ;
    END
  END wq_m[55]
  PIN wq_m[56]
    DIRECTION OUTPUT ;
    USE SIGNAL ;
    PORT
      LAYER M4 ;
        RECT  0 16.56 0.084 16.584 ;
    END
  END wq_m[56]
  PIN wq_m[57]
    DIRECTION OUTPUT ;
    USE SIGNAL ;
    PORT
      LAYER M4 ;
        RECT  0 16.656 0.084 16.68 ;
    END
  END wq_m[57]
  PIN wq_m[58]
    DIRECTION OUTPUT ;
    USE SIGNAL ;
    PORT
      LAYER M4 ;
        RECT  0 16.752 0.084 16.776 ;
    END
  END wq_m[58]
  PIN wq_m[59]
    DIRECTION OUTPUT ;
    USE SIGNAL ;
    PORT
      LAYER M4 ;
        RECT  0 16.848 0.084 16.872 ;
    END
  END wq_m[59]
  PIN wq_m[5]
    DIRECTION OUTPUT ;
    USE SIGNAL ;
    PORT
      LAYER M4 ;
        RECT  0 24.72 0.084 24.744 ;
    END
  END wq_m[5]
  PIN wq_m[60]
    DIRECTION OUTPUT ;
    USE SIGNAL ;
    PORT
      LAYER M4 ;
        RECT  0 16.944 0.084 16.968 ;
    END
  END wq_m[60]
  PIN wq_m[61]
    DIRECTION OUTPUT ;
    USE SIGNAL ;
    PORT
      LAYER M4 ;
        RECT  0 17.04 0.084 17.064 ;
    END
  END wq_m[61]
  PIN wq_m[62]
    DIRECTION OUTPUT ;
    USE SIGNAL ;
    PORT
      LAYER M4 ;
        RECT  0 17.136 0.084 17.16 ;
    END
  END wq_m[62]
  PIN wq_m[63]
    DIRECTION OUTPUT ;
    USE SIGNAL ;
    PORT
      LAYER M4 ;
        RECT  0 17.232 0.084 17.256 ;
    END
  END wq_m[63]
  PIN wq_m[64]
    DIRECTION OUTPUT ;
    USE SIGNAL ;
    PORT
      LAYER M4 ;
        RECT  0 17.328 0.084 17.352 ;
    END
  END wq_m[64]
  PIN wq_m[65]
    DIRECTION OUTPUT ;
    USE SIGNAL ;
    PORT
      LAYER M4 ;
        RECT  0 17.424 0.084 17.448 ;
    END
  END wq_m[65]
  PIN wq_m[66]
    DIRECTION OUTPUT ;
    USE SIGNAL ;
    PORT
      LAYER M4 ;
        RECT  0 17.52 0.084 17.544 ;
    END
  END wq_m[66]
  PIN wq_m[67]
    DIRECTION OUTPUT ;
    USE SIGNAL ;
    PORT
      LAYER M4 ;
        RECT  0 17.616 0.084 17.64 ;
    END
  END wq_m[67]
  PIN wq_m[68]
    DIRECTION OUTPUT ;
    USE SIGNAL ;
    PORT
      LAYER M4 ;
        RECT  0 17.712 0.084 17.736 ;
    END
  END wq_m[68]
  PIN wq_m[69]
    DIRECTION OUTPUT ;
    USE SIGNAL ;
    PORT
      LAYER M4 ;
        RECT  0 17.808 0.084 17.832 ;
    END
  END wq_m[69]
  PIN wq_m[6]
    DIRECTION OUTPUT ;
    USE SIGNAL ;
    PORT
      LAYER M4 ;
        RECT  0 24.816 0.084 24.84 ;
    END
  END wq_m[6]
  PIN wq_m[70]
    DIRECTION OUTPUT ;
    USE SIGNAL ;
    PORT
      LAYER M4 ;
        RECT  0 17.904 0.084 17.928 ;
    END
  END wq_m[70]
  PIN wq_m[71]
    DIRECTION OUTPUT ;
    USE SIGNAL ;
    PORT
      LAYER M4 ;
        RECT  0 18 0.084 18.024 ;
    END
  END wq_m[71]
  PIN wq_m[72]
    DIRECTION OUTPUT ;
    USE SIGNAL ;
    PORT
      LAYER M4 ;
        RECT  0 18.096 0.084 18.12 ;
    END
  END wq_m[72]
  PIN wq_m[73]
    DIRECTION OUTPUT ;
    USE SIGNAL ;
    PORT
      LAYER M4 ;
        RECT  0 18.192 0.084 18.216 ;
    END
  END wq_m[73]
  PIN wq_m[74]
    DIRECTION OUTPUT ;
    USE SIGNAL ;
    PORT
      LAYER M4 ;
        RECT  0 18.288 0.084 18.312 ;
    END
  END wq_m[74]
  PIN wq_m[75]
    DIRECTION OUTPUT ;
    USE SIGNAL ;
    PORT
      LAYER M4 ;
        RECT  0 18.384 0.084 18.408 ;
    END
  END wq_m[75]
  PIN wq_m[76]
    DIRECTION OUTPUT ;
    USE SIGNAL ;
    PORT
      LAYER M4 ;
        RECT  0 18.48 0.084 18.504 ;
    END
  END wq_m[76]
  PIN wq_m[77]
    DIRECTION OUTPUT ;
    USE SIGNAL ;
    PORT
      LAYER M4 ;
        RECT  0 18.576 0.084 18.6 ;
    END
  END wq_m[77]
  PIN wq_m[78]
    DIRECTION OUTPUT ;
    USE SIGNAL ;
    PORT
      LAYER M4 ;
        RECT  0 18.672 0.084 18.696 ;
    END
  END wq_m[78]
  PIN wq_m[79]
    DIRECTION OUTPUT ;
    USE SIGNAL ;
    PORT
      LAYER M4 ;
        RECT  0 18.768 0.084 18.792 ;
    END
  END wq_m[79]
  PIN wq_m[7]
    DIRECTION OUTPUT ;
    USE SIGNAL ;
    PORT
      LAYER M4 ;
        RECT  0 24.912 0.084 24.936 ;
    END
  END wq_m[7]
  PIN wq_m[80]
    DIRECTION OUTPUT ;
    USE SIGNAL ;
    PORT
      LAYER M4 ;
        RECT  0 18.864 0.084 18.888 ;
    END
  END wq_m[80]
  PIN wq_m[81]
    DIRECTION OUTPUT ;
    USE SIGNAL ;
    PORT
      LAYER M4 ;
        RECT  0 18.96 0.084 18.984 ;
    END
  END wq_m[81]
  PIN wq_m[82]
    DIRECTION OUTPUT ;
    USE SIGNAL ;
    PORT
      LAYER M4 ;
        RECT  0 19.056 0.084 19.08 ;
    END
  END wq_m[82]
  PIN wq_m[83]
    DIRECTION OUTPUT ;
    USE SIGNAL ;
    PORT
      LAYER M4 ;
        RECT  0 19.152 0.084 19.176 ;
    END
  END wq_m[83]
  PIN wq_m[84]
    DIRECTION OUTPUT ;
    USE SIGNAL ;
    PORT
      LAYER M4 ;
        RECT  0 19.248 0.084 19.272 ;
    END
  END wq_m[84]
  PIN wq_m[85]
    DIRECTION OUTPUT ;
    USE SIGNAL ;
    PORT
      LAYER M4 ;
        RECT  0 19.344 0.084 19.368 ;
    END
  END wq_m[85]
  PIN wq_m[86]
    DIRECTION OUTPUT ;
    USE SIGNAL ;
    PORT
      LAYER M4 ;
        RECT  0 19.44 0.084 19.464 ;
    END
  END wq_m[86]
  PIN wq_m[87]
    DIRECTION OUTPUT ;
    USE SIGNAL ;
    PORT
      LAYER M4 ;
        RECT  0 19.536 0.084 19.56 ;
    END
  END wq_m[87]
  PIN wq_m[88]
    DIRECTION OUTPUT ;
    USE SIGNAL ;
    PORT
      LAYER M4 ;
        RECT  0 19.632 0.084 19.656 ;
    END
  END wq_m[88]
  PIN wq_m[89]
    DIRECTION OUTPUT ;
    USE SIGNAL ;
    PORT
      LAYER M4 ;
        RECT  0 19.728 0.084 19.752 ;
    END
  END wq_m[89]
  PIN wq_m[8]
    DIRECTION OUTPUT ;
    USE SIGNAL ;
    PORT
      LAYER M4 ;
        RECT  0 25.008 0.084 25.032 ;
    END
  END wq_m[8]
  PIN wq_m[90]
    DIRECTION OUTPUT ;
    USE SIGNAL ;
    PORT
      LAYER M4 ;
        RECT  0 19.824 0.084 19.848 ;
    END
  END wq_m[90]
  PIN wq_m[91]
    DIRECTION OUTPUT ;
    USE SIGNAL ;
    PORT
      LAYER M4 ;
        RECT  0 19.92 0.084 19.944 ;
    END
  END wq_m[91]
  PIN wq_m[92]
    DIRECTION OUTPUT ;
    USE SIGNAL ;
    PORT
      LAYER M4 ;
        RECT  0 20.016 0.084 20.04 ;
    END
  END wq_m[92]
  PIN wq_m[93]
    DIRECTION OUTPUT ;
    USE SIGNAL ;
    PORT
      LAYER M4 ;
        RECT  0 20.112 0.084 20.136 ;
    END
  END wq_m[93]
  PIN wq_m[94]
    DIRECTION OUTPUT ;
    USE SIGNAL ;
    PORT
      LAYER M4 ;
        RECT  0 20.208 0.084 20.232 ;
    END
  END wq_m[94]
  PIN wq_m[95]
    DIRECTION OUTPUT ;
    USE SIGNAL ;
    PORT
      LAYER M4 ;
        RECT  0 27.216 0.084 27.24 ;
    END
  END wq_m[95]
  PIN wq_m[96]
    DIRECTION OUTPUT ;
    USE SIGNAL ;
    PORT
      LAYER M4 ;
        RECT  0 27.312 0.084 27.336 ;
    END
  END wq_m[96]
  PIN wq_m[97]
    DIRECTION OUTPUT ;
    USE SIGNAL ;
    PORT
      LAYER M4 ;
        RECT  0 27.408 0.084 27.432 ;
    END
  END wq_m[97]
  PIN wq_m[98]
    DIRECTION OUTPUT ;
    USE SIGNAL ;
    PORT
      LAYER M4 ;
        RECT  0 27.504 0.084 27.528 ;
    END
  END wq_m[98]
  PIN wq_m[99]
    DIRECTION OUTPUT ;
    USE SIGNAL ;
    PORT
      LAYER M4 ;
        RECT  0 27.6 0.084 27.624 ;
    END
  END wq_m[99]
  PIN wq_m[9]
    DIRECTION OUTPUT ;
    USE SIGNAL ;
    PORT
      LAYER M4 ;
        RECT  0 25.104 0.084 25.128 ;
    END
  END wq_m[9]
  PIN VDD
    DIRECTION INOUT ;
    USE POWER ;
    PORT
      LAYER M5 ;
        RECT  56.592 2.151 56.712 57.249 ;
        RECT  51.192 2.151 51.312 57.249 ;
        RECT  45.792 2.151 45.912 57.249 ;
        RECT  40.392 2.151 40.512 57.249 ;
        RECT  34.992 2.151 35.112 57.249 ;
        RECT  29.592 2.151 29.712 57.249 ;
        RECT  24.192 2.151 24.312 57.249 ;
        RECT  18.792 2.151 18.912 57.249 ;
        RECT  13.392 2.151 13.512 57.249 ;
        RECT  7.992 2.151 8.112 57.249 ;
        RECT  2.592 2.151 2.712 57.249 ;
    END
  END VDD
  PIN VSS
    DIRECTION INOUT ;
    USE GROUND ;
    PORT
      LAYER M5 ;
        RECT  56.4 2.137 56.52 57.263 ;
        RECT  51 2.137 51.12 57.263 ;
        RECT  45.6 2.137 45.72 57.263 ;
        RECT  40.2 2.137 40.32 57.263 ;
        RECT  34.8 2.137 34.92 57.263 ;
        RECT  29.4 2.137 29.52 57.263 ;
        RECT  24 2.137 24.12 57.263 ;
        RECT  18.6 2.137 18.72 57.263 ;
        RECT  13.2 2.137 13.32 57.263 ;
        RECT  7.8 2.137 7.92 57.263 ;
        RECT  2.4 2.137 2.52 57.263 ;
    END
  END VSS
  OBS
    LAYER RVTN ;
     RECT  2.16 2.16 57.24 2.295 ;
     RECT  2.16 2.565 57.24 2.835 ;
     RECT  2.16 3.105 57.24 3.375 ;
     RECT  2.16 3.645 57.24 3.915 ;
     RECT  2.16 4.185 57.24 4.455 ;
     RECT  2.16 4.725 57.24 4.995 ;
     RECT  2.16 5.265 57.24 5.535 ;
     RECT  2.16 5.805 57.24 6.075 ;
     RECT  2.16 6.345 57.24 6.615 ;
     RECT  2.16 6.885 57.24 7.155 ;
     RECT  2.16 7.425 57.24 7.695 ;
     RECT  2.16 7.965 57.24 8.235 ;
     RECT  2.16 8.505 57.24 8.775 ;
     RECT  2.16 9.045 57.24 9.315 ;
     RECT  2.16 9.585 57.24 9.855 ;
     RECT  2.16 10.125 57.24 10.395 ;
     RECT  2.16 10.665 57.24 10.935 ;
     RECT  2.16 11.205 57.24 11.475 ;
     RECT  2.16 11.745 57.24 12.015 ;
     RECT  2.16 12.285 57.24 12.555 ;
     RECT  2.16 12.825 57.24 13.095 ;
     RECT  2.16 13.365 57.24 13.635 ;
     RECT  2.16 13.905 57.24 14.175 ;
     RECT  2.16 14.445 57.24 14.715 ;
     RECT  2.16 14.985 57.24 15.255 ;
     RECT  2.16 15.525 57.24 15.795 ;
     RECT  2.16 16.065 57.24 16.335 ;
     RECT  2.16 16.605 57.24 16.875 ;
     RECT  2.16 17.145 57.24 17.415 ;
     RECT  2.16 17.685 57.24 17.955 ;
     RECT  2.16 18.225 57.24 18.495 ;
     RECT  2.16 18.765 57.24 19.035 ;
     RECT  2.16 19.305 57.24 19.575 ;
     RECT  2.16 19.845 57.24 20.115 ;
     RECT  2.16 20.385 57.24 20.655 ;
     RECT  2.16 20.925 57.24 21.195 ;
     RECT  2.16 21.465 57.24 21.735 ;
     RECT  2.16 22.005 57.24 22.275 ;
     RECT  2.16 22.545 57.24 22.815 ;
     RECT  2.16 23.085 57.24 23.355 ;
     RECT  2.16 23.625 57.24 23.895 ;
     RECT  2.16 24.165 57.24 24.435 ;
     RECT  2.16 24.705 57.24 24.975 ;
     RECT  2.16 25.245 57.24 25.515 ;
     RECT  2.16 25.785 57.24 26.055 ;
     RECT  2.16 26.325 57.24 26.595 ;
     RECT  2.16 26.865 57.24 27.135 ;
     RECT  2.16 27.405 57.24 27.675 ;
     RECT  2.16 27.945 57.24 28.215 ;
     RECT  2.16 28.485 57.24 28.755 ;
     RECT  2.16 29.025 57.24 29.295 ;
     RECT  2.16 29.565 57.24 29.835 ;
     RECT  2.16 30.105 57.24 30.375 ;
     RECT  2.16 30.645 57.24 30.915 ;
     RECT  2.16 31.185 57.24 31.455 ;
     RECT  2.16 31.725 57.24 31.995 ;
     RECT  2.16 32.265 57.24 32.535 ;
     RECT  2.16 32.805 57.24 33.075 ;
     RECT  2.16 33.345 57.24 33.615 ;
     RECT  2.16 33.885 57.24 34.155 ;
     RECT  2.16 34.425 57.24 34.695 ;
     RECT  2.16 34.965 57.24 35.235 ;
     RECT  2.16 35.505 57.24 35.775 ;
     RECT  2.16 36.045 57.24 36.315 ;
     RECT  2.16 36.585 57.24 36.855 ;
     RECT  2.16 37.125 57.24 37.395 ;
     RECT  2.16 37.665 57.24 37.935 ;
     RECT  2.16 38.205 57.24 38.475 ;
     RECT  2.16 38.745 57.24 39.015 ;
     RECT  2.16 39.285 57.24 39.555 ;
     RECT  2.16 39.825 57.24 40.095 ;
     RECT  2.16 40.365 57.24 40.635 ;
     RECT  2.16 40.905 57.24 41.175 ;
     RECT  2.16 41.445 57.24 41.715 ;
     RECT  2.16 41.985 57.24 42.255 ;
     RECT  2.16 42.525 57.24 42.795 ;
     RECT  2.16 43.065 57.24 43.335 ;
     RECT  2.16 43.605 57.24 43.875 ;
     RECT  2.16 44.145 57.24 44.415 ;
     RECT  2.16 44.685 57.24 44.955 ;
     RECT  2.16 45.225 57.24 45.495 ;
     RECT  2.16 45.765 57.24 46.035 ;
     RECT  2.16 46.305 57.24 46.575 ;
     RECT  2.16 46.845 57.24 47.115 ;
     RECT  2.16 47.385 57.24 47.655 ;
     RECT  2.16 47.925 57.24 48.195 ;
     RECT  2.16 48.465 57.24 48.735 ;
     RECT  2.16 49.005 57.24 49.275 ;
     RECT  2.16 49.545 57.24 49.815 ;
     RECT  2.16 50.085 57.24 50.355 ;
     RECT  2.16 50.625 57.24 50.895 ;
     RECT  2.16 51.165 57.24 51.435 ;
     RECT  2.16 51.705 57.24 51.975 ;
     RECT  2.16 52.245 57.24 52.515 ;
     RECT  2.16 52.785 57.24 53.055 ;
     RECT  2.16 53.325 57.24 53.595 ;
     RECT  2.16 53.865 57.24 54.135 ;
     RECT  2.16 54.405 57.24 54.675 ;
     RECT  2.16 54.945 57.24 55.215 ;
     RECT  2.16 55.485 57.24 55.755 ;
     RECT  2.16 56.025 57.24 56.295 ;
     RECT  2.16 56.565 57.24 56.835 ;
     RECT  2.16 57.105 57.24 57.24 ;
    LAYER RVTP ;
     RECT  2.16 2.295 57.24 2.565 ;
     RECT  2.16 2.835 57.24 3.105 ;
     RECT  2.16 3.375 57.24 3.645 ;
     RECT  2.16 3.915 57.24 4.185 ;
     RECT  2.16 4.455 57.24 4.725 ;
     RECT  2.16 4.995 57.24 5.265 ;
     RECT  2.16 5.535 57.24 5.805 ;
     RECT  2.16 6.075 57.24 6.345 ;
     RECT  2.16 6.615 57.24 6.885 ;
     RECT  2.16 7.155 57.24 7.425 ;
     RECT  2.16 7.695 57.24 7.965 ;
     RECT  2.16 8.235 57.24 8.505 ;
     RECT  2.16 8.775 57.24 9.045 ;
     RECT  2.16 9.315 57.24 9.585 ;
     RECT  2.16 9.855 57.24 10.125 ;
     RECT  2.16 10.395 57.24 10.665 ;
     RECT  2.16 10.935 57.24 11.205 ;
     RECT  2.16 11.475 57.24 11.745 ;
     RECT  2.16 12.015 57.24 12.285 ;
     RECT  2.16 12.555 57.24 12.825 ;
     RECT  2.16 13.095 57.24 13.365 ;
     RECT  2.16 13.635 57.24 13.905 ;
     RECT  2.16 14.175 57.24 14.445 ;
     RECT  2.16 14.715 57.24 14.985 ;
     RECT  2.16 15.255 57.24 15.525 ;
     RECT  2.16 15.795 57.24 16.065 ;
     RECT  2.16 16.335 57.24 16.605 ;
     RECT  2.16 16.875 57.24 17.145 ;
     RECT  2.16 17.415 57.24 17.685 ;
     RECT  2.16 17.955 57.24 18.225 ;
     RECT  2.16 18.495 57.24 18.765 ;
     RECT  2.16 19.035 57.24 19.305 ;
     RECT  2.16 19.575 57.24 19.845 ;
     RECT  2.16 20.115 57.24 20.385 ;
     RECT  2.16 20.655 57.24 20.925 ;
     RECT  2.16 21.195 57.24 21.465 ;
     RECT  2.16 21.735 57.24 22.005 ;
     RECT  2.16 22.275 57.24 22.545 ;
     RECT  2.16 22.815 57.24 23.085 ;
     RECT  2.16 23.355 57.24 23.625 ;
     RECT  2.16 23.895 57.24 24.165 ;
     RECT  2.16 24.435 57.24 24.705 ;
     RECT  2.16 24.975 57.24 25.245 ;
     RECT  2.16 25.515 57.24 25.785 ;
     RECT  2.16 26.055 57.24 26.325 ;
     RECT  2.16 26.595 57.24 26.865 ;
     RECT  2.16 27.135 57.24 27.405 ;
     RECT  2.16 27.675 57.24 27.945 ;
     RECT  2.16 28.215 57.24 28.485 ;
     RECT  2.16 28.755 57.24 29.025 ;
     RECT  2.16 29.295 57.24 29.565 ;
     RECT  2.16 29.835 57.24 30.105 ;
     RECT  2.16 30.375 57.24 30.645 ;
     RECT  2.16 30.915 57.24 31.185 ;
     RECT  2.16 31.455 57.24 31.725 ;
     RECT  2.16 31.995 57.24 32.265 ;
     RECT  2.16 32.535 57.24 32.805 ;
     RECT  2.16 33.075 57.24 33.345 ;
     RECT  2.16 33.615 57.24 33.885 ;
     RECT  2.16 34.155 57.24 34.425 ;
     RECT  2.16 34.695 57.24 34.965 ;
     RECT  2.16 35.235 57.24 35.505 ;
     RECT  2.16 35.775 57.24 36.045 ;
     RECT  2.16 36.315 57.24 36.585 ;
     RECT  2.16 36.855 57.24 37.125 ;
     RECT  2.16 37.395 57.24 37.665 ;
     RECT  2.16 37.935 57.24 38.205 ;
     RECT  2.16 38.475 57.24 38.745 ;
     RECT  2.16 39.015 57.24 39.285 ;
     RECT  2.16 39.555 57.24 39.825 ;
     RECT  2.16 40.095 57.24 40.365 ;
     RECT  2.16 40.635 57.24 40.905 ;
     RECT  2.16 41.175 57.24 41.445 ;
     RECT  2.16 41.715 57.24 41.985 ;
     RECT  2.16 42.255 57.24 42.525 ;
     RECT  2.16 42.795 57.24 43.065 ;
     RECT  2.16 43.335 57.24 43.605 ;
     RECT  2.16 43.875 57.24 44.145 ;
     RECT  2.16 44.415 57.24 44.685 ;
     RECT  2.16 44.955 57.24 45.225 ;
     RECT  2.16 45.495 57.24 45.765 ;
     RECT  2.16 46.035 57.24 46.305 ;
     RECT  2.16 46.575 57.24 46.845 ;
     RECT  2.16 47.115 57.24 47.385 ;
     RECT  2.16 47.655 57.24 47.925 ;
     RECT  2.16 48.195 57.24 48.465 ;
     RECT  2.16 48.735 57.24 49.005 ;
     RECT  2.16 49.275 57.24 49.545 ;
     RECT  2.16 49.815 57.24 50.085 ;
     RECT  2.16 50.355 57.24 50.625 ;
     RECT  2.16 50.895 57.24 51.165 ;
     RECT  2.16 51.435 57.24 51.705 ;
     RECT  2.16 51.975 57.24 52.245 ;
     RECT  2.16 52.515 57.24 52.785 ;
     RECT  2.16 53.055 57.24 53.325 ;
     RECT  2.16 53.595 57.24 53.865 ;
     RECT  2.16 54.135 57.24 54.405 ;
     RECT  2.16 54.675 57.24 54.945 ;
     RECT  2.16 55.215 57.24 55.485 ;
     RECT  2.16 55.755 57.24 56.025 ;
     RECT  2.16 56.295 57.24 56.565 ;
     RECT  2.16 56.835 57.24 57.105 ;
    LAYER M1 ;
     RECT  2.16 2.151 57.24 57.249 ;
    LAYER M2 ;
     RECT  0.103 24.066 0.139 24.084 ;
     RECT  0.103 26.802 0.139 27.279 ;
     RECT  0.103 41.841 0.139 41.859 ;
     RECT  0.103 29.808 0.175 30.474 ;
     RECT  0.103 45.126 0.175 45.144 ;
     RECT  0.103 15.3 0.203 15.318 ;
     RECT  0.103 16.848 0.203 17.289 ;
     RECT  0.103 19.62 0.203 19.638 ;
     RECT  0.103 21.438 0.203 21.456 ;
     RECT  0.103 22.518 0.203 22.536 ;
     RECT  0.139 24.066 0.203 24.354 ;
     RECT  0.175 29.61 0.203 30.474 ;
     RECT  0.103 31.5 0.203 31.752 ;
     RECT  0.103 34.128 0.203 34.146 ;
     RECT  0.103 35.208 0.203 36.108 ;
     RECT  0.103 38.871 0.203 39.114 ;
     RECT  0.139 26.136 0.239 27.279 ;
     RECT  0.103 37.566 0.239 37.584 ;
     RECT  0.139 41.796 0.239 41.859 ;
     RECT  0.239 26.64 0.275 27.279 ;
     RECT  0.203 29.61 0.275 29.628 ;
     RECT  0.275 26.64 0.347 26.658 ;
     RECT  0.203 30.456 0.347 30.474 ;
     RECT  0.203 39.096 0.347 39.114 ;
     RECT  0.239 41.841 0.347 41.859 ;
     RECT  0.283 14.148 0.355 14.166 ;
     RECT  0.203 35.208 0.383 36.036 ;
     RECT  0.103 40.842 0.383 40.86 ;
     RECT  0.355 14.112 0.391 14.166 ;
     RECT  0.103 12.996 0.427 13.014 ;
     RECT  0.391 13.986 0.427 14.166 ;
     RECT  0.427 12.996 0.535 14.166 ;
     RECT  0.175 45.126 1.183 45.522 ;
     RECT  1.147 43.506 1.723 43.524 ;
     RECT  0.535 21.474 1.975 21.492 ;
     RECT  0.535 12.996 2.16 14.436 ;
     RECT  0.499 16.236 2.16 16.326 ;
     RECT  0.211 17.424 2.16 17.442 ;
     RECT  1.975 21.168 2.16 21.492 ;
     RECT  0.535 23.526 2.16 23.544 ;
     RECT  0.203 24.336 2.16 24.354 ;
     RECT  1.219 33.426 2.16 33.444 ;
     RECT  0.383 35.946 2.16 36.036 ;
     RECT  1.291 42.534 2.16 42.552 ;
     RECT  1.723 43.416 2.16 43.524 ;
     RECT  1.183 44.856 2.16 45.522 ;
     RECT  2.16 2.151 28.471 57.249 ;
     RECT  28.471 2.106 29.579 57.249 ;
     RECT  29.579 2.151 57.24 57.249 ;
     RECT  57.24 18.738 57.551 49.464 ;
     RECT  57.551 18.738 57.587 40.32 ;
     RECT  57.551 41.112 57.623 49.464 ;
     RECT  57.587 18.738 57.695 23.724 ;
     RECT  57.623 41.112 58.091 49.338 ;
     RECT  57.587 24.606 58.127 40.32 ;
     RECT  58.091 41.112 58.127 43.02 ;
     RECT  58.091 43.848 58.127 49.338 ;
     RECT  57.695 18.738 58.163 23.58 ;
     RECT  58.163 18.738 58.199 23.346 ;
     RECT  58.199 18.738 58.235 21.222 ;
     RECT  58.199 22.086 58.235 23.346 ;
     RECT  58.127 24.606 58.235 29.088 ;
     RECT  58.235 19.512 58.595 21.222 ;
     RECT  58.595 19.548 58.667 21.222 ;
     RECT  58.127 29.916 58.667 40.086 ;
     RECT  58.667 29.916 58.703 31.41 ;
     RECT  58.667 32.238 58.703 40.086 ;
     RECT  58.127 41.526 58.703 43.02 ;
     RECT  58.127 44.622 58.703 49.338 ;
     RECT  58.667 19.548 58.739 20.34 ;
     RECT  58.667 21.132 58.739 21.222 ;
     RECT  58.235 24.606 58.739 26.514 ;
     RECT  58.703 31.122 58.739 31.41 ;
     RECT  58.703 32.814 58.739 34.758 ;
     RECT  58.703 35.784 58.739 40.086 ;
     RECT  58.703 41.526 58.739 42.48 ;
     RECT  58.703 44.622 58.739 45.486 ;
     RECT  58.235 18.738 58.775 18.756 ;
     RECT  58.235 23.328 58.775 23.346 ;
     RECT  58.739 25.992 58.775 26.514 ;
     RECT  58.703 29.916 58.775 30.294 ;
     RECT  58.739 33.354 58.775 34.758 ;
     RECT  58.739 36.522 58.775 37.152 ;
     RECT  58.739 38.214 58.775 39.384 ;
     RECT  58.739 44.928 58.775 45.054 ;
     RECT  58.703 46.242 58.775 49.338 ;
     RECT  58.739 19.548 58.811 19.566 ;
     RECT  58.235 22.086 58.811 22.104 ;
     RECT  58.775 25.992 58.811 26.01 ;
     RECT  58.235 27.954 58.811 29.088 ;
     RECT  58.775 29.916 58.811 29.934 ;
     RECT  58.775 34.092 58.811 34.758 ;
     RECT  58.775 37.098 58.811 37.152 ;
     RECT  58.739 41.526 58.811 42.21 ;
     RECT  58.775 44.928 58.811 44.982 ;
     RECT  58.775 46.476 58.811 46.674 ;
     RECT  58.775 47.97 58.811 48.222 ;
     RECT  58.739 20.322 58.847 20.34 ;
     RECT  58.739 25.182 58.847 25.2 ;
     RECT  58.811 27.954 58.847 28.71 ;
     RECT  58.811 34.2 58.847 34.758 ;
     RECT  58.775 38.718 58.847 38.736 ;
     RECT  58.811 41.526 58.847 41.814 ;
     RECT  58.811 46.476 58.847 46.494 ;
     RECT  58.811 48.204 58.847 48.222 ;
     RECT  58.739 21.204 58.883 21.222 ;
     RECT  58.847 27.954 58.883 28.404 ;
     RECT  58.811 37.098 58.883 37.116 ;
     RECT  58.847 41.526 58.883 41.544 ;
     RECT  58.811 44.928 58.883 44.946 ;
     RECT  58.775 49.32 58.883 49.338 ;
     RECT  58.883 27.954 58.919 27.972 ;
     RECT  58.739 31.122 59.171 31.176 ;
     RECT  59.171 31.122 59.315 31.14 ;
    LAYER M3 ;
     RECT  28.368 0.091 28.386 1.723 ;
     RECT  28.26 1.723 28.386 2.101 ;
     RECT  29.556 2.101 29.574 2.143 ;
     RECT  29.415 2.143 29.574 2.191 ;
     RECT  28.26 2.101 28.494 2.255 ;
     RECT  28.368 2.255 28.494 2.263 ;
     RECT  29.34 2.191 29.574 2.263 ;
     RECT  2.415 2.143 2.505 2.413 ;
     RECT  7.815 2.143 7.905 2.413 ;
     RECT  13.215 2.143 13.305 2.413 ;
     RECT  18.615 2.143 18.705 2.413 ;
     RECT  24.015 2.143 24.105 2.413 ;
     RECT  28.368 2.263 29.574 2.413 ;
     RECT  34.815 2.143 34.905 2.413 ;
     RECT  40.215 2.143 40.305 2.413 ;
     RECT  45.615 2.143 45.705 2.413 ;
     RECT  51.015 2.143 51.105 2.413 ;
     RECT  56.415 2.143 56.505 2.413 ;
     RECT  28.368 2.413 29.697 2.489 ;
     RECT  28.656 2.489 29.697 3.301 ;
     RECT  28.44 3.301 29.697 3.341 ;
     RECT  27.828 3.685 27.846 3.721 ;
     RECT  27.36 3.721 27.846 3.725 ;
     RECT  28.656 3.341 29.697 3.875 ;
     RECT  28.692 3.875 29.697 4.801 ;
     RECT  27.36 3.725 27.378 5.071 ;
     RECT  28.152 4.801 29.697 5.071 ;
     RECT  27.36 5.071 29.697 5.099 ;
     RECT  27.36 5.099 27.954 5.459 ;
     RECT  28.728 5.099 29.697 5.459 ;
     RECT  27.36 5.459 27.882 7.435 ;
     RECT  27.36 7.435 28.494 7.805 ;
     RECT  27.36 7.805 27.918 7.997 ;
     RECT  0.108 12.991 0.126 13.261 ;
     RECT  2.415 2.413 2.697 13.531 ;
     RECT  2.415 13.531 3.186 13.567 ;
     RECT  2.415 13.567 3.906 13.639 ;
     RECT  0.108 13.261 0.486 13.675 ;
     RECT  7.815 2.413 8.097 13.981 ;
     RECT  0.108 13.675 0.522 14.071 ;
     RECT  7.668 13.981 8.097 14.071 ;
     RECT  18.615 2.413 18.897 14.107 ;
     RECT  0.108 14.071 0.558 14.189 ;
     RECT  5.724 14.215 5.742 14.251 ;
     RECT  7.524 14.071 8.097 14.251 ;
     RECT  10.8 13.981 10.818 14.251 ;
     RECT  5.724 14.251 6.426 14.341 ;
     RECT  7.272 14.251 8.658 14.341 ;
     RECT  10.728 14.251 10.818 14.341 ;
     RECT  11.7 14.251 11.718 14.341 ;
     RECT  5.724 14.341 8.982 14.369 ;
     RECT  10.476 14.341 11.718 14.377 ;
     RECT  6.264 14.369 8.982 14.413 ;
     RECT  6.264 14.413 9.126 14.485 ;
     RECT  6.264 14.485 9.162 14.521 ;
     RECT  10.476 14.377 12.114 14.521 ;
     RECT  6.264 14.521 12.114 14.711 ;
     RECT  2.415 13.639 4.59 14.731 ;
     RECT  2.412 14.731 4.59 14.791 ;
     RECT  2.412 14.791 4.626 14.881 ;
     RECT  13.215 2.413 13.497 14.881 ;
     RECT  2.34 14.881 4.626 14.953 ;
     RECT  12.636 14.881 13.986 14.989 ;
     RECT  53.424 14.989 53.442 15.025 ;
     RECT  54.468 14.683 54.486 15.025 ;
     RECT  0.288 14.189 0.558 15.053 ;
     RECT  12.636 14.989 14.49 15.061 ;
     RECT  0.288 15.053 0.306 15.115 ;
     RECT  53.424 15.025 54.486 15.151 ;
     RECT  51.015 2.413 51.297 15.223 ;
     RECT  0.144 15.115 0.306 15.245 ;
     RECT  53.424 15.151 54.954 15.259 ;
     RECT  0.144 15.245 0.198 15.292 ;
     RECT  22.788 14.449 22.806 15.295 ;
     RECT  2.304 14.953 4.626 15.403 ;
     RECT  12.636 15.061 14.814 15.421 ;
     RECT  24.015 2.413 24.297 15.421 ;
     RECT  0.108 15.292 0.198 15.437 ;
     RECT  0.144 15.437 0.198 15.485 ;
     RECT  6.516 14.711 11.718 15.493 ;
     RECT  12.636 15.421 14.886 15.493 ;
     RECT  5.724 15.187 5.742 15.557 ;
     RECT  6.516 15.493 14.886 15.565 ;
     RECT  22.464 15.295 22.806 15.565 ;
     RECT  2.304 15.403 4.77 15.601 ;
     RECT  6.516 15.565 14.958 15.601 ;
     RECT  2.304 15.601 4.878 15.691 ;
     RECT  6.12 15.601 14.958 15.719 ;
     RECT  6.12 15.719 14.886 15.791 ;
     RECT  26.424 15.871 26.442 15.961 ;
     RECT  52.992 15.259 54.954 16.069 ;
     RECT  1.152 15.595 1.17 16.171 ;
     RECT  0.144 15.485 0.162 16.231 ;
     RECT  1.152 16.171 1.278 16.231 ;
     RECT  6.516 15.791 14.886 16.295 ;
     RECT  0.144 16.231 1.278 16.301 ;
     RECT  52.992 16.069 55.53 16.303 ;
     RECT  0.144 16.301 1.17 16.397 ;
     RECT  2.304 15.691 5.202 16.501 ;
     RECT  27.36 7.997 27.882 16.501 ;
     RECT  6.552 16.295 14.886 16.529 ;
     RECT  2.304 16.501 5.346 16.537 ;
     RECT  25.452 16.537 25.47 16.603 ;
     RECT  2.304 16.537 5.418 16.645 ;
     RECT  24.015 15.421 24.426 16.645 ;
     RECT  25.236 16.603 25.47 16.645 ;
     RECT  0.144 16.397 0.666 16.685 ;
     RECT  0.144 16.685 0.522 16.747 ;
     RECT  2.304 16.645 5.526 16.879 ;
     RECT  24.015 16.645 25.47 16.915 ;
     RECT  26.352 15.961 26.442 16.915 ;
     RECT  51.015 15.223 51.39 16.951 ;
     RECT  0.108 16.747 0.522 16.973 ;
     RECT  2.304 16.879 5.778 17.149 ;
     RECT  6.552 16.529 14.778 17.149 ;
     RECT  0.108 16.973 0.342 17.294 ;
     RECT  2.304 17.149 14.778 17.347 ;
     RECT  24.015 16.915 26.442 17.383 ;
     RECT  27.36 16.501 28.206 17.383 ;
     RECT  0.216 17.294 0.342 17.453 ;
     RECT  0.216 17.453 0.234 17.456 ;
     RECT  2.304 17.347 14.886 17.491 ;
     RECT  2.304 17.491 14.958 17.681 ;
     RECT  1.26 17.803 1.278 17.899 ;
     RECT  52.884 16.303 55.53 17.923 ;
     RECT  2.304 17.681 14.814 17.951 ;
     RECT  29.415 5.459 29.697 17.995 ;
     RECT  2.304 17.951 14.562 18.023 ;
     RECT  2.304 18.023 14.526 18.185 ;
     RECT  2.304 18.185 13.59 18.379 ;
     RECT  28.98 17.995 29.697 18.427 ;
     RECT  1.152 17.899 1.278 18.475 ;
     RECT  2.268 18.379 13.59 18.475 ;
     RECT  56.415 2.413 56.697 18.571 ;
     RECT  52.668 17.923 55.53 18.661 ;
     RECT  56.304 18.571 56.697 18.661 ;
     RECT  52.668 18.661 56.697 18.697 ;
     RECT  28.98 18.427 29.826 18.769 ;
     RECT  0.324 18.667 0.342 18.797 ;
     RECT  14.508 18.185 14.526 18.805 ;
     RECT  14.508 18.805 14.814 18.841 ;
     RECT  1.152 18.475 13.59 18.931 ;
     RECT  14.508 18.841 14.958 18.931 ;
     RECT  52.668 18.697 56.934 18.931 ;
     RECT  22.428 15.565 22.806 19.111 ;
     RECT  1.152 18.931 14.958 19.229 ;
     RECT  58.752 18.733 58.77 19.237 ;
     RECT  24.015 17.383 28.206 19.309 ;
     RECT  1.152 19.229 14.814 19.373 ;
     RECT  58.212 19.237 58.77 19.543 ;
     RECT  52.668 18.931 57.006 19.579 ;
     RECT  0.144 18.859 0.162 19.612 ;
     RECT  52.668 19.579 57.078 19.615 ;
     RECT  52.164 19.615 57.078 19.777 ;
     RECT  58.212 19.543 58.806 19.777 ;
     RECT  18.615 14.107 19.458 19.849 ;
     RECT  20.808 17.689 20.826 19.849 ;
     RECT  1.152 19.373 14.778 19.901 ;
     RECT  1.26 19.901 14.778 19.949 ;
     RECT  50.94 16.951 51.39 20.005 ;
     RECT  52.164 19.777 58.806 20.005 ;
     RECT  0.108 19.612 0.198 20.011 ;
     RECT  1.98 19.949 14.778 20.119 ;
     RECT  0.108 20.011 0.342 20.141 ;
     RECT  50.94 20.005 58.806 20.152 ;
     RECT  22.068 19.111 22.806 20.155 ;
     RECT  18.615 19.849 20.826 20.317 ;
     RECT  50.904 20.152 58.806 20.317 ;
     RECT  0.108 20.141 0.198 20.333 ;
     RECT  22.068 20.155 22.842 20.345 ;
     RECT  1.98 20.119 14.814 20.381 ;
     RECT  12.528 20.381 14.814 20.389 ;
     RECT  28.98 18.769 29.862 20.389 ;
     RECT  12.528 20.389 14.886 20.489 ;
     RECT  50.904 20.317 58.842 20.491 ;
     RECT  50.436 20.491 58.842 20.579 ;
     RECT  1.98 20.381 11.79 20.717 ;
     RECT  1.98 20.717 10.53 20.849 ;
     RECT  1.98 20.849 9.882 20.957 ;
     RECT  1.98 20.957 9.81 21.119 ;
     RECT  49.14 21.127 49.158 21.163 ;
     RECT  1.98 21.119 5.958 21.191 ;
     RECT  11.412 20.717 11.79 21.199 ;
     RECT  12.528 20.489 14.526 21.199 ;
     RECT  50.724 20.579 58.842 21.199 ;
     RECT  0.108 20.333 0.126 21.211 ;
     RECT  11.412 21.199 14.526 21.235 ;
     RECT  34.815 2.413 35.097 21.271 ;
     RECT  35.856 21.199 35.874 21.271 ;
     RECT  49.068 21.163 49.158 21.355 ;
     RECT  2.304 21.191 5.958 21.389 ;
     RECT  49.032 21.355 49.158 21.389 ;
     RECT  0.108 21.211 0.198 21.469 ;
     RECT  11.412 21.235 14.886 21.497 ;
     RECT  11.412 21.497 14.814 21.505 ;
     RECT  17.928 20.317 20.826 21.505 ;
     RECT  22.068 20.345 22.806 21.505 ;
     RECT  0.108 21.469 0.558 21.581 ;
     RECT  50.724 21.199 58.878 21.667 ;
     RECT  0.144 21.581 0.558 21.677 ;
     RECT  23.724 19.309 28.206 21.739 ;
     RECT  11.268 21.505 14.814 21.775 ;
     RECT  50.58 21.667 58.878 21.811 ;
     RECT  10.98 21.775 14.814 21.901 ;
     RECT  6.696 21.119 9.81 21.937 ;
     RECT  34.815 21.271 35.874 21.973 ;
     RECT  10.908 21.901 14.814 21.979 ;
     RECT  31.5 19.003 31.518 21.979 ;
     RECT  50.436 21.811 58.878 22.045 ;
     RECT  17.928 21.505 22.806 22.081 ;
     RECT  30.78 21.979 31.518 22.109 ;
     RECT  2.304 21.389 5.886 22.171 ;
     RECT  6.696 21.937 9.99 22.171 ;
     RECT  10.8 21.979 14.814 22.235 ;
     RECT  50.364 22.045 58.878 22.235 ;
     RECT  13.068 22.235 14.814 22.243 ;
     RECT  34.815 21.973 36.414 22.243 ;
     RECT  2.304 22.171 9.99 22.279 ;
     RECT  10.8 22.235 12.078 22.279 ;
     RECT  0.144 21.677 0.162 22.411 ;
     RECT  0.108 22.411 0.162 22.459 ;
     RECT  2.304 22.279 12.078 22.469 ;
     RECT  23.724 21.739 28.242 22.513 ;
     RECT  0.108 22.459 0.198 22.556 ;
     RECT  49.032 21.389 49.122 22.585 ;
     RECT  49.032 22.585 49.158 22.811 ;
     RECT  17.928 22.081 22.842 22.819 ;
     RECT  23.58 22.513 28.242 22.819 ;
     RECT  13.068 22.243 14.85 22.981 ;
     RECT  34.815 22.243 36.558 22.981 ;
     RECT  50.724 22.235 58.878 22.981 ;
     RECT  12.816 22.981 14.85 23.053 ;
     RECT  49.032 22.811 49.086 23.117 ;
     RECT  12.816 23.053 14.886 23.153 ;
     RECT  46.764 21.235 46.782 23.153 ;
     RECT  34.815 22.981 37.026 23.161 ;
     RECT  17.928 22.819 28.242 23.189 ;
     RECT  49.032 23.117 49.05 23.189 ;
     RECT  50.148 22.981 58.878 23.287 ;
     RECT  0.144 22.556 0.162 23.521 ;
     RECT  2.304 22.469 12.042 23.557 ;
     RECT  12.816 23.153 14.778 23.557 ;
     RECT  28.98 20.389 29.934 23.665 ;
     RECT  30.708 23.593 30.726 23.665 ;
     RECT  34.815 23.161 37.422 23.791 ;
     RECT  34.815 23.791 37.998 23.827 ;
     RECT  2.304 23.557 14.778 23.935 ;
     RECT  17.928 23.189 22.842 23.971 ;
     RECT  0.144 23.521 0.558 24.043 ;
     RECT  17.64 23.971 22.842 24.088 ;
     RECT  23.58 23.189 28.242 24.088 ;
     RECT  17.64 24.088 28.242 24.089 ;
     RECT  2.304 23.935 14.886 24.161 ;
     RECT  49.968 23.287 58.878 24.173 ;
     RECT  49.968 24.173 58.842 24.197 ;
     RECT  28.98 23.665 30.726 24.241 ;
     RECT  31.5 22.109 31.518 24.241 ;
     RECT  0.108 24.043 0.558 24.269 ;
     RECT  2.304 24.161 14.814 24.269 ;
     RECT  28.98 24.241 31.518 24.359 ;
     RECT  46.8 23.701 46.818 24.359 ;
     RECT  34.815 23.827 38.538 24.403 ;
     RECT  17.928 24.089 28.242 24.475 ;
     RECT  28.98 24.359 30.438 24.475 ;
     RECT  50.148 24.197 58.842 24.629 ;
     RECT  2.304 24.269 14.67 24.859 ;
     RECT  34.776 24.403 38.538 24.943 ;
     RECT  49.032 24.745 49.05 24.971 ;
     RECT  0.108 24.269 0.414 25.037 ;
     RECT  2.268 24.859 14.67 25.051 ;
     RECT  50.616 24.629 58.842 25.205 ;
     RECT  17.928 24.475 30.438 25.285 ;
     RECT  31.5 24.359 31.518 25.285 ;
     RECT  2.268 25.051 14.706 25.411 ;
     RECT  2.268 25.411 14.778 25.447 ;
     RECT  2.196 25.447 14.778 25.483 ;
     RECT  15.804 25.249 15.822 25.483 ;
     RECT  2.196 25.483 15.822 25.517 ;
     RECT  50.616 25.205 58.806 25.531 ;
     RECT  17.928 25.285 31.518 25.619 ;
     RECT  50.328 25.531 58.806 25.745 ;
     RECT  16.632 24.907 16.65 25.861 ;
     RECT  20.484 25.619 31.518 25.889 ;
     RECT  46.8 25.321 46.818 25.951 ;
     RECT  0.108 25.037 0.234 25.963 ;
     RECT  46.764 25.951 46.818 25.987 ;
     RECT  58.716 25.745 58.806 26.015 ;
     RECT  34.236 24.943 38.538 26.095 ;
     RECT  46.764 25.987 46.962 26.123 ;
     RECT  50.328 25.745 57.654 26.131 ;
     RECT  46.764 26.123 46.89 26.159 ;
     RECT  21.348 25.889 31.518 26.329 ;
     RECT  2.268 25.517 15.822 26.357 ;
     RECT  16.632 25.861 16.902 26.365 ;
     RECT  34.2 26.095 38.538 26.429 ;
     RECT  49.608 26.131 57.654 26.519 ;
     RECT  58.716 26.015 58.77 26.519 ;
     RECT  17.928 25.619 19.458 26.563 ;
     RECT  50.004 26.519 57.654 26.635 ;
     RECT  34.236 26.429 38.538 26.797 ;
     RECT  20.484 25.889 20.574 26.869 ;
     RECT  34.236 26.797 38.79 27.131 ;
     RECT  34.38 27.131 38.79 27.139 ;
     RECT  20.412 26.869 20.574 27.167 ;
     RECT  20.412 27.167 20.538 27.203 ;
     RECT  2.304 26.357 15.822 27.245 ;
     RECT  0.108 25.963 0.342 27.533 ;
     RECT  16.632 26.365 17.118 27.643 ;
     RECT  17.928 26.563 19.494 27.643 ;
     RECT  32.724 19.885 32.742 27.739 ;
     RECT  46.764 26.159 46.854 27.751 ;
     RECT  50.004 26.635 58.23 27.869 ;
     RECT  40.215 2.413 40.497 27.949 ;
     RECT  50.796 27.869 58.23 27.949 ;
     RECT  34.38 27.139 38.97 27.985 ;
     RECT  2.304 27.245 10.854 28.021 ;
     RECT  34.38 27.985 39.114 28.021 ;
     RECT  2.304 28.021 10.926 28.111 ;
     RECT  11.664 27.245 15.822 28.111 ;
     RECT  40.032 27.949 40.497 28.147 ;
     RECT  32.724 27.739 33.102 28.183 ;
     RECT  34.38 28.021 39.186 28.183 ;
     RECT  39.96 28.147 40.497 28.183 ;
     RECT  32.724 28.183 33.174 28.319 ;
     RECT  46.764 27.751 46.926 28.561 ;
     RECT  48.456 28.759 48.474 28.795 ;
     RECT  50.004 27.869 50.022 28.795 ;
     RECT  50.796 27.949 58.914 28.795 ;
     RECT  46.764 28.561 47.322 28.823 ;
     RECT  42.696 28.723 42.714 28.831 ;
     RECT  42.66 28.831 42.714 28.832 ;
     RECT  21.348 26.329 31.662 28.859 ;
     RECT  32.724 28.319 33.138 28.859 ;
     RECT  50.004 28.795 58.914 28.891 ;
     RECT  42.66 28.832 42.678 28.985 ;
     RECT  34.38 28.183 40.497 29.065 ;
     RECT  46.8 28.823 47.322 29.065 ;
     RECT  0.144 27.533 0.342 29.069 ;
     RECT  50.004 28.891 58.986 29.069 ;
     RECT  16.632 27.643 19.494 29.101 ;
     RECT  50.004 29.069 58.806 29.263 ;
     RECT  2.304 28.111 15.822 29.299 ;
     RECT  46.8 29.065 47.43 29.363 ;
     RECT  2.304 29.299 15.858 29.461 ;
     RECT  16.632 29.101 19.566 29.461 ;
     RECT  32.724 28.859 33.102 29.561 ;
     RECT  48.456 28.795 48.546 29.641 ;
     RECT  49.968 29.263 58.806 29.731 ;
     RECT  0.144 29.069 0.27 29.788 ;
     RECT  49.896 29.731 58.806 29.837 ;
     RECT  48.456 29.641 49.122 29.939 ;
     RECT  34.38 29.065 40.986 30.091 ;
     RECT  0.108 29.788 0.27 30.283 ;
     RECT  34.38 30.091 41.166 30.379 ;
     RECT  42.12 30.145 42.138 30.379 ;
     RECT  49.968 29.837 58.806 30.379 ;
     RECT  46.8 29.363 46.818 30.415 ;
     RECT  46.764 30.415 46.818 30.451 ;
     RECT  0.108 30.283 0.342 30.479 ;
     RECT  48.456 29.939 49.086 30.479 ;
     RECT  0.144 30.479 0.342 30.605 ;
     RECT  46.764 30.451 46.854 30.641 ;
     RECT  0.144 30.605 0.198 30.653 ;
     RECT  46.764 30.641 46.782 30.713 ;
     RECT  49.068 30.479 49.086 30.991 ;
     RECT  49.968 30.379 59.31 30.991 ;
     RECT  49.068 30.991 59.31 31.145 ;
     RECT  49.068 31.145 59.166 31.181 ;
     RECT  49.068 31.181 58.734 31.253 ;
     RECT  0.144 30.653 0.162 31.339 ;
     RECT  21.42 28.859 31.662 31.381 ;
     RECT  0.108 31.339 0.162 31.387 ;
     RECT  20.412 27.203 20.502 31.387 ;
     RECT  21.42 31.381 31.734 31.387 ;
     RECT  49.608 31.253 58.734 31.415 ;
     RECT  32.724 29.561 32.85 31.495 ;
     RECT  46.836 31.459 46.854 31.531 ;
     RECT  2.304 29.461 19.566 31.675 ;
     RECT  20.412 31.387 31.806 31.729 ;
     RECT  45.615 2.413 45.897 31.729 ;
     RECT  46.764 31.531 46.854 31.729 ;
     RECT  0.108 31.387 0.198 31.805 ;
     RECT  0.108 31.805 0.126 31.853 ;
     RECT  34.38 30.379 42.138 31.927 ;
     RECT  2.304 31.675 19.602 31.955 ;
     RECT  49.608 31.415 58.698 31.999 ;
     RECT  32.724 31.495 33.102 32.071 ;
     RECT  34.38 31.927 42.318 32.071 ;
     RECT  20.412 31.729 31.95 32.099 ;
     RECT  43.884 31.621 43.902 32.099 ;
     RECT  49.032 31.999 58.698 32.099 ;
     RECT  12.204 31.955 19.602 32.161 ;
     RECT  20.412 32.099 31.662 32.161 ;
     RECT  34.38 32.071 42.786 32.161 ;
     RECT  32.724 32.071 33.282 32.198 ;
     RECT  45.615 31.729 46.854 32.269 ;
     RECT  2.304 31.955 11.466 32.395 ;
     RECT  32.724 32.198 33.246 32.459 ;
     RECT  49.644 32.099 58.698 32.459 ;
     RECT  45.615 32.269 46.926 32.611 ;
     RECT  45.036 32.611 47.178 32.701 ;
     RECT  45.036 32.701 47.574 32.729 ;
     RECT  2.268 32.395 11.466 32.737 ;
     RECT  12.204 32.161 31.662 32.737 ;
     RECT  44.028 32.575 44.082 32.737 ;
     RECT  45.036 32.729 45.897 32.737 ;
     RECT  32.724 32.459 33.102 32.765 ;
     RECT  50.004 32.459 58.698 32.809 ;
     RECT  0.324 32.683 0.342 32.813 ;
     RECT  44.028 32.737 45.897 32.845 ;
     RECT  50.004 32.809 58.734 32.875 ;
     RECT  46.764 32.729 47.574 32.999 ;
     RECT  2.268 32.737 31.662 33.071 ;
     RECT  43.992 32.845 45.897 33.071 ;
     RECT  46.764 32.999 47.322 33.071 ;
     RECT  48.456 33.079 48.474 33.151 ;
     RECT  2.304 33.071 31.662 33.305 ;
     RECT  0.144 33.163 0.162 33.341 ;
     RECT  2.34 33.305 31.662 33.349 ;
     RECT  1.224 31.051 1.242 33.449 ;
     RECT  46.764 33.071 46.89 33.449 ;
     RECT  34.38 32.161 43.074 33.511 ;
     RECT  48.456 33.151 49.158 33.547 ;
     RECT  50.004 32.875 58.806 33.547 ;
     RECT  46.8 33.449 46.89 33.719 ;
     RECT  48.456 33.547 58.806 33.719 ;
     RECT  50.004 33.719 58.806 33.809 ;
     RECT  2.34 33.349 31.95 33.889 ;
     RECT  32.724 32.765 32.85 33.889 ;
     RECT  34.38 33.511 43.542 33.889 ;
     RECT  44.28 33.071 45.897 33.889 ;
     RECT  46.8 33.719 46.818 33.953 ;
     RECT  2.34 33.889 32.85 34.027 ;
     RECT  48.456 33.719 49.122 34.151 ;
     RECT  50.256 33.809 58.806 34.195 ;
     RECT  2.268 34.027 32.85 34.205 ;
     RECT  0.108 34.108 0.198 34.349 ;
     RECT  0.144 34.349 0.198 34.603 ;
     RECT  50.256 34.195 58.842 34.663 ;
     RECT  50.22 34.663 58.842 34.763 ;
     RECT  48.456 34.151 49.086 35.033 ;
     RECT  50.22 34.763 58.77 35.117 ;
     RECT  0.144 34.603 0.342 35.179 ;
     RECT  46.8 35.041 46.818 35.195 ;
     RECT  0.108 35.179 0.342 35.203 ;
     RECT  50.22 35.117 58.734 35.401 ;
     RECT  50.148 35.401 58.734 35.453 ;
     RECT  49.032 35.033 49.086 35.509 ;
     RECT  2.304 34.205 32.85 35.699 ;
     RECT  49.032 35.509 49.122 35.771 ;
     RECT  0.108 35.203 0.378 35.941 ;
     RECT  0.108 35.941 0.558 36.113 ;
     RECT  50.508 35.453 58.734 36.247 ;
     RECT  46.764 36.121 46.89 36.311 ;
     RECT  12.456 35.699 32.85 36.319 ;
     RECT  49.032 35.771 49.05 36.347 ;
     RECT  46.764 36.311 46.854 36.419 ;
     RECT  2.304 35.699 11.394 36.481 ;
     RECT  50.184 36.247 58.734 36.517 ;
     RECT  50.184 36.517 58.77 36.523 ;
     RECT  50.076 36.523 58.77 36.589 ;
     RECT  0.144 36.113 0.558 36.653 ;
     RECT  49.068 36.589 49.086 36.653 ;
     RECT  49.86 36.589 58.77 36.715 ;
     RECT  49.86 36.715 58.806 36.779 ;
     RECT  50.616 36.779 58.806 36.811 ;
     RECT  46.764 36.419 46.818 36.815 ;
     RECT  12.456 36.319 33.102 36.823 ;
     RECT  49.86 36.779 49.878 37.049 ;
     RECT  50.616 36.811 58.878 37.121 ;
     RECT  12.204 36.823 33.102 37.193 ;
     RECT  2.304 36.481 11.43 37.201 ;
     RECT  12.204 37.193 32.85 37.201 ;
     RECT  0.144 36.653 0.342 37.421 ;
     RECT  2.304 37.201 32.85 37.463 ;
     RECT  0.144 37.421 0.234 37.561 ;
     RECT  0.108 37.561 0.234 37.589 ;
     RECT  2.304 37.463 31.662 37.589 ;
     RECT  0.108 37.589 0.198 37.613 ;
     RECT  46.8 36.815 46.818 37.705 ;
     RECT  50.616 37.121 58.842 37.741 ;
     RECT  0.18 37.613 0.198 37.805 ;
     RECT  50.364 37.741 58.842 37.867 ;
     RECT  50.148 37.867 58.842 37.904 ;
     RECT  46.764 37.705 46.818 37.931 ;
     RECT  1.152 37.195 1.17 37.963 ;
     RECT  46.764 37.931 46.782 38.039 ;
     RECT  1.152 37.963 1.278 38.189 ;
     RECT  50.616 37.904 58.842 38.189 ;
     RECT  2.304 37.589 5.814 38.407 ;
     RECT  6.696 37.589 31.662 38.407 ;
     RECT  2.304 38.407 31.662 38.435 ;
     RECT  34.38 33.889 45.897 38.551 ;
     RECT  2.304 38.435 11.322 38.621 ;
     RECT  1.152 38.189 1.242 38.669 ;
     RECT  50.904 38.189 58.842 38.705 ;
     RECT  1.152 38.669 1.17 38.717 ;
     RECT  51.015 38.705 58.842 38.741 ;
     RECT  32.544 37.463 32.85 38.749 ;
     RECT  0.324 38.347 0.342 38.779 ;
     RECT  0.18 38.779 0.342 38.827 ;
     RECT  34.38 38.551 46.386 38.849 ;
     RECT  0.108 38.827 0.342 39.115 ;
     RECT  7.2 38.621 11.322 39.181 ;
     RECT  12.132 38.435 31.662 39.181 ;
     RECT  46.764 39.091 46.782 39.209 ;
     RECT  0.108 39.115 0.414 39.293 ;
     RECT  7.2 39.181 31.662 39.389 ;
     RECT  51.015 38.741 58.77 39.437 ;
     RECT  2.304 38.621 6.282 39.451 ;
     RECT  7.2 39.389 10.89 39.451 ;
     RECT  51.015 39.437 57.546 39.451 ;
     RECT  0.108 39.293 0.126 39.581 ;
     RECT  49.932 38.677 49.95 39.631 ;
     RECT  50.724 39.451 57.546 39.631 ;
     RECT  2.304 39.451 10.89 39.749 ;
     RECT  32.544 38.749 32.958 39.793 ;
     RECT  11.808 39.389 31.662 39.893 ;
     RECT  49.932 39.631 57.546 39.893 ;
     RECT  58.608 39.437 58.77 39.979 ;
     RECT  2.304 39.749 8.946 40.019 ;
     RECT  58.608 39.979 58.878 40.157 ;
     RECT  11.808 39.893 11.826 40.165 ;
     RECT  9.684 39.749 10.89 40.171 ;
     RECT  11.7 40.165 11.826 40.171 ;
     RECT  50.004 39.893 57.546 40.171 ;
     RECT  5.976 40.019 8.946 40.199 ;
     RECT  50.004 40.171 57.834 40.297 ;
     RECT  6.264 40.199 8.946 40.397 ;
     RECT  2.304 40.019 5.202 40.603 ;
     RECT  50.004 40.297 58.122 40.675 ;
     RECT  0.144 40.459 0.162 40.747 ;
     RECT  1.296 40.363 1.314 40.795 ;
     RECT  0.144 40.747 0.342 40.837 ;
     RECT  49.932 40.675 58.122 40.837 ;
     RECT  0.108 40.837 0.378 40.877 ;
     RECT  49.86 40.837 58.122 40.877 ;
     RECT  46.764 40.837 46.782 40.909 ;
     RECT  49.932 40.877 58.122 40.937 ;
     RECT  2.268 40.603 5.202 40.939 ;
     RECT  0.144 40.877 0.378 40.973 ;
     RECT  49.968 40.937 58.122 40.973 ;
     RECT  7.815 40.397 8.946 40.981 ;
     RECT  9.684 40.171 11.826 40.981 ;
     RECT  46.764 40.909 46.854 41.009 ;
     RECT  51.015 40.973 58.122 41.035 ;
     RECT  7.815 40.981 11.826 41.071 ;
     RECT  12.744 39.893 31.662 41.071 ;
     RECT  6.264 40.397 6.93 41.107 ;
     RECT  51.015 41.035 58.734 41.131 ;
     RECT  51.015 41.131 58.77 41.171 ;
     RECT  2.268 40.939 5.31 41.215 ;
     RECT  6.084 41.107 6.93 41.215 ;
     RECT  7.815 41.071 31.662 41.215 ;
     RECT  32.508 39.793 32.958 41.215 ;
     RECT  58.68 41.171 58.77 41.227 ;
     RECT  2.268 41.215 6.93 41.251 ;
     RECT  7.815 41.215 32.958 41.251 ;
     RECT  46.764 41.009 46.782 41.279 ;
     RECT  58.68 41.227 58.806 41.323 ;
     RECT  49.968 40.973 50.166 41.369 ;
     RECT  51.015 41.171 57.834 41.369 ;
     RECT  58.68 41.323 58.842 41.419 ;
     RECT  57.816 41.369 57.834 41.513 ;
     RECT  58.68 41.419 58.878 41.549 ;
     RECT  0.144 40.973 0.342 41.707 ;
     RECT  58.68 41.549 58.842 41.819 ;
     RECT  51.015 41.369 57.006 41.881 ;
     RECT  0.108 41.707 0.342 41.933 ;
     RECT  2.268 41.251 32.958 42.025 ;
     RECT  2.268 42.025 33.534 42.061 ;
     RECT  46.728 41.947 46.746 42.077 ;
     RECT  2.268 42.061 33.606 42.173 ;
     RECT  50.724 41.881 57.006 42.179 ;
     RECT  12.168 42.173 33.606 42.187 ;
     RECT  34.38 38.849 45.897 42.187 ;
     RECT  49.968 41.369 49.986 42.187 ;
     RECT  50.724 42.179 51.297 42.187 ;
     RECT  58.68 41.819 58.806 42.215 ;
     RECT  52.164 42.179 57.006 42.223 ;
     RECT  52.164 42.223 57.654 42.283 ;
     RECT  49.968 42.187 51.297 42.449 ;
     RECT  2.268 42.173 11.43 42.475 ;
     RECT  49.968 42.449 49.986 42.485 ;
     RECT  58.68 42.215 58.734 42.485 ;
     RECT  2.232 42.475 11.43 42.629 ;
     RECT  0.108 41.933 0.126 42.667 ;
     RECT  46.764 42.601 46.782 42.719 ;
     RECT  6.408 42.629 11.43 42.755 ;
     RECT  52.164 42.283 57.69 42.763 ;
     RECT  58.68 42.485 58.698 42.763 ;
     RECT  1.152 40.795 1.314 42.859 ;
     RECT  2.232 42.629 5.67 42.859 ;
     RECT  12.168 42.187 45.897 42.961 ;
     RECT  52.164 42.763 58.698 43.025 ;
     RECT  50.724 42.449 51.297 43.033 ;
     RECT  52.164 43.025 58.122 43.033 ;
     RECT  11.808 42.961 45.897 43.133 ;
     RECT  6.408 42.755 10.998 43.259 ;
     RECT  1.152 42.859 5.67 43.439 ;
     RECT  1.152 43.439 1.206 43.529 ;
     RECT  6.696 43.259 10.998 43.609 ;
     RECT  11.808 43.133 13.497 43.609 ;
     RECT  50.724 43.033 58.122 43.627 ;
     RECT  2.232 43.439 5.67 43.799 ;
     RECT  6.696 43.609 13.497 43.871 ;
     RECT  7.02 43.871 9.81 43.979 ;
     RECT  10.836 43.871 11.106 43.979 ;
     RECT  11.88 43.871 13.497 43.979 ;
     RECT  50.328 43.627 58.122 44.011 ;
     RECT  12.636 43.979 13.497 44.105 ;
     RECT  10.836 43.979 10.854 44.249 ;
     RECT  2.232 43.799 5.346 44.339 ;
     RECT  46.8 43.681 46.818 44.339 ;
     RECT  50.328 44.011 58.806 44.383 ;
     RECT  50.004 44.383 58.806 44.429 ;
     RECT  11.88 43.979 11.898 44.483 ;
     RECT  2.232 44.339 4.95 44.519 ;
     RECT  2.34 44.519 4.95 44.609 ;
     RECT  50.148 44.429 58.806 44.779 ;
     RECT  1.188 43.529 1.206 44.879 ;
     RECT  2.34 44.609 4.77 44.879 ;
     RECT  7.02 43.979 8.946 44.951 ;
     RECT  50.148 44.779 58.878 44.951 ;
     RECT  50.148 44.951 58.806 44.987 ;
     RECT  4.752 44.879 4.77 45.023 ;
     RECT  50.148 44.987 58.77 45.059 ;
     RECT  0.108 42.667 0.198 45.149 ;
     RECT  2.34 44.879 3.978 45.221 ;
     RECT  7.632 44.951 8.946 45.221 ;
     RECT  3.636 45.221 3.978 45.293 ;
     RECT  46.8 45.229 46.818 45.329 ;
     RECT  2.34 45.221 2.697 45.455 ;
     RECT  0.18 45.149 0.198 45.527 ;
     RECT  3.636 45.293 3.654 45.869 ;
     RECT  50.148 45.059 58.734 45.931 ;
     RECT  50.148 45.931 58.77 45.995 ;
     RECT  53.136 45.995 58.77 46.123 ;
     RECT  53.136 46.123 58.806 46.219 ;
     RECT  46.8 46.237 46.926 46.267 ;
     RECT  46.8 46.267 46.998 46.309 ;
     RECT  46.8 46.309 47.034 46.363 ;
     RECT  46.764 46.363 47.034 46.397 ;
     RECT  46.764 46.397 46.854 46.409 ;
     RECT  53.136 46.219 58.842 46.499 ;
     RECT  50.148 45.995 52.398 46.507 ;
     RECT  46.8 46.409 46.854 46.571 ;
     RECT  46.8 46.571 46.818 46.679 ;
     RECT  49.788 46.507 52.398 46.733 ;
     RECT  50.688 46.733 52.398 46.741 ;
     RECT  53.136 46.499 58.806 46.741 ;
     RECT  50.688 46.741 58.806 46.805 ;
     RECT  13.215 44.105 13.497 47.281 ;
     RECT  14.256 43.133 45.897 47.281 ;
     RECT  12.024 47.131 12.042 47.309 ;
     RECT  50.796 46.805 58.806 47.563 ;
     RECT  13.215 47.281 45.897 47.579 ;
     RECT  49.788 46.733 49.95 47.579 ;
     RECT  46.764 47.317 46.782 47.587 ;
     RECT  50.796 47.563 58.842 47.623 ;
     RECT  50.328 47.623 58.842 47.947 ;
     RECT  46.764 47.587 46.926 48.029 ;
     RECT  46.764 48.029 46.854 48.191 ;
     RECT  50.328 47.947 58.878 48.299 ;
     RECT  50.328 48.299 51.57 48.389 ;
     RECT  50.724 48.389 51.57 48.425 ;
     RECT  50.724 48.425 51.297 48.659 ;
     RECT  52.452 48.299 58.878 48.695 ;
     RECT  52.452 48.695 57.618 48.929 ;
     RECT  58.392 48.695 58.878 49.001 ;
     RECT  52.452 48.929 52.47 49.199 ;
     RECT  58.86 49.001 58.878 49.343 ;
     RECT  53.208 48.929 57.618 49.469 ;
     RECT  53.208 49.469 57.078 50.009 ;
     RECT  53.208 50.009 56.862 50.081 ;
     RECT  53.208 50.081 56.697 50.351 ;
     RECT  53.208 50.351 55.062 50.423 ;
     RECT  55.872 50.351 56.697 50.423 ;
     RECT  53.208 50.423 54.27 50.459 ;
     RECT  55.044 50.423 55.062 50.459 ;
     RECT  53.712 50.459 54.27 50.549 ;
     RECT  9.684 43.979 9.81 51.431 ;
     RECT  7.815 45.221 8.946 52.079 ;
     RECT  13.215 47.579 13.497 54.409 ;
     RECT  14.256 47.579 45.897 54.409 ;
     RECT  7.815 52.079 8.766 54.473 ;
     RECT  9.792 51.431 9.81 54.509 ;
     RECT  13.215 54.409 45.897 55.831 ;
     RECT  13.104 55.831 45.897 55.985 ;
     RECT  2.415 45.455 2.697 56.987 ;
     RECT  7.815 54.473 8.097 56.987 ;
     RECT  13.215 55.985 45.897 56.987 ;
     RECT  51.015 48.659 51.297 56.987 ;
     RECT  56.415 50.423 56.697 56.987 ;
     RECT  13.215 56.987 45.705 57.029 ;
     RECT  13.215 57.029 44.118 57.053 ;
     RECT  13.215 57.053 26.406 57.065 ;
     RECT  27.288 57.053 44.118 57.065 ;
     RECT  27.288 57.065 39.438 57.101 ;
     RECT  40.215 57.065 44.118 57.101 ;
     RECT  44.892 57.029 45.705 57.101 ;
     RECT  18.288 57.065 26.406 57.149 ;
     RECT  27.288 57.101 27.99 57.149 ;
     RECT  40.215 57.101 44.046 57.149 ;
     RECT  18.615 57.149 26.406 57.173 ;
     RECT  28.908 57.101 39.402 57.173 ;
     RECT  28.908 57.173 36.45 57.197 ;
     RECT  42.552 57.149 44.046 57.197 ;
     RECT  13.215 57.065 16.722 57.209 ;
     RECT  19.872 57.173 26.406 57.209 ;
     RECT  27.432 57.149 27.99 57.209 ;
     RECT  37.548 57.173 39.402 57.209 ;
     RECT  40.215 57.149 41.814 57.209 ;
     RECT  42.552 57.197 43.29 57.209 ;
     RECT  19.872 57.209 22.122 57.245 ;
     RECT  23.292 57.209 25.758 57.245 ;
     RECT  37.548 57.209 37.566 57.245 ;
     RECT  41.364 57.209 41.814 57.245 ;
     RECT  45 57.101 45.705 57.245 ;
     RECT  2.415 56.987 2.505 57.257 ;
     RECT  7.815 56.987 7.905 57.257 ;
     RECT  13.215 57.209 16.29 57.257 ;
     RECT  18.615 57.173 19.098 57.257 ;
     RECT  29.415 57.197 36.45 57.257 ;
     RECT  40.215 57.209 40.554 57.257 ;
     RECT  45.615 57.245 45.705 57.257 ;
     RECT  51.015 56.987 51.105 57.257 ;
     RECT  56.415 56.987 56.505 57.257 ;
     RECT  22.104 57.245 22.122 57.293 ;
     RECT  44.028 57.197 44.046 57.293 ;
     RECT  38.844 57.209 39.258 57.341 ;
     RECT  23.292 57.245 24.174 57.389 ;
     RECT  42.552 57.209 42.678 57.389 ;
     RECT  13.752 57.257 16.29 57.485 ;
     RECT  18.9 57.257 19.098 57.533 ;
     RECT  23.292 57.389 23.382 57.533 ;
     RECT  30.024 57.257 34.398 57.533 ;
     RECT  13.752 57.485 16.254 57.581 ;
     RECT  18.9 57.533 18.918 57.581 ;
     RECT  20.412 57.245 21.114 57.581 ;
     RECT  23.292 57.533 23.31 57.581 ;
     RECT  24.156 57.389 24.174 57.581 ;
     RECT  25.2 57.245 25.758 57.581 ;
     RECT  27.432 57.209 27.846 57.581 ;
     RECT  30.024 57.533 32.022 57.581 ;
     RECT  33.012 57.533 33.462 57.581 ;
     RECT  34.272 57.533 34.29 57.581 ;
     RECT  35.136 57.257 36.45 57.581 ;
     RECT  41.364 57.245 41.382 57.581 ;
     RECT  14.148 57.581 14.778 58.157 ;
     RECT  25.74 57.581 25.758 58.157 ;
     RECT  30.78 57.581 31.266 58.157 ;
     RECT  40.536 57.257 40.554 58.157 ;
     RECT  42.66 57.389 42.678 58.157 ;
     RECT  14.58 58.157 14.598 58.205 ;
     RECT  15.696 57.581 15.714 58.205 ;
     RECT  30.78 58.157 30.798 58.685 ;
     RECT  20.88 57.581 20.898 58.733 ;
     RECT  23.76 58.987 23.778 59.117 ;
     RECT  14.652 59.035 14.67 59.213 ;
     RECT  17.892 59.035 17.91 59.213 ;
     RECT  23.076 59.179 23.094 59.309 ;
     RECT  27.432 57.581 27.45 59.309 ;
     RECT  30.384 59.131 30.402 59.309 ;
     RECT  36.612 59.131 36.63 59.309 ;
     RECT  38.196 59.179 38.214 59.309 ;
     RECT  40.428 59.179 40.446 59.309 ;
    LAYER M4 ;
     RECT  0.06 14.16 0.137 43.272 ;
     RECT  0.137 14.256 0.569 43.272 ;
     RECT  0.569 14.64 1.253 43.272 ;
     RECT  1.253 14.64 2.293 43.176 ;
     RECT  2.293 14.64 2.408 43.368 ;
     RECT  2.408 2.148 2.512 57.252 ;
     RECT  2.512 2.418 2.704 56.982 ;
     RECT  2.704 40.56 2.837 43.368 ;
     RECT  2.704 15.264 3.769 39.576 ;
     RECT  2.837 40.56 3.769 43.128 ;
     RECT  3.769 15.264 4.129 43.128 ;
     RECT  4.129 15.264 4.493 43.32 ;
     RECT  4.493 15.408 4.781 39.864 ;
     RECT  4.781 15.696 4.889 39.864 ;
     RECT  4.889 15.696 5.033 38.664 ;
     RECT  5.033 15.696 5.105 21.24 ;
     RECT  4.889 39.84 5.141 39.864 ;
     RECT  5.105 15.888 5.177 21.24 ;
     RECT  5.177 15.888 5.213 17.16 ;
     RECT  4.493 40.944 5.321 43.32 ;
     RECT  5.033 22.464 5.357 38.664 ;
     RECT  5.321 41.52 5.393 43.32 ;
     RECT  5.213 16.56 5.429 17.16 ;
     RECT  5.393 42.672 5.465 43.32 ;
     RECT  5.177 18.288 5.645 21.24 ;
     RECT  5.357 22.512 5.645 38.664 ;
     RECT  5.645 22.8 5.753 38.136 ;
     RECT  5.645 18.288 5.789 21.048 ;
     RECT  5.753 22.8 6.005 37.224 ;
     RECT  6.005 22.8 6.041 34.92 ;
     RECT  5.429 16.992 6.253 17.16 ;
     RECT  6.181 18.144 6.253 18.168 ;
     RECT  5.789 19.2 6.257 21.048 ;
     RECT  5.393 41.52 6.757 41.592 ;
     RECT  6.716 38.592 6.803 38.616 ;
     RECT  6.041 22.8 6.829 33.576 ;
     RECT  6.757 41.376 6.829 41.592 ;
     RECT  5.465 43.296 6.829 43.32 ;
     RECT  6.505 15.456 6.865 15.48 ;
     RECT  6.253 16.992 6.865 18.168 ;
     RECT  6.257 19.2 6.865 21 ;
     RECT  6.829 41.376 6.865 41.88 ;
     RECT  6.829 42.912 6.865 43.32 ;
     RECT  6.865 15.36 6.937 15.48 ;
     RECT  6.005 36.144 6.937 37.224 ;
     RECT  6.829 22.704 7.045 33.576 ;
     RECT  6.041 34.656 7.045 34.92 ;
     RECT  6.937 15.024 7.117 15.48 ;
     RECT  6.865 16.992 7.117 21 ;
     RECT  7.045 22.704 7.153 34.92 ;
     RECT  7.117 15.024 7.189 21 ;
     RECT  6.433 39.792 7.297 39.816 ;
     RECT  7.153 21.984 7.333 34.92 ;
     RECT  6.937 36.144 7.333 38.136 ;
     RECT  7.189 14.592 7.441 21 ;
     RECT  7.333 21.984 7.441 38.136 ;
     RECT  7.441 14.592 7.808 38.136 ;
     RECT  7.297 39.312 7.808 39.816 ;
     RECT  6.865 41.376 7.808 43.32 ;
     RECT  7.808 2.148 7.912 57.252 ;
     RECT  7.912 2.418 8.104 56.982 ;
     RECT  8.104 39.264 8.741 43.56 ;
     RECT  8.104 15.024 8.813 20.472 ;
     RECT  8.813 15.024 8.885 19.464 ;
     RECT  8.885 19.248 8.963 19.464 ;
     RECT  8.104 33.792 8.993 38.28 ;
     RECT  8.104 21.792 9.209 28.44 ;
     RECT  8.813 20.448 9.253 20.472 ;
     RECT  9.209 21.792 9.317 24.552 ;
     RECT  9.253 20.448 9.34 20.76 ;
     RECT  8.741 39.264 9.389 43.368 ;
     RECT  8.993 34.656 9.493 38.28 ;
     RECT  9.389 39.264 9.493 40.2 ;
     RECT  9.317 21.792 9.785 23.448 ;
     RECT  9.493 34.656 9.785 40.2 ;
     RECT  9.209 25.536 9.889 28.44 ;
     RECT  8.104 29.568 9.889 32.472 ;
     RECT  8.963 19.248 10.033 19.272 ;
     RECT  9.34 20.448 10.033 20.472 ;
     RECT  9.785 21.984 10.109 23.448 ;
     RECT  8.885 15.024 10.141 18.168 ;
     RECT  9.317 24.528 10.393 24.552 ;
     RECT  9.889 25.536 10.393 32.472 ;
     RECT  9.785 35.424 10.609 40.2 ;
     RECT  9.389 41.184 10.609 43.368 ;
     RECT  10.609 35.424 10.753 43.368 ;
     RECT  10.753 34.752 10.789 43.368 ;
     RECT  10.141 14.976 10.825 18.168 ;
     RECT  10.393 24.528 10.825 32.472 ;
     RECT  10.825 14.448 10.837 18.168 ;
     RECT  10.033 19.248 10.837 20.472 ;
     RECT  10.825 23.856 10.837 32.472 ;
     RECT  10.717 33.504 10.837 33.528 ;
     RECT  9.925 52.176 11.029 52.2 ;
     RECT  10.837 14.448 11.045 20.472 ;
     RECT  11.045 14.928 11.113 20.472 ;
     RECT  10.789 34.752 11.117 43.56 ;
     RECT  11.029 52.176 11.173 52.296 ;
     RECT  10.837 23.856 11.189 33.528 ;
     RECT  10.109 21.984 11.225 22.872 ;
     RECT  10.213 50.928 11.317 50.952 ;
     RECT  11.189 23.952 11.329 33.528 ;
     RECT  11.117 34.752 11.329 42.456 ;
     RECT  11.113 14.928 11.363 20.712 ;
     RECT  11.329 23.952 11.459 42.456 ;
     RECT  11.459 23.952 11.549 31.992 ;
     RECT  11.363 15.312 11.585 20.712 ;
     RECT  11.585 15.456 11.621 17.784 ;
     RECT  11.549 23.952 11.621 24.552 ;
     RECT  11.225 21.984 11.756 22.824 ;
     RECT  11.459 33.072 11.765 42.456 ;
     RECT  11.585 19.008 11.801 20.712 ;
     RECT  11.756 21.792 11.873 22.824 ;
     RECT  11.873 21.792 11.941 22.2 ;
     RECT  11.549 25.536 11.981 31.992 ;
     RECT  11.765 34.224 12.205 42.456 ;
     RECT  12.205 38.256 12.265 42.456 ;
     RECT  11.621 15.696 12.553 17.784 ;
     RECT  12.265 38.256 13.093 42.504 ;
     RECT  11.117 43.536 13.093 43.56 ;
     RECT  11.701 47.136 13.093 47.16 ;
     RECT  12.553 15.696 13.208 18.024 ;
     RECT  11.801 19.008 13.208 20.472 ;
     RECT  11.941 21.648 13.208 22.2 ;
     RECT  11.621 23.952 13.208 24.072 ;
     RECT  11.981 25.584 13.208 31.992 ;
     RECT  11.765 33.072 13.208 33.192 ;
     RECT  12.205 34.224 13.208 37.128 ;
     RECT  13.093 38.256 13.208 43.56 ;
     RECT  13.093 47.136 13.208 47.352 ;
     RECT  11.317 50.4 13.208 50.952 ;
     RECT  11.173 52.176 13.208 52.584 ;
     RECT  13.208 2.148 13.312 57.252 ;
     RECT  13.312 2.418 13.504 57.252 ;
     RECT  13.504 42.48 13.565 43.032 ;
     RECT  13.504 25.152 13.601 26.616 ;
     RECT  13.504 27.648 13.673 33.096 ;
     RECT  13.504 14.928 13.709 18.024 ;
     RECT  13.504 53.568 13.741 57.252 ;
     RECT  13.709 14.928 13.817 17.88 ;
     RECT  13.817 14.928 13.889 17.64 ;
     RECT  13.504 19.008 13.889 19.848 ;
     RECT  13.504 22.08 13.925 23.448 ;
     RECT  13.504 34.368 13.948 41.4 ;
     RECT  13.673 27.648 13.955 32.76 ;
     RECT  13.889 14.928 13.997 14.952 ;
     RECT  13.741 53.568 14.137 57.576 ;
     RECT  13.565 42.48 14.177 42.504 ;
     RECT  13.948 34.368 14.249 35.544 ;
     RECT  13.601 25.152 14.285 26.376 ;
     RECT  13.889 19.008 14.357 19.704 ;
     RECT  14.249 34.608 14.393 35.544 ;
     RECT  13.504 47.136 14.531 47.352 ;
     RECT  13.504 50.4 14.533 50.952 ;
     RECT  13.504 52.176 14.533 52.584 ;
     RECT  14.137 53.568 14.569 58.152 ;
     RECT  14.393 34.608 14.573 34.632 ;
     RECT  14.531 47.136 14.579 47.16 ;
     RECT  14.569 53.568 14.581 58.2 ;
     RECT  14.581 53.568 14.597 58.968 ;
     RECT  13.955 30.096 14.681 32.76 ;
     RECT  14.597 53.568 14.681 59.208 ;
     RECT  14.681 53.568 14.723 59.064 ;
     RECT  14.285 25.728 14.753 26.376 ;
     RECT  13.948 36.576 14.771 41.4 ;
     RECT  14.723 53.568 14.771 58.968 ;
     RECT  14.533 50.4 14.773 52.584 ;
     RECT  14.771 53.568 14.773 58.2 ;
     RECT  13.889 16.608 14.789 17.64 ;
     RECT  13.925 23.424 14.789 23.448 ;
     RECT  14.771 37.584 14.819 41.4 ;
     RECT  14.753 25.776 14.825 26.376 ;
     RECT  14.681 30.096 15.077 31.8 ;
     RECT  13.955 27.648 15.325 28.44 ;
     RECT  15.077 30.096 15.325 31.656 ;
     RECT  14.819 37.968 15.329 41.4 ;
     RECT  14.773 50.4 16.211 58.2 ;
     RECT  16.211 50.4 16.265 57.576 ;
     RECT  16.265 50.4 16.301 57.48 ;
     RECT  16.301 50.4 16.403 57.144 ;
     RECT  16.657 34.8 16.769 34.824 ;
     RECT  15.325 27.648 17.557 31.656 ;
     RECT  17.701 58.896 17.843 59.304 ;
     RECT  17.843 58.896 17.891 59.256 ;
     RECT  17.891 58.992 18.035 59.256 ;
     RECT  17.557 27.648 18.061 31.992 ;
     RECT  18.061 27.648 18.205 32.04 ;
     RECT  16.403 50.4 18.229 57.048 ;
     RECT  14.789 16.608 18.608 16.632 ;
     RECT  14.789 17.616 18.608 17.64 ;
     RECT  14.357 19.008 18.608 19.032 ;
     RECT  13.925 22.08 18.608 22.104 ;
     RECT  14.825 25.776 18.608 25.992 ;
     RECT  18.205 27.648 18.608 32.232 ;
     RECT  14.771 36.576 18.608 36.6 ;
     RECT  15.329 38.4 18.608 41.4 ;
     RECT  16.837 42.72 18.608 42.744 ;
     RECT  18.229 50.4 18.608 57.144 ;
     RECT  18.035 59.184 18.611 59.256 ;
     RECT  18.611 59.184 18.707 59.208 ;
     RECT  18.608 2.148 18.712 57.252 ;
     RECT  18.712 2.418 18.757 57.252 ;
     RECT  18.757 2.418 18.853 57.384 ;
     RECT  18.853 2.418 18.889 57.432 ;
     RECT  18.889 2.418 18.904 57.576 ;
     RECT  18.904 43.104 19.073 43.128 ;
     RECT  18.904 49.008 19.132 49.368 ;
     RECT  18.904 46.896 19.139 46.92 ;
     RECT  18.904 50.4 19.187 57.576 ;
     RECT  18.904 31.152 19.253 32.472 ;
     RECT  19.132 49.008 19.253 49.032 ;
     RECT  19.093 58.656 19.283 58.68 ;
     RECT  19.253 31.152 19.505 32.28 ;
     RECT  18.904 38.4 20.149 41.4 ;
     RECT  20.113 47.28 20.197 47.304 ;
     RECT  19.187 50.4 20.197 57.24 ;
     RECT  20.149 38.4 20.243 42.216 ;
     RECT  20.243 38.4 20.297 41.208 ;
     RECT  20.243 42.192 20.821 42.216 ;
     RECT  20.197 43.824 20.821 43.848 ;
     RECT  20.653 44.976 21.061 45 ;
     RECT  21.061 44.976 21.107 45.72 ;
     RECT  20.297 38.448 21.125 41.208 ;
     RECT  21.125 38.64 21.229 41.208 ;
     RECT  20.821 42.192 21.229 43.848 ;
     RECT  20.869 58.704 21.299 58.728 ;
     RECT  21.229 38.64 21.377 43.848 ;
     RECT  20.197 50.4 21.395 57.576 ;
     RECT  21.193 47.856 21.596 47.88 ;
     RECT  21.596 47.184 21.601 47.88 ;
     RECT  21.395 50.4 21.637 57.288 ;
     RECT  21.601 47.184 21.827 47.496 ;
     RECT  21.637 50.16 22.133 57.288 ;
     RECT  22.133 50.16 22.165 57.192 ;
     RECT  18.904 25.776 22.345 25.992 ;
     RECT  21.377 38.784 22.645 43.848 ;
     RECT  22.645 38.784 22.7 44.376 ;
     RECT  21.013 34.944 22.741 34.968 ;
     RECT  18.904 36.576 22.741 36.6 ;
     RECT  22.7 38.64 22.787 44.376 ;
     RECT  19.969 33.408 22.813 33.432 ;
     RECT  18.904 22.08 22.849 22.104 ;
     RECT  22.813 33.312 22.853 33.432 ;
     RECT  22.849 22.08 22.997 23.016 ;
     RECT  22.309 59.232 23.029 59.256 ;
     RECT  23.029 59.184 23.065 59.256 ;
     RECT  23.065 59.184 23.149 59.304 ;
     RECT  22.165 50.016 23.237 57.192 ;
     RECT  20.725 24.144 23.533 24.168 ;
     RECT  23.149 59.184 23.557 59.256 ;
     RECT  23.557 59.088 23.701 59.256 ;
     RECT  23.701 58.992 23.789 59.256 ;
     RECT  23.789 59.088 23.833 59.256 ;
     RECT  23.533 24.096 23.857 24.168 ;
     RECT  22.997 22.08 24.001 22.104 ;
     RECT  18.904 16.608 24.008 16.632 ;
     RECT  18.904 17.616 24.008 17.64 ;
     RECT  18.904 19.008 24.008 19.032 ;
     RECT  24.001 22.08 24.008 22.776 ;
     RECT  23.857 24.096 24.008 24.216 ;
     RECT  22.345 25.776 24.008 26.616 ;
     RECT  18.904 27.648 24.008 30.12 ;
     RECT  19.505 31.152 24.008 32.232 ;
     RECT  22.853 33.312 24.008 33.336 ;
     RECT  22.741 34.944 24.008 36.6 ;
     RECT  22.787 39.552 24.008 44.376 ;
     RECT  21.107 45.696 24.008 45.72 ;
     RECT  22.597 46.896 24.008 46.92 ;
     RECT  23.237 50.016 24.008 57.576 ;
     RECT  24.008 2.148 24.112 57.576 ;
     RECT  24.112 2.418 24.185 57.576 ;
     RECT  24.185 2.418 24.304 57.432 ;
     RECT  23.833 59.184 24.419 59.256 ;
     RECT  24.304 45.696 24.581 46.92 ;
     RECT  24.304 24.096 24.653 24.216 ;
     RECT  24.304 25.776 25.049 30.12 ;
     RECT  24.581 46.128 25.091 46.92 ;
     RECT  24.304 49.536 25.189 57.432 ;
     RECT  24.304 16.608 25.265 16.632 ;
     RECT  25.189 49.536 25.331 57.576 ;
     RECT  24.304 22.08 25.333 22.92 ;
     RECT  24.653 24.096 25.333 24.168 ;
     RECT  25.331 49.536 25.523 57.144 ;
     RECT  25.523 49.536 25.561 50.76 ;
     RECT  25.561 49.872 25.841 50.76 ;
     RECT  24.419 59.232 25.861 59.256 ;
     RECT  24.304 39.552 25.945 44.376 ;
     RECT  25.861 59.136 25.955 59.256 ;
     RECT  25.955 59.136 26.051 59.16 ;
     RECT  24.304 34.944 26.129 36.552 ;
     RECT  25.523 51.792 26.273 57.144 ;
     RECT  25.729 58.128 26.291 58.152 ;
     RECT  25.333 22.08 26.341 24.168 ;
     RECT  25.049 25.776 26.341 26.616 ;
     RECT  26.273 53.52 26.437 57.144 ;
     RECT  25.945 39.552 26.449 45.048 ;
     RECT  25.091 46.176 26.449 46.92 ;
     RECT  25.841 50.016 26.485 50.76 ;
     RECT  26.273 51.792 26.485 52.488 ;
     RECT  26.449 39.552 26.636 46.92 ;
     RECT  26.485 50.016 26.713 52.488 ;
     RECT  26.677 48.48 26.809 48.504 ;
     RECT  26.341 22.08 26.813 26.616 ;
     RECT  26.437 53.52 26.921 57.576 ;
     RECT  26.813 25.584 26.993 26.616 ;
     RECT  24.304 19.008 27.205 19.032 ;
     RECT  26.813 22.08 27.245 24.504 ;
     RECT  26.636 39.552 27.277 46.968 ;
     RECT  26.809 48.48 27.277 49.032 ;
     RECT  27.277 39.552 27.301 49.032 ;
     RECT  26.713 50.016 27.301 52.44 ;
     RECT  27.377 59.28 27.461 59.304 ;
     RECT  26.921 53.904 27.713 57.576 ;
     RECT  27.713 54.048 27.857 57.576 ;
     RECT  27.245 24.144 27.893 24.504 ;
     RECT  27.845 7.968 27.929 7.992 ;
     RECT  27.301 39.552 28.021 52.44 ;
     RECT  24.304 17.616 28.037 17.64 ;
     RECT  28.021 39.552 28.109 52.728 ;
     RECT  27.781 5.616 28.285 5.64 ;
     RECT  28.109 46.752 28.307 52.728 ;
     RECT  27.817 3.696 28.405 3.72 ;
     RECT  28.357 0.096 28.441 0.12 ;
     RECT  28.307 51.696 28.453 52.728 ;
     RECT  28.249 1.728 28.499 1.752 ;
     RECT  28.885 59.232 28.933 59.256 ;
     RECT  28.453 51.696 29.077 53.064 ;
     RECT  27.857 54.048 29.077 57.192 ;
     RECT  27.245 22.08 29.149 23.016 ;
     RECT  27.893 24.144 29.149 24.216 ;
     RECT  28.933 58.992 29.221 59.256 ;
     RECT  26.993 25.776 29.257 26.616 ;
     RECT  25.049 27.648 29.257 30.12 ;
     RECT  29.077 51.696 29.269 57.192 ;
     RECT  29.221 58.56 29.363 59.256 ;
     RECT  28.405 3.312 29.408 3.72 ;
     RECT  28.285 4.848 29.408 5.64 ;
     RECT  28.405 7.44 29.408 7.8 ;
     RECT  27.205 19.008 29.408 19.416 ;
     RECT  29.149 22.08 29.408 24.216 ;
     RECT  29.257 25.776 29.408 30.12 ;
     RECT  24.304 31.152 29.408 32.232 ;
     RECT  24.304 33.408 29.408 33.432 ;
     RECT  26.129 34.944 29.408 34.968 ;
     RECT  26.129 36.528 29.408 36.552 ;
     RECT  28.109 39.552 29.408 45.768 ;
     RECT  28.307 46.752 29.408 50.328 ;
     RECT  29.269 51.36 29.408 57.192 ;
     RECT  29.408 2.148 29.512 57.252 ;
     RECT  29.512 2.418 29.704 57.252 ;
     RECT  29.704 48.912 29.945 49.224 ;
     RECT  29.704 50.304 29.981 50.328 ;
     RECT  29.704 39.552 30.179 47.064 ;
     RECT  29.363 58.656 30.373 59.256 ;
     RECT  30.373 58.656 30.457 59.304 ;
     RECT  29.704 54.048 30.629 56.472 ;
     RECT  29.704 52.992 30.697 53.064 ;
     RECT  30.629 54.048 30.697 55.416 ;
     RECT  29.704 22.08 30.769 24.216 ;
     RECT  29.704 33.408 30.769 33.432 ;
     RECT  30.179 39.552 30.773 46.872 ;
     RECT  30.769 21.984 30.809 24.216 ;
     RECT  30.769 33.312 30.809 33.432 ;
     RECT  30.457 58.656 30.809 59.256 ;
     RECT  30.697 52.992 30.812 55.416 ;
     RECT  29.893 57.552 30.853 57.576 ;
     RECT  30.812 52.464 30.899 55.416 ;
     RECT  30.629 56.448 30.917 56.472 ;
     RECT  30.853 57.504 31.229 57.576 ;
     RECT  31.229 57.408 31.237 57.576 ;
     RECT  31.237 57.408 31.313 58.152 ;
     RECT  29.704 51.36 31.417 51.432 ;
     RECT  29.704 19.008 31.529 19.032 ;
     RECT  30.697 50.064 31.561 50.088 ;
     RECT  31.417 51.36 31.561 51.912 ;
     RECT  31.561 50.064 31.601 51.912 ;
     RECT  31.601 51.888 31.619 51.912 ;
     RECT  30.773 46.848 31.628 46.872 ;
     RECT  31.313 57.456 31.667 58.152 ;
     RECT  30.809 22.992 31.861 24.216 ;
     RECT  31.628 46.848 31.861 47.64 ;
     RECT  30.899 52.992 31.889 55.416 ;
     RECT  29.704 25.776 31.907 26.616 ;
     RECT  31.889 52.992 31.997 53.016 ;
     RECT  31.889 54.048 32.101 55.416 ;
     RECT  32.101 54.048 32.177 55.56 ;
     RECT  32.177 55.536 32.188 55.56 ;
     RECT  30.809 59.232 32.245 59.256 ;
     RECT  30.773 39.552 32.317 45.768 ;
     RECT  31.861 46.848 32.317 46.872 ;
     RECT  32.245 59.136 32.435 59.256 ;
     RECT  32.435 59.232 32.483 59.256 ;
     RECT  31.667 57.456 32.497 57.576 ;
     RECT  29.945 48.912 32.677 48.936 ;
     RECT  31.601 50.064 32.677 50.808 ;
     RECT  32.309 47.856 32.75 47.928 ;
     RECT  32.197 55.728 32.869 55.896 ;
     RECT  32.497 57.024 32.869 57.576 ;
     RECT  32.101 51.936 32.897 51.96 ;
     RECT  32.75 47.904 32.957 47.928 ;
     RECT  32.677 48.912 32.957 50.808 ;
     RECT  33.013 53.04 33.061 53.064 ;
     RECT  32.177 54.048 33.061 54.552 ;
     RECT  33.061 53.04 33.149 54.552 ;
     RECT  32.957 47.904 33.157 50.808 ;
     RECT  33.149 53.568 33.157 54.552 ;
     RECT  32.869 55.728 33.157 57.576 ;
     RECT  33.157 53.568 33.329 57.576 ;
     RECT  33.329 55.872 33.437 57.576 ;
     RECT  33.157 47.904 33.473 51.624 ;
     RECT  33.473 47.904 33.545 47.928 ;
     RECT  32.317 39.552 33.581 46.872 ;
     RECT  33.329 53.568 33.653 54.696 ;
     RECT  33.581 42.48 33.689 46.872 ;
     RECT  33.473 49.344 34.009 51.624 ;
     RECT  33.733 59.232 34.019 59.256 ;
     RECT  33.437 55.872 34.405 56.04 ;
     RECT  33.437 57.024 34.405 57.576 ;
     RECT  31.907 26.592 34.441 26.616 ;
     RECT  29.704 27.648 34.441 30.12 ;
     RECT  34.009 49.344 34.508 51.768 ;
     RECT  34.508 49.008 34.549 51.768 ;
     RECT  34.405 55.872 34.652 57.576 ;
     RECT  30.809 21.984 34.808 22.008 ;
     RECT  31.861 22.992 34.808 24.408 ;
     RECT  34.441 26.592 34.808 30.12 ;
     RECT  29.704 31.152 34.808 32.232 ;
     RECT  30.809 33.312 34.808 33.336 ;
     RECT  29.704 34.944 34.808 34.968 ;
     RECT  29.704 36.528 34.808 36.552 ;
     RECT  33.581 39.552 34.808 41.496 ;
     RECT  33.689 42.48 34.808 45.768 ;
     RECT  33.689 46.848 34.808 46.872 ;
     RECT  34.549 49.008 34.808 52.2 ;
     RECT  33.653 53.568 34.808 54.12 ;
     RECT  34.652 55.728 34.808 57.576 ;
     RECT  34.808 2.148 34.912 57.576 ;
     RECT  34.981 59.04 35.077 59.064 ;
     RECT  34.912 2.418 35.104 57.576 ;
     RECT  35.077 58.944 35.173 59.064 ;
     RECT  35.104 48.96 35.219 50.184 ;
     RECT  35.173 58.944 35.219 59.256 ;
     RECT  35.219 59.04 35.267 59.256 ;
     RECT  35.219 49.056 35.315 50.184 ;
     RECT  35.104 53.76 35.561 56.088 ;
     RECT  35.315 50.064 35.597 50.184 ;
     RECT  35.104 42.48 35.633 45.768 ;
     RECT  35.104 21.984 35.849 22.008 ;
     RECT  35.104 31.152 35.885 34.968 ;
     RECT  35.315 49.056 35.885 49.08 ;
     RECT  35.597 50.064 35.921 50.088 ;
     RECT  35.561 53.76 35.921 55.848 ;
     RECT  35.104 57.504 35.921 57.576 ;
     RECT  35.104 39.552 35.993 41.496 ;
     RECT  35.104 26.592 36.353 30.12 ;
     RECT  35.921 54.144 36.353 55.848 ;
     RECT  35.104 52.176 36.421 52.68 ;
     RECT  35.921 57.552 36.461 57.576 ;
     RECT  35.267 59.232 36.565 59.256 ;
     RECT  36.565 59.136 36.601 59.256 ;
     RECT  36.601 59.136 36.652 59.304 ;
     RECT  36.652 59.232 36.685 59.304 ;
     RECT  36.685 59.232 36.899 59.256 ;
     RECT  36.421 52.176 36.961 53.016 ;
     RECT  36.353 54.432 36.997 55.848 ;
     RECT  36.961 52.032 37.001 53.016 ;
     RECT  35.885 34.944 37.069 34.968 ;
     RECT  35.104 36.528 37.133 36.552 ;
     RECT  35.104 46.848 37.169 46.872 ;
     RECT  37.069 34.896 37.177 34.968 ;
     RECT  35.633 42.48 37.177 44.088 ;
     RECT  35.633 45.168 37.177 45.768 ;
     RECT  35.885 31.152 37.187 33.864 ;
     RECT  37.169 46.752 37.189 46.872 ;
     RECT  36.353 27.648 37.217 30.12 ;
     RECT  37.133 36.528 37.217 36.936 ;
     RECT  37.189 46.752 37.253 47.4 ;
     RECT  37.169 49.584 37.253 49.608 ;
     RECT  37.177 42.48 37.261 45.768 ;
     RECT  37.253 46.848 37.276 47.4 ;
     RECT  37.217 36.528 37.325 36.552 ;
     RECT  36.997 54.432 37.477 55.896 ;
     RECT  37.093 57.024 37.532 57.144 ;
     RECT  37.321 38.736 37.541 38.76 ;
     RECT  37.187 33.408 37.573 33.864 ;
     RECT  37.177 34.896 37.573 35.496 ;
     RECT  37.532 57.024 37.619 57.24 ;
     RECT  37.477 54.432 37.621 56.04 ;
     RECT  37.217 27.744 37.685 30.12 ;
     RECT  37.573 33.408 37.685 35.496 ;
     RECT  37.621 53.568 37.793 56.04 ;
     RECT  37.685 27.888 37.901 30.12 ;
     RECT  37.685 33.408 37.937 34.968 ;
     RECT  37.793 54.048 37.957 56.04 ;
     RECT  37.619 57.024 37.957 57.192 ;
     RECT  37.861 59.04 38.101 59.064 ;
     RECT  38.101 59.04 38.141 59.208 ;
     RECT  38.141 59.04 38.195 59.304 ;
     RECT  38.195 59.136 38.233 59.304 ;
     RECT  37.001 52.032 38.297 52.44 ;
     RECT  38.233 59.136 38.435 59.16 ;
     RECT  37.187 31.152 38.509 32.232 ;
     RECT  37.937 33.408 38.509 33.864 ;
     RECT  37.957 54.048 38.549 57.192 ;
     RECT  38.549 54.048 38.729 55.656 ;
     RECT  38.549 57.024 38.833 57.192 ;
     RECT  38.297 52.272 38.837 52.44 ;
     RECT  38.729 54.672 38.873 55.656 ;
     RECT  38.873 54.672 38.981 55.512 ;
     RECT  38.797 37.488 39.229 37.512 ;
     RECT  38.833 57.024 39.292 57.336 ;
     RECT  39.229 37.344 39.625 37.512 ;
     RECT  38.509 31.152 39.841 33.864 ;
     RECT  37.937 34.896 39.841 34.968 ;
     RECT  39.625 36.624 39.949 37.512 ;
     RECT  38.981 54.72 40.069 55.512 ;
     RECT  39.925 59.28 40.069 59.304 ;
     RECT  35.104 22.992 40.208 24.216 ;
     RECT  36.353 26.592 40.208 26.616 ;
     RECT  37.901 28.416 40.208 30.12 ;
     RECT  39.841 31.152 40.208 34.968 ;
     RECT  39.949 36.576 40.208 37.512 ;
     RECT  35.993 39.792 40.208 41.496 ;
     RECT  37.261 42.48 40.208 44.088 ;
     RECT  37.261 45.168 40.208 45.768 ;
     RECT  37.276 46.848 40.208 46.872 ;
     RECT  38.837 52.272 40.208 52.296 ;
     RECT  40.069 54.72 40.208 55.752 ;
     RECT  39.292 57.024 40.208 57.252 ;
     RECT  40.208 2.148 40.312 57.252 ;
     RECT  40.069 59.232 40.402 59.304 ;
     RECT  40.312 2.418 40.504 57.096 ;
     RECT  40.453 58.128 40.565 58.152 ;
     RECT  40.402 59.184 40.595 59.304 ;
     RECT  40.504 36.576 40.601 37.992 ;
     RECT  40.595 59.184 40.643 59.208 ;
     RECT  40.601 36.624 40.889 37.992 ;
     RECT  40.504 52.272 41.027 52.296 ;
     RECT  40.504 53.376 41.027 55.848 ;
     RECT  40.504 28.992 41.177 30.12 ;
     RECT  41.027 53.568 41.267 55.848 ;
     RECT  40.504 57.024 41.353 57.096 ;
     RECT  40.504 31.152 41.393 34.968 ;
     RECT  41.353 57.024 41.459 57.576 ;
     RECT  40.889 37.392 41.641 37.992 ;
     RECT  41.641 37.392 41.681 38.76 ;
     RECT  41.681 38.592 41.897 38.76 ;
     RECT  41.459 57.024 42.173 57.24 ;
     RECT  41.897 38.592 42.185 38.616 ;
     RECT  42.173 56.304 42.257 57.24 ;
     RECT  41.267 53.568 42.437 54.936 ;
     RECT  42.257 57.024 42.469 57.24 ;
     RECT  40.504 45.168 42.509 45.768 ;
     RECT  42.469 57.024 42.541 57.288 ;
     RECT  41.393 31.152 42.577 32.232 ;
     RECT  41.393 33.408 42.577 34.968 ;
     RECT  42.541 57.024 42.649 57.384 ;
     RECT  42.277 59.232 42.659 59.256 ;
     RECT  42.437 54.336 42.721 54.936 ;
     RECT  42.541 56.016 42.721 56.04 ;
     RECT  42.577 31.152 42.761 34.968 ;
     RECT  40.504 42.48 42.833 44.088 ;
     RECT  42.721 54.336 42.941 56.04 ;
     RECT  42.649 57.024 42.995 58.152 ;
     RECT  42.995 57.024 43.229 57.288 ;
     RECT  43.229 57.168 43.337 57.288 ;
     RECT  40.504 39.792 43.549 41.496 ;
     RECT  42.833 42.48 43.549 43.896 ;
     RECT  42.577 52.992 43.697 53.016 ;
     RECT  42.941 54.336 43.805 55.944 ;
     RECT  43.805 54.336 43.949 55.272 ;
     RECT  43.337 57.216 44.057 57.288 ;
     RECT  43.949 54.336 44.453 54.36 ;
     RECT  40.504 22.992 45.608 24.216 ;
     RECT  40.504 26.592 45.608 26.616 ;
     RECT  41.177 28.992 45.608 29.544 ;
     RECT  42.761 31.152 45.608 32.232 ;
     RECT  42.761 33.408 45.608 34.968 ;
     RECT  41.681 37.392 45.608 37.416 ;
     RECT  43.549 39.792 45.608 43.896 ;
     RECT  42.509 45.216 45.608 45.768 ;
     RECT  40.504 46.848 45.608 46.872 ;
     RECT  44.057 57.216 45.608 57.24 ;
     RECT  45.608 2.148 45.712 57.252 ;
     RECT  45.712 2.418 45.904 56.982 ;
     RECT  45.904 45.216 47.045 46.872 ;
     RECT  45.904 22.992 49.021 24.216 ;
     RECT  45.904 33.408 49.093 34.968 ;
     RECT  49.021 21.36 49.097 24.216 ;
     RECT  49.097 21.36 49.133 22.104 ;
     RECT  45.904 31.152 49.849 32.232 ;
     RECT  45.904 37.392 49.849 37.416 ;
     RECT  45.904 28.992 49.885 29.544 ;
     RECT  49.885 28.992 49.993 29.832 ;
     RECT  45.904 39.792 49.993 43.896 ;
     RECT  47.045 45.216 49.993 45.768 ;
     RECT  47.045 46.848 49.993 46.872 ;
     RECT  49.849 37.008 50.065 37.416 ;
     RECT  45.904 26.592 50.137 26.616 ;
     RECT  49.993 28.416 50.137 29.832 ;
     RECT  49.849 31.152 50.137 32.28 ;
     RECT  49.093 33.312 50.137 34.968 ;
     RECT  50.065 36.528 50.137 37.416 ;
     RECT  50.137 26.256 50.317 26.664 ;
     RECT  49.097 23.088 50.353 24.216 ;
     RECT  50.317 25.536 50.389 26.664 ;
     RECT  50.137 28.416 50.389 32.28 ;
     RECT  50.137 33.312 50.389 35.448 ;
     RECT  50.389 28.416 50.497 35.448 ;
     RECT  50.137 36.528 50.605 37.896 ;
     RECT  50.353 22.176 50.713 24.216 ;
     RECT  50.317 48.24 50.725 48.264 ;
     RECT  50.389 25.536 50.749 27.336 ;
     RECT  50.497 28.416 50.749 35.544 ;
     RECT  50.749 25.536 50.785 35.544 ;
     RECT  50.425 20.496 50.893 20.52 ;
     RECT  50.785 25.248 50.893 35.544 ;
     RECT  50.605 36.528 50.893 38.184 ;
     RECT  50.893 20.16 51.008 20.52 ;
     RECT  50.713 22.032 51.008 24.216 ;
     RECT  50.893 25.248 51.008 38.184 ;
     RECT  49.993 39.792 51.008 46.872 ;
     RECT  50.725 47.856 51.008 48.264 ;
     RECT  51.008 2.148 51.112 57.252 ;
     RECT  51.112 2.418 51.304 56.982 ;
     RECT  51.304 22.032 51.437 47.88 ;
     RECT  51.304 19.68 51.491 20.76 ;
     RECT  51.437 22.032 52.693 47.496 ;
     RECT  52.693 21.936 52.801 47.496 ;
     RECT  52.801 21.648 52.837 47.496 ;
     RECT  51.491 19.68 52.981 20.184 ;
     RECT  52.837 21.648 53.129 48.408 ;
     RECT  52.981 19.68 53.341 20.52 ;
     RECT  53.129 21.648 53.341 34.968 ;
     RECT  52.453 50.16 53.521 50.184 ;
     RECT  53.129 36.096 53.557 48.408 ;
     RECT  53.557 36.096 53.737 48.456 ;
     RECT  53.521 49.536 53.737 50.184 ;
     RECT  53.737 36.096 53.741 50.184 ;
     RECT  53.341 19.68 53.921 34.968 ;
     RECT  53.921 19.68 53.941 27.384 ;
     RECT  53.941 19.344 54.028 27.384 ;
     RECT  53.921 28.368 54.133 34.968 ;
     RECT  53.741 36.096 54.133 49.992 ;
     RECT  54.028 20.208 54.209 27.384 ;
     RECT  54.133 28.368 54.713 49.992 ;
     RECT  54.713 28.368 54.749 43.992 ;
     RECT  54.713 45.168 54.785 49.992 ;
     RECT  54.785 47.904 54.821 49.992 ;
     RECT  54.821 49.968 54.856 49.992 ;
     RECT  54.856 49.968 54.857 50.04 ;
     RECT  54.209 21.36 54.889 27.384 ;
     RECT  54.749 28.368 54.889 40.104 ;
     RECT  54.889 21.36 54.965 40.104 ;
     RECT  54.209 20.208 55.249 20.232 ;
     RECT  55.249 20.208 55.429 20.328 ;
     RECT  54.965 21.36 55.429 35.448 ;
     RECT  55.429 20.208 55.609 35.448 ;
     RECT  55.609 20.112 55.681 35.448 ;
     RECT  54.749 41.088 55.753 43.992 ;
     RECT  54.785 45.168 55.753 46.92 ;
     RECT  55.681 19.92 56.149 35.448 ;
     RECT  54.965 36.48 56.149 40.104 ;
     RECT  56.149 19.92 56.408 40.104 ;
     RECT  55.753 41.088 56.408 46.92 ;
     RECT  54.821 47.904 56.408 48.84 ;
     RECT  54.857 50.016 56.408 50.04 ;
     RECT  56.408 2.148 56.512 57.252 ;
     RECT  56.512 2.418 56.704 56.982 ;
     RECT  56.704 42.192 57.017 48.984 ;
     RECT  56.704 19.584 57.089 40.872 ;
     RECT  57.017 42.192 57.161 48.456 ;
     RECT  57.089 19.92 57.985 40.872 ;
     RECT  57.985 19.92 58.669 40.968 ;
     RECT  57.161 42.192 58.669 48.072 ;
     RECT  58.669 19.92 58.705 48.072 ;
     RECT  58.705 19.92 58.741 48.168 ;
     RECT  58.741 19.92 59.34 48.264 ;
    LAYER M5 ;
     RECT  28.272 0.016 28.488 1.763 ;
     RECT  2.4 2.137 2.52 2.151 ;
     RECT  7.8 2.137 7.92 2.151 ;
     RECT  13.2 2.137 13.32 2.151 ;
     RECT  18.6 2.137 18.72 2.151 ;
     RECT  24 2.137 24.12 2.151 ;
     RECT  29.4 2.137 29.52 2.151 ;
     RECT  34.8 2.137 34.92 2.151 ;
     RECT  40.2 2.137 40.32 2.151 ;
     RECT  45.6 2.137 45.72 2.151 ;
     RECT  51 2.137 51.12 2.151 ;
     RECT  56.4 2.137 56.52 2.151 ;
     RECT  28.272 1.763 28.296 3.301 ;
     RECT  29.4 2.151 29.712 3.301 ;
     RECT  28.272 3.301 29.712 7.957 ;
     RECT  10.224 14.965 10.248 15.253 ;
     RECT  11.328 14.917 11.352 15.253 ;
     RECT  10.224 15.253 11.352 15.349 ;
     RECT  7.8 2.151 8.112 15.397 ;
     RECT  7.68 15.397 8.112 15.493 ;
     RECT  7.68 15.493 8.952 16.259 ;
     RECT  1.152 17.941 1.176 18.563 ;
     RECT  0.144 18.421 0.168 18.803 ;
     RECT  27.888 7.957 29.712 19.427 ;
     RECT  7.8 16.259 8.952 19.475 ;
     RECT  9.936 15.349 11.352 19.621 ;
     RECT  13.2 2.151 13.512 19.621 ;
     RECT  51 2.151 51.312 19.669 ;
     RECT  9.936 19.621 13.512 20.387 ;
     RECT  53.952 19.333 53.976 20.531 ;
     RECT  56.4 2.151 56.712 20.677 ;
     RECT  7.8 19.475 8.712 20.725 ;
     RECT  9.936 20.387 11.352 20.725 ;
     RECT  56.4 20.677 56.808 21.349 ;
     RECT  56.4 21.349 56.952 21.491 ;
     RECT  7.8 20.725 11.352 21.781 ;
     RECT  12.528 20.387 13.512 21.781 ;
     RECT  7.8 21.781 13.512 22.211 ;
     RECT  4.128 22.597 4.152 22.739 ;
     RECT  9.936 22.211 11.832 22.835 ;
     RECT  2.4 2.151 2.712 23.557 ;
     RECT  26.88 22.933 26.904 23.795 ;
     RECT  7.8 22.211 8.712 23.845 ;
     RECT  56.4 21.491 56.712 23.893 ;
     RECT  2.4 23.557 2.808 23.939 ;
     RECT  51 19.669 51.48 25.045 ;
     RECT  51 25.045 52.248 25.141 ;
     RECT  6.864 23.845 8.712 25.475 ;
     RECT  13.2 22.211 13.512 25.573 ;
     RECT  51 25.141 52.44 25.621 ;
     RECT  31.872 24.373 31.896 25.765 ;
     RECT  31.728 25.765 31.896 25.811 ;
     RECT  56.4 23.893 56.808 25.907 ;
     RECT  27.888 19.427 28.296 26.003 ;
     RECT  12.432 25.573 13.512 26.149 ;
     RECT  12.432 26.149 13.944 26.243 ;
     RECT  7.488 25.475 8.712 26.291 ;
     RECT  0.144 24.181 0.168 26.293 ;
     RECT  2.4 23.939 2.712 26.293 ;
     RECT  0.144 26.293 0.216 26.675 ;
     RECT  50.64 25.621 52.44 26.819 ;
     RECT  2.4 26.293 2.856 27.061 ;
     RECT  4.512 26.821 4.536 27.107 ;
     RECT  2.4 27.061 2.904 27.301 ;
     RECT  4.08 27.157 4.104 27.301 ;
     RECT  2.4 27.301 4.104 27.395 ;
     RECT  7.8 26.291 8.712 27.395 ;
     RECT  51 26.819 52.44 27.395 ;
     RECT  2.4 27.395 3.24 27.443 ;
     RECT  34.8 2.151 35.112 27.829 ;
     RECT  12.624 26.243 13.944 27.875 ;
     RECT  0.144 26.675 0.168 27.923 ;
     RECT  51 27.395 52.248 29.029 ;
     RECT  34.8 27.829 35.784 29.077 ;
     RECT  34.8 29.077 36.024 29.267 ;
     RECT  2.4 27.443 2.712 29.317 ;
     RECT  2.4 29.317 2.808 29.603 ;
     RECT  51 29.029 52.344 30.179 ;
     RECT  13.2 27.875 13.944 30.181 ;
     RECT  51 30.179 52.2 30.371 ;
     RECT  0.192 30.325 0.216 30.611 ;
     RECT  3.696 30.565 3.72 30.707 ;
     RECT  12.528 30.181 14.088 30.947 ;
     RECT  17.568 30.133 17.592 31.285 ;
     RECT  18.6 2.151 18.912 31.285 ;
     RECT  28.272 26.003 28.296 31.475 ;
     RECT  51 30.371 51.312 31.861 ;
     RECT  56.4 25.907 56.712 32.101 ;
     RECT  56.4 32.101 56.808 32.243 ;
     RECT  9.936 22.835 11.352 32.437 ;
     RECT  17.568 31.285 18.912 32.437 ;
     RECT  6.384 31.525 6.408 32.483 ;
     RECT  7.8 27.395 8.568 32.483 ;
     RECT  0.144 32.773 0.168 33.059 ;
     RECT  37.152 33.061 37.176 33.491 ;
     RECT  9.936 32.437 11.448 33.683 ;
     RECT  7.8 32.483 8.112 34.117 ;
     RECT  53.424 33.013 53.448 34.307 ;
     RECT  7.2 34.117 8.112 34.501 ;
     RECT  7.2 34.501 8.232 34.693 ;
     RECT  0.144 34.453 0.168 34.739 ;
     RECT  0.192 35.221 0.216 35.459 ;
     RECT  51 31.861 52.248 36.755 ;
     RECT  7.2 34.693 8.952 36.947 ;
     RECT  13.2 30.947 14.088 37.333 ;
     RECT  9.936 33.683 11.352 37.573 ;
     RECT  13.2 37.333 14.76 37.573 ;
     RECT  7.536 36.947 8.952 38.149 ;
     RECT  9.936 37.573 12.168 38.149 ;
     RECT  7.536 38.149 12.168 38.581 ;
     RECT  22.752 35.701 22.776 38.675 ;
     RECT  0.144 38.197 0.168 38.771 ;
     RECT  13.2 37.573 14.808 39.539 ;
     RECT  6.768 38.581 12.168 39.587 ;
     RECT  13.2 39.539 14.76 39.779 ;
     RECT  7.8 39.587 12.168 40.163 ;
     RECT  17.568 32.437 19.224 40.165 ;
     RECT  21.072 39.877 21.096 40.165 ;
     RECT  17.568 40.165 21.096 40.405 ;
     RECT  22.512 38.773 22.536 40.405 ;
     RECT  37.152 36.901 37.176 40.499 ;
     RECT  9.936 40.163 12.168 40.595 ;
     RECT  7.8 40.163 8.52 40.691 ;
     RECT  13.2 39.779 14.664 40.883 ;
     RECT  17.568 40.405 22.536 40.933 ;
     RECT  17.568 40.933 22.632 40.981 ;
     RECT  24 2.151 24.312 41.173 ;
     RECT  6.768 39.587 6.792 41.411 ;
     RECT  0.192 41.653 0.216 41.939 ;
     RECT  17.568 40.981 22.776 41.989 ;
     RECT  23.904 41.173 24.312 41.989 ;
     RECT  17.568 41.989 24.312 42.227 ;
     RECT  31.728 25.811 31.752 42.277 ;
     RECT  2.4 29.603 2.712 42.373 ;
     RECT  20.208 42.227 24.312 42.565 ;
     RECT  16.416 29.845 16.44 42.709 ;
     RECT  17.568 42.227 19.224 42.709 ;
     RECT  29.4 19.427 29.712 42.709 ;
     RECT  20.208 42.565 24.696 43.043 ;
     RECT  31.728 42.277 31.896 43.045 ;
     RECT  20.208 43.043 20.856 43.139 ;
     RECT  40.2 2.151 40.512 43.237 ;
     RECT  13.2 40.883 14.088 43.285 ;
     RECT  29.04 42.709 29.712 43.285 ;
     RECT  22.608 43.043 24.696 43.331 ;
     RECT  2.304 42.373 2.712 43.379 ;
     RECT  51 36.755 52.152 43.573 ;
     RECT  22.608 43.331 22.92 43.667 ;
     RECT  20.208 43.139 20.232 43.859 ;
     RECT  28.464 43.285 29.712 43.861 ;
     RECT  37.296 40.981 37.32 43.955 ;
     RECT  24 43.331 24.696 44.099 ;
     RECT  28.368 43.861 29.712 44.197 ;
     RECT  22.608 43.667 22.68 44.387 ;
     RECT  50.88 43.573 52.152 44.389 ;
     RECT  56.4 32.243 56.712 44.389 ;
     RECT  50.88 44.389 52.248 44.437 ;
     RECT  55.968 44.389 56.712 44.869 ;
     RECT  55.968 44.869 57 44.965 ;
     RECT  31.728 43.045 33.336 45.059 ;
     RECT  50.88 44.437 52.488 45.155 ;
     RECT  28.368 44.197 29.928 45.251 ;
     RECT  29.136 45.251 29.928 45.443 ;
     RECT  29.136 45.443 29.712 45.491 ;
     RECT  55.824 44.965 57 45.635 ;
     RECT  21.072 44.965 21.096 45.731 ;
     RECT  24 44.099 24.312 46.117 ;
     RECT  31.824 45.059 33.336 46.117 ;
     RECT  51 45.155 52.488 46.211 ;
     RECT  31.824 46.117 33.432 46.309 ;
     RECT  55.824 45.635 56.712 46.309 ;
     RECT  24 46.117 25.08 46.787 ;
     RECT  22.608 44.387 22.632 46.931 ;
     RECT  26.64 24.469 26.664 46.933 ;
     RECT  29.28 45.491 29.712 47.029 ;
     RECT  13.104 43.285 14.088 47.125 ;
     RECT  9.936 40.595 11.736 47.171 ;
     RECT  16.416 42.709 19.224 47.269 ;
     RECT  13.104 47.125 14.568 47.363 ;
     RECT  31.824 46.309 33.48 47.605 ;
     RECT  29.28 47.029 30.168 47.653 ;
     RECT  21.648 47.173 21.816 47.845 ;
     RECT  26.64 46.933 26.712 47.845 ;
     RECT  51 46.211 51.312 47.845 ;
     RECT  31.68 47.605 33.48 47.939 ;
     RECT  55.68 46.309 56.712 47.939 ;
     RECT  50.736 47.845 51.312 48.275 ;
     RECT  26.64 47.845 27.336 48.805 ;
     RECT  28.32 47.653 30.168 48.805 ;
     RECT  26.64 48.805 30.168 48.947 ;
     RECT  34.8 29.267 35.784 48.997 ;
     RECT  34.56 48.997 35.784 49.091 ;
     RECT  32.688 47.939 33.432 49.139 ;
     RECT  32.976 49.139 33.432 49.333 ;
     RECT  34.56 49.091 35.304 49.333 ;
     RECT  24 46.787 24.312 49.525 ;
     RECT  37.2 44.437 37.224 49.619 ;
     RECT  21.216 47.845 21.816 50.005 ;
     RECT  32.976 49.333 35.304 50.099 ;
     RECT  52.464 46.211 52.488 50.195 ;
     RECT  9.936 47.171 11.352 50.435 ;
     RECT  24 49.525 25.512 50.437 ;
     RECT  16.416 47.269 20.184 50.677 ;
     RECT  21.216 50.005 22.2 50.677 ;
     RECT  31.68 47.939 31.704 50.677 ;
     RECT  32.976 50.099 33.288 50.771 ;
     RECT  34.56 50.099 35.304 50.771 ;
     RECT  31.584 50.677 31.944 50.819 ;
     RECT  9.936 50.435 11.208 50.963 ;
     RECT  16.416 50.677 22.92 51.253 ;
     RECT  23.904 50.437 25.512 51.253 ;
     RECT  26.64 48.947 29.712 51.253 ;
     RECT  32.976 50.771 33.192 51.347 ;
     RECT  13.2 47.363 14.568 51.349 ;
     RECT  31.584 50.819 31.608 51.923 ;
     RECT  16.416 51.253 25.512 51.973 ;
     RECT  9.936 50.963 9.96 52.211 ;
     RECT  11.04 50.963 11.208 52.307 ;
     RECT  16.08 51.973 25.512 52.357 ;
     RECT  13.2 51.349 14.664 52.405 ;
     RECT  15.84 52.357 25.512 52.405 ;
     RECT  26.496 51.253 29.712 52.405 ;
     RECT  13.2 52.405 29.712 52.499 ;
     RECT  11.184 52.307 11.208 52.595 ;
     RECT  27.504 52.499 29.712 52.981 ;
     RECT  30.864 52.453 30.888 52.981 ;
     RECT  27.504 52.981 30.888 53.365 ;
     RECT  40.2 43.237 41.016 53.411 ;
     RECT  13.2 52.499 26.52 53.557 ;
     RECT  27.504 53.365 31.08 53.557 ;
     RECT  32.976 51.347 33.048 53.557 ;
     RECT  34.8 50.771 35.304 53.557 ;
     RECT  32.976 53.557 33.096 54.085 ;
     RECT  34.224 53.557 35.304 54.085 ;
     RECT  32.976 54.085 35.304 54.133 ;
     RECT  36.432 52.981 36.456 54.133 ;
     RECT  37.632 53.557 37.656 54.133 ;
     RECT  32.976 54.133 36.456 54.419 ;
     RECT  33.168 54.419 36.456 54.421 ;
     RECT  37.632 54.133 38.472 54.421 ;
     RECT  33.168 54.421 38.472 54.709 ;
     RECT  40.2 53.411 40.968 54.805 ;
     RECT  33.168 54.709 38.568 54.949 ;
     RECT  40.2 54.805 41.352 55.237 ;
     RECT  42.624 54.469 42.648 55.237 ;
     RECT  13.2 53.557 31.752 55.525 ;
     RECT  13.2 55.525 32.136 55.717 ;
     RECT  33.168 54.949 38.856 55.717 ;
     RECT  39.936 55.237 41.352 56.293 ;
     RECT  42.624 55.237 42.888 56.293 ;
     RECT  13.2 55.717 38.856 57.013 ;
     RECT  39.936 56.293 42.888 57.013 ;
     RECT  13.2 57.013 43.08 57.157 ;
     RECT  13.2 57.157 43.176 57.205 ;
     RECT  2.4 43.379 2.712 57.249 ;
     RECT  7.8 40.691 8.112 57.249 ;
     RECT  45.6 2.151 45.912 57.249 ;
     RECT  51 48.275 51.312 57.249 ;
     RECT  56.4 47.939 56.712 57.249 ;
     RECT  2.4 57.249 2.52 57.263 ;
     RECT  7.8 57.249 7.92 57.263 ;
     RECT  13.2 57.205 43.272 57.263 ;
     RECT  45.6 57.249 45.72 57.263 ;
     RECT  51 57.249 51.12 57.263 ;
     RECT  56.4 57.249 56.52 57.263 ;
     RECT  14.16 57.263 43.272 59.344 ;
  END
END hfd_vms_wq2_merge
END LIBRARY
